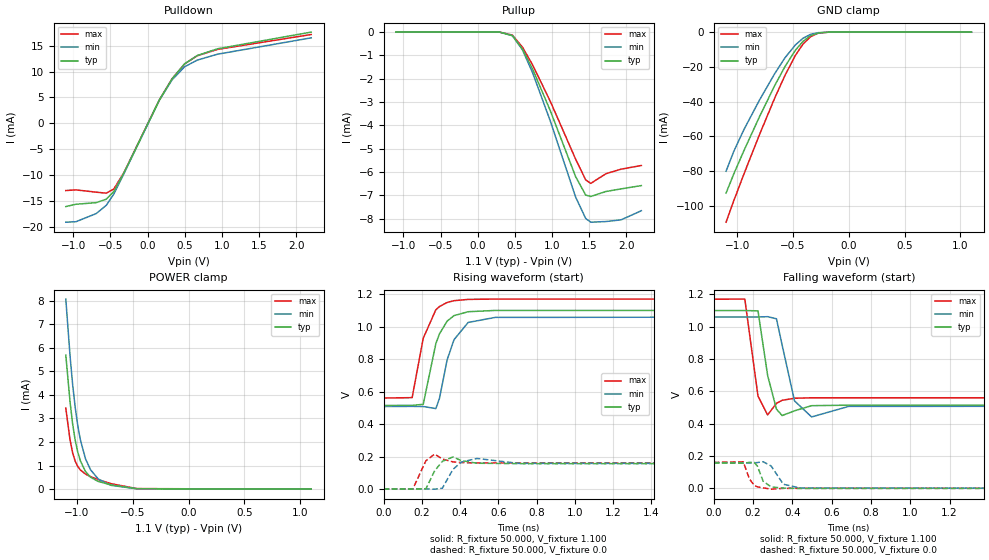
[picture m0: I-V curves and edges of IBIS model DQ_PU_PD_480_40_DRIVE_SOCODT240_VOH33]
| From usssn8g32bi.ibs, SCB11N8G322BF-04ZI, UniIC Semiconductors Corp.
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|   Model DQ_PU_PD_480_40_DRIVE_SOCODT240_VOH33
[Model] DQ_PU_PD_480_40_DRIVE_SOCODT240_VOH33
Model_type I/O
Polarity   Inverting
Vinl =  98.000mV
Vinh =  0.268V
Vmeas =  0.183V
Rref =  50.000
Vref =  0.183V
C_comp   1.020pF   1.010pF   1.030pF
[Model Spec]
Vinh   0.268V   0.262V   0.280V
Vinl   98.000mV   92.000mV   0.110V
Vmeas   0.183V   0.177V   0.195V
Vref   0.183V   0.177V   0.195V
Rref   50.000   NA   NA
[Temperature Range]   25.000   85.000   -40.000
[Voltage Range]   1.100V   1.060V   1.170V
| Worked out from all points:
|   slope of the pulldown table from 0 to 0.165 V, typ, clamps not added: 35.3 ohm
|   GND clamp passes 1 mA (typ) near -0.30 V on its own axis
|   POWER clamp passes 1 mA (typ) near -0.95 V on its own axis
|   rising waveform, R_fixture 50.000, V_fixture 1.100: 20-80 % time 76.4ps typ, 79.4ps min, 73.5ps max; typ from 0.514 V to 1.1 V
|   rising waveform, R_fixture 50.000, V_fixture 0.0: 20-80 % time 36.1ps typ, 44ps min, 29.7ps max; typ from 0 V to 0.156 V
|   falling waveform, R_fixture 50.000, V_fixture 1.100: 20-80 % time 40.5ps typ, 51.4ps min, 33.2ps max; typ from 1.1 V to 0.514 V
|   falling waveform, R_fixture 50.000, V_fixture 0.0: 20-80 % time 33.3ps typ, 48.4ps min, 30.2ps max; typ from 0.156 V to 0 V
[Pulldown]
|Voltage   I(typ)   I(min)   I(max)
-1.1V     -16.13mA   -19.15mA   -13.03mA
-964mV    -15.68mA   -19.06mA   -12.9mA
-692mV    -15.37mA   -17.49mA   -13.34mA
-556mV    -14.7mA    -15.89mA   -13.53mA
-454mV    -13.2mA    -13.69mA   -12.73mA
-318mV    -9.609mA   -9.745mA   -9.529mA
158mV     4.492mA    4.453mA    4.512mA
328mV     8.568mA    8.368mA    8.576mA
498mV     11.5mA     10.93mA    11.48mA
668mV     13.1mA     12.21mA    13.05mA
940mV     14.4mA     13.35mA    14.28mA
2.2V      17.63mA    16.52mA    17.16mA
[Pullup]
|Voltage   I(typ)   I(min)   I(max)
-1.1V     500pA      2.606nA    0A
296mV     -2.948uA   -3.529uA   -1.641uA
466mV     -154.8uA   -152.1uA   -129.1uA
602mV     -725.8uA   -765uA     -649.5uA
738mV     -1.585mA   -1.746mA   -1.41mA
976mV     -3.374mA   -3.816mA   -2.972mA
1.316V    -6.198mA   -7.072mA   -5.446mA
1.452V    -6.989mA   -7.995mA   -6.341mA
1.52V     -7.049mA   -8.152mA   -6.489mA
1.724V    -6.835mA   -8.124mA   -6.072mA
1.928V    -6.723mA   -8.051mA   -5.878mA
2.2V      -6.582mA   -7.66mA    -5.721mA
[GND_clamp]
|Voltage   I(typ)   I(min)   I(max)
-1.1V     -92.78mA   -80.14mA   -109.5mA
-1.031V   -81.73mA   -68.77mA   -97.17mA
-939mV    -68.18mA   -56.07mA   -81.64mA
-801mV    -48.85mA   -39.25mA   -59.15mA
-663mV    -30.71mA   -23.84mA   -37.89mA
-571mV    -19.76mA   -14.75mA   -24.85mA
-479mV    -10.5mA    -7.415mA   -13.5mA
-410mV    -5.313mA   -3.546mA   -6.916mA
-341mV    -2.007mA   -1.262mA   -2.59mA
-272mV    -506.9uA   -323.5uA   -609.8uA
-180mV    -45.65uA   -36.06uA   -43.55uA
1.1V      0A         0A         0A
[POWER_clamp]
|Voltage   I(typ)   I(min)   I(max)
-1.1V     5.691mA    8.066mA    3.44mA
-1.062V   3.709mA    5.665mA    2.092mA
-1.039V   2.781mA    4.457mA    1.546mA
-1.016V   2.086mA    3.48mA     1.193mA
-993mV    1.578mA    2.707mA    966.5uA
-970mV    1.21mA     2.107mA    818.5uA
-924mV    750.8uA    1.296mA    641.3uA
-878mV    507uA      821.4uA    530.2uA
-809mV    327.4uA    430uA      403.3uA
-694mV    178.4uA    161uA      233uA
-464mV    19.89uA    15.19uA    23.61uA
1.1V      0A         0A         0A
[Ramp]
| variable   typ   min   max
dV/dt_r   93.601m/36.231p   94.433m/44.047p   96.210m/29.958p
dV/dt_f   0.351/40.612p   0.331/51.354p   0.366/33.320p
R_load = 50.000
[Rising Waveform]
R_fixture= 50.000
V_fixture= 1.100
V_fixture_min= 1.060
V_fixture_max= 1.170
|time   V(typ)   V(min)   V(max)
0s        514.4mV    508.1mV    560.3mV
149ps     515.2mV    508.7mV    562.7mV
207ps     521.4mV    507.9mV    928.6mV
273ps     895.6mV    495.3mV    1.104V
292ps     956mV      558.4mV    1.124V
332ps     1.034V     795.8mV    1.149V
368ps     1.068V     919.6mV    1.16V
442ps     1.092V     1.026V     1.168V
584ps     1.1V       1.057V     1.17V
3ns       1.1V       1.06V      1.17V
[Rising Waveform]
R_fixture= 50.000
V_fixture= 0.0
V_fixture_min= 0.0
V_fixture_max= 0.0
|time   V(typ)   V(min)   V(max)
0s        2.608uV    4.994uV    616.3nV
153ps     334.6uV    6.715uV    864.6uV
221ps     1.036mV    601.6uV    174mV
267ps     112.8mV    -1.201mV   214.9mV
307ps     170.1mV    4.693mV    184.7mV
362ps     197.2mV    120mV      166.9mV
406ps     175.3mV    165.6mV    162.6mV
488ps     158.6mV    188mV      160.7mV
706ps     156mV      157.6mV    160.3mV
3ns       156mV      157.4mV    160.3mV
[Falling Waveform]
R_fixture= 50.000
V_fixture= 1.100
V_fixture_min= 1.060
V_fixture_max= 1.170
|time   V(typ)   V(min)   V(max)
0s        1.1V       1.06V      1.17V
158ps     1.1V       1.06V      1.171V
225ps     1.098V     1.06V      570.6mV
274ps     698.7mV    1.062V     454.3mV
319ps     490mV      1.049V     525.6mV
348ps     450.1mV    885.6mV    544.7mV
411ps     479.4mV    540.7mV    557.3mV
498ps     511.3mV    441.6mV    560mV
687ps     514.4mV    507mV      560.3mV
3ns       514.4mV    508.1mV    560.3mV
[Falling Waveform]
R_fixture= 50.000
V_fixture= 0.0
V_fixture_min= 0.0
V_fixture_max= 0.0
|time   V(typ)   V(min)   V(max)
0s        156mV      157.4mV    160.3mV
150ps     155.8mV    157.2mV    163.8mV
182ps     160.3mV    157mV      56.65mV
206ps     160.8mV    157.6mV    18.33mV
222ps     137.2mV    159.3mV    8.829mV
251ps     44.49mV    164.5mV    2.7mV
292ps     8.449mV    138.2mV    -5.342mV
354ps     1.084mV    25.17mV    -437.4uV
440ps     -1.073mV   1.675mV    -10.17uV
3ns       2.504uV    4.982uV    347.8nV
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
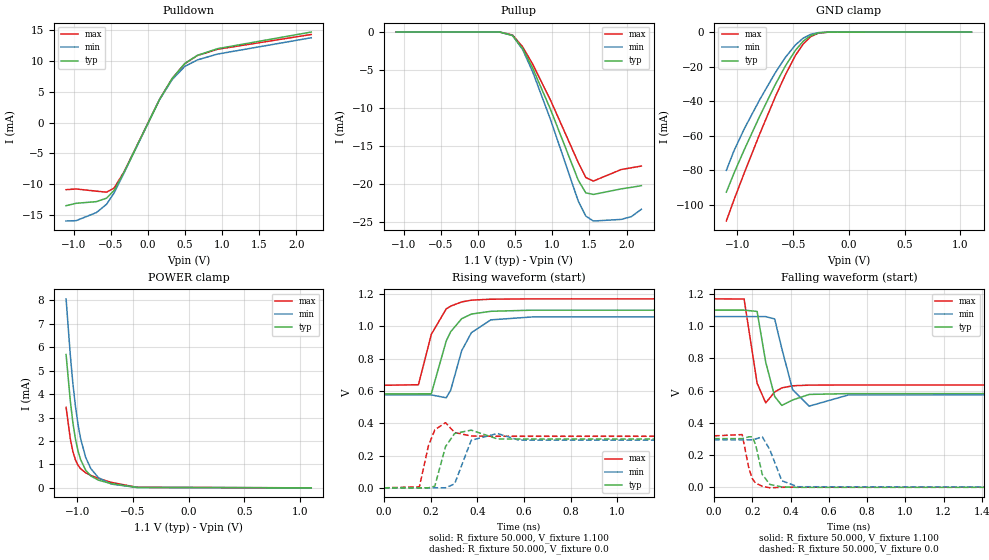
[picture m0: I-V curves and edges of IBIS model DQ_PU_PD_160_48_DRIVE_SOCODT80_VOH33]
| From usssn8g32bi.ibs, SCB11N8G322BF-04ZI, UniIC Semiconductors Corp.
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|   Model DQ_PU_PD_160_48_DRIVE_SOCODT80_VOH33
[Model] DQ_PU_PD_160_48_DRIVE_SOCODT80_VOH33
Model_type I/O
Polarity   Inverting
Vinl =  98.000mV
Vinh =  0.268V
Vmeas =  0.183V
Rref =  50.000
Vref =  0.183V
C_comp   1.020pF   1.010pF   1.030pF
[Model Spec]
Vinh   0.268V   0.262V   0.280V
Vinl   98.000mV   92.000mV   0.110V
Vmeas   0.183V   0.177V   0.195V
Vref   0.183V   0.177V   0.195V
Rref   50.000   NA   NA
[Temperature Range]   25.000   85.000   -40.000
[Voltage Range]   1.100V   1.060V   1.170V
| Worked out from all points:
|   slope of the pulldown table from 0 to 0.165 V, typ, clamps not added: 42.3 ohm
|   GND clamp passes 1 mA (typ) near -0.30 V on its own axis
|   POWER clamp passes 1 mA (typ) near -0.95 V on its own axis
|   rising waveform, R_fixture 50.000, V_fixture 1.100: 20-80 % time 74.8ps typ, 77.1ps min, 72.3ps max; typ from 0.582 V to 1.1 V
|   rising waveform, R_fixture 50.000, V_fixture 0.0: 20-80 % time 30.4ps typ, 37.1ps min, 24.9ps max; typ from 0 V to 0.302 V
|   falling waveform, R_fixture 50.000, V_fixture 1.100: 20-80 % time 42.6ps typ, 53.7ps min, 34.5ps max; typ from 1.1 V to 0.582 V
|   falling waveform, R_fixture 50.000, V_fixture 0.0: 20-80 % time 36.7ps typ, 52.9ps min, 32.5ps max; typ from 0.302 V to 0 V
[Pulldown]
|Voltage   I(typ)   I(min)   I(max)
-1.1V     -13.51mA   -16mA      -10.91mA
-964mV    -13.12mA   -15.94mA   -10.79mA
-692mV    -12.85mA   -14.63mA   -11.15mA
-556mV    -12.29mA   -13.29mA   -11.31mA
-454mV    -11.04mA   -11.45mA   -10.65mA
-318mV    -8.03mA    -8.142mA   -7.964mA
158mV     3.751mA    3.718mA    3.768mA
328mV     7.153mA    6.985mA    7.158mA
498mV     9.598mA    9.123mA    9.581mA
668mV     10.93mA    10.18mA    10.89mA
940mV     12.01mA    11.13mA    11.91mA
2.2V      14.71mA    13.78mA    14.31mA
[Pullup]
|Voltage   I(typ)   I(min)   I(max)
-1.1V     1.606nA    7.718nA    0A
296mV     -8.845uA   -10.59uA   -4.922uA
466mV     -464.7uA   -456.5uA   -387.5uA
602mV     -2.18mA    -2.299mA   -1.951mA
738mV     -4.764mA   -5.249mA   -4.236mA
976mV     -10.14mA   -11.47mA   -8.932mA
1.35V     -19.45mA   -22.19mA   -17.13mA
1.452V    -21.12mA   -24.17mA   -19.11mA
1.554V    -21.33mA   -24.82mA   -19.57mA
1.928V    -20.6mA    -24.61mA   -18.06mA
2.064V    -20.4mA    -24.25mA   -17.83mA
2.2V      -20.18mA   -23.28mA   -17.6mA
[GND_clamp]
|Voltage   I(typ)   I(min)   I(max)
-1.1V     -92.78mA   -80.14mA   -109.5mA
-1.031V   -81.73mA   -68.77mA   -97.17mA
-939mV    -68.18mA   -56.07mA   -81.64mA
-801mV    -48.85mA   -39.25mA   -59.15mA
-663mV    -30.71mA   -23.84mA   -37.89mA
-571mV    -19.76mA   -14.75mA   -24.85mA
-479mV    -10.5mA    -7.415mA   -13.5mA
-410mV    -5.313mA   -3.546mA   -6.916mA
-341mV    -2.007mA   -1.262mA   -2.59mA
-272mV    -506.9uA   -323.5uA   -609.8uA
-180mV    -45.65uA   -36.06uA   -43.55uA
1.1V      0A         0A         0A
[POWER_clamp]
|Voltage   I(typ)   I(min)   I(max)
-1.1V     5.691mA    8.066mA    3.44mA
-1.062V   3.709mA    5.665mA    2.092mA
-1.039V   2.781mA    4.457mA    1.546mA
-1.016V   2.086mA    3.48mA     1.193mA
-993mV    1.578mA    2.707mA    966.5uA
-970mV    1.21mA     2.107mA    818.5uA
-924mV    750.8uA    1.296mA    641.3uA
-878mV    507uA      821.4uA    530.2uA
-809mV    327.4uA    430uA      403.3uA
-694mV    178.4uA    161uA      233uA
-464mV    19.89uA    15.19uA    23.61uA
1.1V      0A         0A         0A
[Ramp]
| variable   typ   min   max
dV/dt_r   0.181/30.338p   0.177/37.221p   0.192/24.997p
dV/dt_f   0.311/42.683p   0.291/53.720p   0.321/34.473p
R_load = 50.000
[Rising Waveform]
R_fixture= 50.000
V_fixture= 1.100
V_fixture_min= 1.060
V_fixture_max= 1.170
|time   V(typ)   V(min)   V(max)
0s        581.6mV    575.3mV    635mV
148ps     582.3mV    575.9mV    638.4mV
203ps     582.5mV    575.5mV    950.6mV
267ps     909.6mV    557.5mV    1.108V
286ps     966.4mV    604.3mV    1.125V
333ps     1.047V     848.3mV    1.151V
375ps     1.076V     961mV      1.162V
458ps     1.093V     1.04V      1.168V
635ps     1.1V       1.058V     1.17V
3ns       1.1V       1.06V      1.17V
[Rising Waveform]
R_fixture= 50.000
V_fixture= 0.0
V_fixture_min= 0.0
V_fixture_max= 0.0
|time   V(typ)   V(min)   V(max)
0s        2.898uV    5.55uV     685nV
152ps     91.66uV    20.89uV    6.439mV
191ps     381.7uV    61.02uV    262.2mV
218ps     10.25mV    267.5uV    359mV
264ps     255.6mV    221.2uV    403.3mV
303ps     336.5mV    24.48mV    342.4mV
374ps     357.2mV    294.4mV    320.9mV
487ps     302.7mV    336.6mV    319.2mV
578ps     302.1mV    295.3mV    319.2mV
3ns       302.1mV    295.1mV    319.2mV
[Falling Waveform]
R_fixture= 50.000
V_fixture= 1.100
V_fixture_min= 1.060
V_fixture_max= 1.170
|time   V(typ)   V(min)   V(max)
0s        1.1V       1.06V      1.17V
157ps     1.1V       1.06V      1.169V
225ps     1.092V     1.06V      646.1mV
270ps     776.8mV    1.06V      524.1mV
317ps     563.5mV    1.045V     591.6mV
354ps     508.2mV    861.6mV    617mV
411ps     541.9mV    605.2mV    630.1mV
497ps     576.5mV    503.7mV    634.3mV
705ps     581.5mV    574mV      635mV
3ns       581.6mV    575.3mV    635mV
[Falling Waveform]
R_fixture= 50.000
V_fixture= 0.0
V_fixture_min= 0.0
V_fixture_max= 0.0
|time   V(typ)   V(min)   V(max)
0s        302.1mV    295.1mV    319.2mV
147ps     301.7mV    294.7mV    326.9mV
182ps     313.2mV    294.1mV    117.4mV
199ps     313.6mV    295.3mV    55.12mV
217ps     266mV      299.6mV    25.58mV
252ps     79.39mV    313.4mV    6.149mV
292ps     17.21mV    232.2mV    -3.831mV
354ps     2.133mV    40.59mV    -401.6uV
438ps     -1.021mV   3.098mV    -13.98uV
3ns       -956.6nV   5.401uV    179.7nV
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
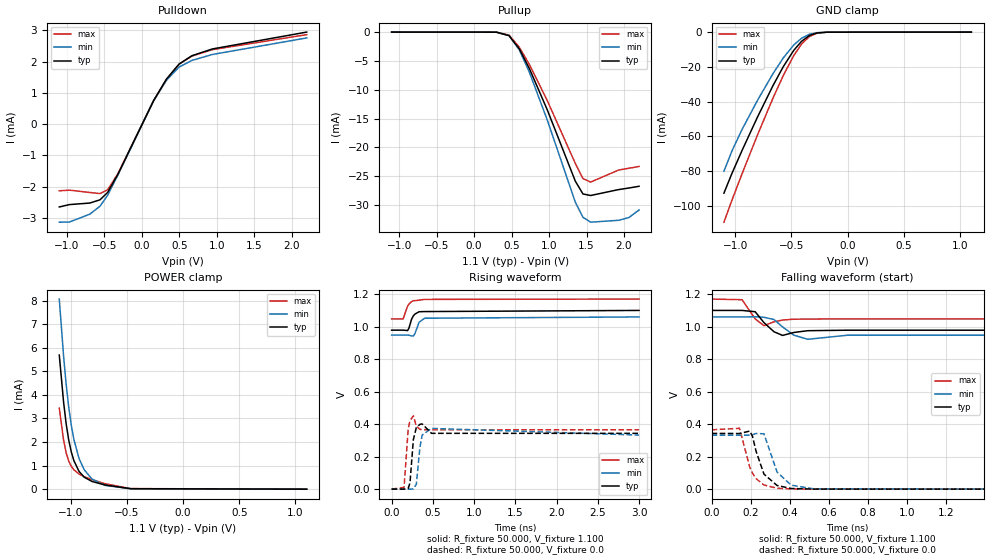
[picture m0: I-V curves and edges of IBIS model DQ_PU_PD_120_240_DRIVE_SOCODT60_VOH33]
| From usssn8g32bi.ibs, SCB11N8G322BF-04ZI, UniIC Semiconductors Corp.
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|   Model DQ_PU_PD_120_240_DRIVE_SOCODT60_VOH33
[Model] DQ_PU_PD_120_240_DRIVE_SOCODT60_VOH33
Model_type I/O
Polarity   Inverting
Vinl =  98.000mV
Vinh =  0.268V
Vmeas =  0.183V
Rref =  50.000
Vref =  0.183V
C_comp   1.020pF   1.010pF   1.030pF
[Model Spec]
Vinh   0.268V   0.262V   0.280V
Vinl   98.000mV   92.000mV   0.110V
Vmeas   0.183V   0.177V   0.195V
Vref   0.183V   0.177V   0.195V
Rref   50.000   NA   NA
[Temperature Range]   25.000   85.000   -40.000
[Voltage Range]   1.100V   1.060V   1.170V
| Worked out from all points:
|   slope of the pulldown table from 0 to 0.165 V, typ, clamps not added: 211 ohm
|   GND clamp passes 1 mA (typ) near -0.30 V on its own axis
|   POWER clamp passes 1 mA (typ) near -0.95 V on its own axis
|   rising waveform, R_fixture 50.000, V_fixture 1.100: 20-80 % time 62ps typ, 58.1ps min, 63.2ps max; typ from 0.978 V to 1.1 V
|   rising waveform, R_fixture 50.000, V_fixture 0.0: 20-80 % time 29.3ps typ, 36.2ps min, 23.8ps max; typ from 0 V to 0.343 V
|   falling waveform, R_fixture 50.000, V_fixture 1.100: 20-80 % time 47.3ps typ, 62.3ps min, 36.3ps max; typ from 1.1 V to 0.978 V
|   falling waveform, R_fixture 50.000, V_fixture 0.0: 20-80 % time 62.1ps typ, 67.8ps min, 59.5ps max; typ from 0.343 V to 0 V
[Pulldown]
|Voltage   I(typ)   I(min)   I(max)
-1.1V     -2.652mA   -3.14mA    -2.134mA
-964mV    -2.576mA   -3.135mA   -2.114mA
-692mV    -2.527mA   -2.882mA   -2.189mA
-556mV    -2.422mA   -2.626mA   -2.223mA
-454mV    -2.185mA   -2.274mA   -2.101mA
-318mV    -1.604mA   -1.629mA   -1.589mA
158mV     752.2uA    745.4uA    755.4uA
328mV     1.434mA    1.4mA      1.435mA
498mV     1.924mA    1.828mA    1.92mA
668mV     2.19mA     2.04mA     2.18mA
940mV     2.407mA    2.23mA     2.385mA
2.2V      2.948mA    2.761mA    2.866mA
[Pullup]
|Voltage   I(typ)   I(min)   I(max)
-1.1V     2.1nA      10.33nA    0A
296mV     -11.79uA   -14.12uA   -6.562uA
466mV     -619.2uA   -608.2uA   -516.4uA
602mV     -2.903mA   -3.06mA    -2.598mA
738mV     -6.341mA   -6.984mA   -5.639mA
976mV     -13.49mA   -15.26mA   -11.89mA
1.35V     -25.87mA   -29.51mA   -22.79mA
1.452V    -28.09mA   -32.14mA   -25.42mA
1.554V    -28.36mA   -32.99mA   -26.03mA
1.928V    -27.33mA   -32.66mA   -23.94mA
2.064V    -27.06mA   -32.19mA   -23.63mA
2.2V      -26.76mA   -30.87mA   -23.32mA
[GND_clamp]
|Voltage   I(typ)   I(min)   I(max)
-1.1V     -92.78mA   -80.14mA   -109.5mA
-1.031V   -81.73mA   -68.77mA   -97.17mA
-939mV    -68.18mA   -56.07mA   -81.64mA
-801mV    -48.85mA   -39.25mA   -59.15mA
-663mV    -30.71mA   -23.84mA   -37.89mA
-571mV    -19.76mA   -14.75mA   -24.85mA
-479mV    -10.5mA    -7.415mA   -13.5mA
-410mV    -5.313mA   -3.546mA   -6.916mA
-341mV    -2.007mA   -1.262mA   -2.59mA
-272mV    -506.9uA   -323.5uA   -609.8uA
-180mV    -45.65uA   -36.06uA   -43.55uA
1.1V      0A         0A         0A
[POWER_clamp]
|Voltage   I(typ)   I(min)   I(max)
-1.1V     5.691mA    8.066mA    3.44mA
-1.062V   3.709mA    5.665mA    2.092mA
-1.039V   2.781mA    4.457mA    1.546mA
-1.016V   2.086mA    3.48mA     1.193mA
-993mV    1.578mA    2.707mA    966.5uA
-970mV    1.21mA     2.107mA    818.5uA
-924mV    750.8uA    1.296mA    641.3uA
-878mV    507uA      821.4uA    530.2uA
-809mV    327.4uA    430uA      403.3uA
-694mV    178.4uA    161uA      233uA
-464mV    19.89uA    15.19uA    23.61uA
1.1V      0A         0A         0A
[Ramp]
| variable   typ   min   max
dV/dt_r   0.206/29.379p   0.200/36.204p   0.219/24.028p
dV/dt_f   72.904m/47.402p   67.052m/62.298p   73.268m/36.318p
R_load = 50.000
[Rising Waveform]
R_fixture= 50.000
V_fixture= 1.100
V_fixture_min= 1.060
V_fixture_max= 1.170
|time   V(typ)   V(min)   V(max)
0s        978.5mV    948.3mV    1.048V
140ps     978.8mV    948.4mV    1.048V
194ps     976mV      948.5mV    1.127V
210ps     990.9mV    947.5mV    1.139V
242ps     1.046V     943mV      1.154V
263ps     1.066V     942.5mV    1.16V
281ps     1.077V     955.1mV    1.16V
333ps     1.092V     1.027V     1.163V
401ps     1.093V     1.052V     1.168V
3ns       1.1V       1.06V      1.17V
[Rising Waveform]
R_fixture= 50.000
V_fixture= 0.0
V_fixture_min= 0.0
V_fixture_max= 0.0
|time   V(typ)   V(min)   V(max)
0s        5.235uV    10.02uV    1.24uV
151ps     -258.7uV   64.02uV    10.64mV
201ps     3.499mV    -217.6uV   369.5mV
223ps     39.28mV    -435.2uV   421.7mV
264ps     305.5mV    1.271mV    451.1mV
300ps     379.6mV    29.77mV    386.5mV
343ps     398.6mV    256.6mV    368.1mV
371ps     401.1mV    332.8mV    366.1mV
484ps     343.4mV    373.7mV    365.2mV
3ns       343.2mV    332.5mV    365.2mV
[Falling Waveform]
R_fixture= 50.000
V_fixture= 1.100
V_fixture_min= 1.060
V_fixture_max= 1.170
|time   V(typ)   V(min)   V(max)
0s        1.1V       1.06V      1.17V
156ps     1.1V       1.06V      1.166V
223ps     1.092V     1.061V     1.048V
268ps     1.025V     1.058V     1.006V
319ps     969mV      1.044V     1.03V
363ps     946.2mV    998.7mV    1.041V
421ps     964.5mV    947.6mV    1.046V
492ps     975.3mV    922.4mV    1.047V
696ps     978.4mV    947.6mV    1.048V
3ns       978.5mV    948.3mV    1.048V
[Falling Waveform]
R_fixture= 50.000
V_fixture= 0.0
V_fixture_min= 0.0
V_fixture_max= 0.0
|time   V(typ)   V(min)   V(max)
0s        343.2mV    332.5mV    365.2mV
143ps     342.5mV    332mV      374.6mV
195ps     357.6mV    332.2mV    136.1mV
209ps     326.1mV    335.3mV    99.03mV
228ps     231.6mV    342.8mV    64.35mV
268ps     92.49mV    340.6mV    25.71mV
335ps     22.55mV    105mV      5.646mV
407ps     4.206mV    24.7mV     1.203mV
523ps     417.4uV    2.049mV    99.42uV
3ns       5.223uV    10.02uV    1.279uV
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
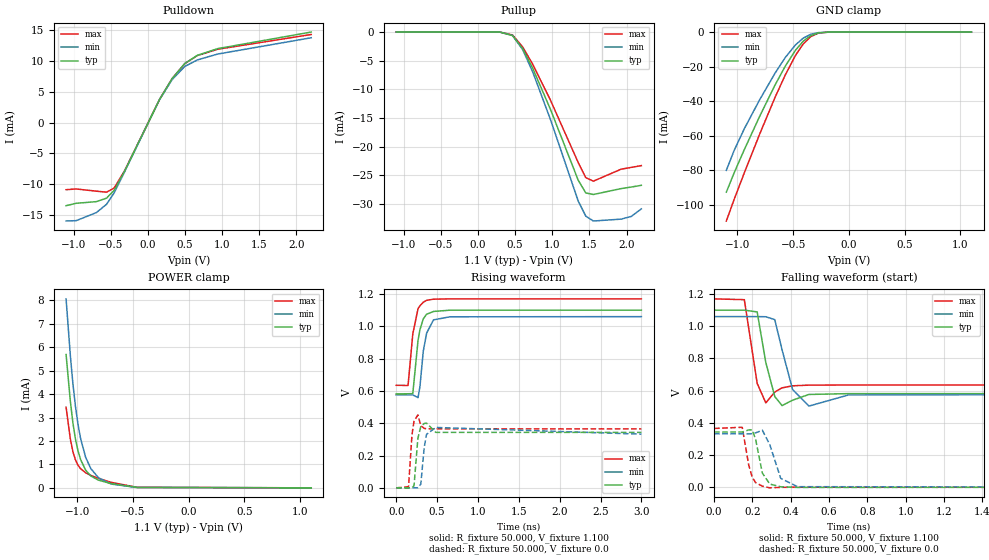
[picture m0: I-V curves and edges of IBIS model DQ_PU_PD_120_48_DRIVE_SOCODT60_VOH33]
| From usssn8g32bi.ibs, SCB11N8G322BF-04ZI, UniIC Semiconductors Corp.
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|   Model DQ_PU_PD_120_48_DRIVE_SOCODT60_VOH33
[Model] DQ_PU_PD_120_48_DRIVE_SOCODT60_VOH33
Model_type I/O
Polarity   Inverting
Vinl =  98.000mV
Vinh =  0.268V
Vmeas =  0.183V
Rref =  50.000
Vref =  0.183V
C_comp   1.020pF   1.010pF   1.030pF
[Model Spec]
Vinh   0.268V   0.262V   0.280V
Vinl   98.000mV   92.000mV   0.110V
Vmeas   0.183V   0.177V   0.195V
Vref   0.183V   0.177V   0.195V
Rref   50.000   NA   NA
[Temperature Range]   25.000   85.000   -40.000
[Voltage Range]   1.100V   1.060V   1.170V
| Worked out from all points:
|   slope of the pulldown table from 0 to 0.165 V, typ, clamps not added: 42.3 ohm
|   GND clamp passes 1 mA (typ) near -0.30 V on its own axis
|   POWER clamp passes 1 mA (typ) near -0.95 V on its own axis
|   rising waveform, R_fixture 50.000, V_fixture 1.100: 20-80 % time 74.6ps typ, 76.3ps min, 72.2ps max; typ from 0.582 V to 1.1 V
|   rising waveform, R_fixture 50.000, V_fixture 0.0: 20-80 % time 28.7ps typ, 35.2ps min, 23.5ps max; typ from 0 V to 0.343 V
|   falling waveform, R_fixture 50.000, V_fixture 1.100: 20-80 % time 42.8ps typ, 54ps min, 34.6ps max; typ from 1.1 V to 0.582 V
|   falling waveform, R_fixture 50.000, V_fixture 0.0: 20-80 % time 37ps typ, 52.6ps min, 32.8ps max; typ from 0.343 V to 0 V
[Pulldown]
|Voltage   I(typ)   I(min)   I(max)
-1.1V     -13.51mA   -16mA      -10.91mA
-964mV    -13.12mA   -15.94mA   -10.79mA
-692mV    -12.85mA   -14.63mA   -11.15mA
-556mV    -12.29mA   -13.29mA   -11.31mA
-454mV    -11.04mA   -11.45mA   -10.65mA
-318mV    -8.03mA    -8.142mA   -7.964mA
158mV     3.751mA    3.718mA    3.768mA
328mV     7.153mA    6.985mA    7.158mA
498mV     9.598mA    9.123mA    9.581mA
668mV     10.93mA    10.18mA    10.89mA
940mV     12.01mA    11.13mA    11.91mA
2.2V      14.71mA    13.78mA    14.31mA
[Pullup]
|Voltage   I(typ)   I(min)   I(max)
-1.1V     2.1nA      10.33nA    0A
296mV     -11.79uA   -14.12uA   -6.562uA
466mV     -619.2uA   -608.2uA   -516.4uA
602mV     -2.903mA   -3.06mA    -2.598mA
738mV     -6.341mA   -6.984mA   -5.639mA
976mV     -13.49mA   -15.26mA   -11.89mA
1.35V     -25.87mA   -29.51mA   -22.79mA
1.452V    -28.09mA   -32.14mA   -25.42mA
1.554V    -28.36mA   -32.99mA   -26.03mA
1.928V    -27.33mA   -32.66mA   -23.94mA
2.064V    -27.06mA   -32.19mA   -23.63mA
2.2V      -26.76mA   -30.87mA   -23.32mA
[GND_clamp]
|Voltage   I(typ)   I(min)   I(max)
-1.1V     -92.78mA   -80.14mA   -109.5mA
-1.031V   -81.73mA   -68.77mA   -97.17mA
-939mV    -68.18mA   -56.07mA   -81.64mA
-801mV    -48.85mA   -39.25mA   -59.15mA
-663mV    -30.71mA   -23.84mA   -37.89mA
-571mV    -19.76mA   -14.75mA   -24.85mA
-479mV    -10.5mA    -7.415mA   -13.5mA
-410mV    -5.313mA   -3.546mA   -6.916mA
-341mV    -2.007mA   -1.262mA   -2.59mA
-272mV    -506.9uA   -323.5uA   -609.8uA
-180mV    -45.65uA   -36.06uA   -43.55uA
1.1V      0A         0A         0A
[POWER_clamp]
|Voltage   I(typ)   I(min)   I(max)
-1.1V     5.691mA    8.066mA    3.44mA
-1.062V   3.709mA    5.665mA    2.092mA
-1.039V   2.781mA    4.457mA    1.546mA
-1.016V   2.086mA    3.48mA     1.193mA
-993mV    1.578mA    2.707mA    966.5uA
-970mV    1.21mA     2.107mA    818.5uA
-924mV    750.8uA    1.296mA    641.3uA
-878mV    507uA      821.4uA    530.2uA
-809mV    327.4uA    430uA      403.3uA
-694mV    178.4uA    161uA      233uA
-464mV    19.89uA    15.19uA    23.61uA
1.1V      0A         0A         0A
[Ramp]
| variable   typ   min   max
dV/dt_r   0.206/28.866p   0.200/35.270p   0.219/23.794p
dV/dt_f   0.311/42.802p   0.291/53.959p   0.321/34.634p
R_load = 50.000
[Rising Waveform]
R_fixture= 50.000
V_fixture= 1.100
V_fixture_min= 1.060
V_fixture_max= 1.170
|time   V(typ)   V(min)   V(max)
0s        581.6mV    575.3mV    635mV
145ps     582.5mV    575.8mV    633.8mV
203ps     583.2mV    575.5mV    953mV
267ps     912.5mV    558.4mV    1.109V
290ps     978.1mV    624.6mV    1.127V
331ps     1.046V     844.9mV    1.149V
372ps     1.075V     957.8mV    1.161V
456ps     1.092V     1.04V      1.168V
657ps     1.1V       1.059V     1.17V
3ns       1.1V       1.06V      1.17V
[Rising Waveform]
R_fixture= 50.000
V_fixture= 0.0
V_fixture_min= 0.0
V_fixture_max= 0.0
|time   V(typ)   V(min)   V(max)
0s        2.898uV    5.55uV     685nV
151ps     18.65uV    28.55uV    7.153mV
193ps     600.2uV    46.35uV    328.3mV
218ps     13.39mV    176.7uV    413.3mV
265ps     306.2mV    420.2uV    451.1mV
301ps     380mV      23.2mV     385.2mV
343ps     398.5mV    251.7mV    368.1mV
371ps     401mV      331.4mV    366.1mV
485ps     343.4mV    373.8mV    365.2mV
3ns       343.2mV    332.5mV    365.2mV
[Falling Waveform]
R_fixture= 50.000
V_fixture= 1.100
V_fixture_min= 1.060
V_fixture_max= 1.170
|time   V(typ)   V(min)   V(max)
0s        1.1V       1.06V      1.17V
158ps     1.1V       1.06V      1.165V
225ps     1.089V     1.06V      645.6mV
270ps     775.3mV    1.059V     524mV
317ps     563.1mV    1.041V     591.6mV
355ps     507.3mV    853.4mV    617.4mV
410ps     540.7mV    607.1mV    630mV
495ps     576.3mV    504mV      634.3mV
704ps     581.5mV    574mV      635mV
3ns       581.6mV    575.3mV    635mV
[Falling Waveform]
R_fixture= 50.000
V_fixture= 0.0
V_fixture_min= 0.0
V_fixture_max= 0.0
|time   V(typ)   V(min)   V(max)
0s        343.2mV    332.5mV    365.2mV
147ps     342.8mV    332mV      372.4mV
181ps     356.1mV    331.4mV    137.7mV
199ps     356.1mV    332.7mV    61.72mV
217ps     297.4mV    337.8mV    28.59mV
252ps     88.29mV    354.3mV    6.827mV
291ps     19.73mV    264.4mV    -3.688mV
348ps     2.922mV    55.22mV    -493.7uV
436ps     -1.09mV    3.576mV    -14.38uV
3ns       -732.6nV   5.513uV    284.7nV
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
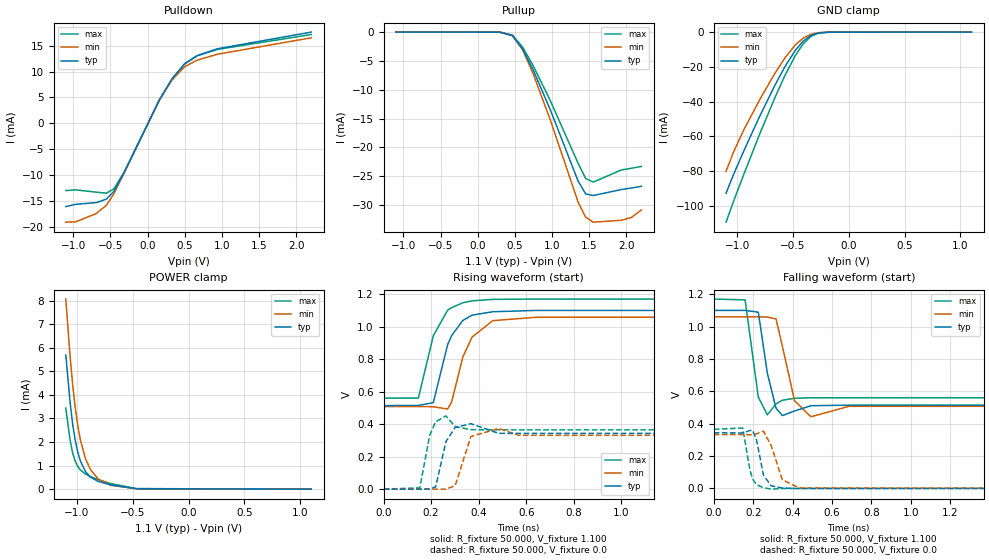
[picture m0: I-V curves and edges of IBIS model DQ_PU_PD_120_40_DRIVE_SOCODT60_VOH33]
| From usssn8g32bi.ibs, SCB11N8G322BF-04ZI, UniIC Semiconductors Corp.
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|   Model DQ_PU_PD_120_40_DRIVE_SOCODT60_VOH33
[Model] DQ_PU_PD_120_40_DRIVE_SOCODT60_VOH33
Model_type I/O
Polarity   Inverting
Vinl =  98.000mV
Vinh =  0.268V
Vmeas =  0.183V
Rref =  50.000
Vref =  0.183V
C_comp   1.020pF   1.010pF   1.030pF
[Model Spec]
Vinh   0.268V   0.262V   0.280V
Vinl   98.000mV   92.000mV   0.110V
Vmeas   0.183V   0.177V   0.195V
Vref   0.183V   0.177V   0.195V
Rref   50.000   NA   NA
[Temperature Range]   25.000   85.000   -40.000
[Voltage Range]   1.100V   1.060V   1.170V
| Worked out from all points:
|   slope of the pulldown table from 0 to 0.165 V, typ, clamps not added: 35.3 ohm
|   GND clamp passes 1 mA (typ) near -0.30 V on its own axis
|   POWER clamp passes 1 mA (typ) near -0.95 V on its own axis
|   rising waveform, R_fixture 50.000, V_fixture 1.100: 20-80 % time 75.7ps typ, 77.9ps min, 73.1ps max; typ from 0.514 V to 1.1 V
|   rising waveform, R_fixture 50.000, V_fixture 0.0: 20-80 % time 28.6ps typ, 35.1ps min, 23.5ps max; typ from 0 V to 0.343 V
|   falling waveform, R_fixture 50.000, V_fixture 1.100: 20-80 % time 40.9ps typ, 52.1ps min, 33.5ps max; typ from 1.1 V to 0.514 V
|   falling waveform, R_fixture 50.000, V_fixture 0.0: 20-80 % time 34.2ps typ, 51.6ps min, 29.8ps max; typ from 0.343 V to 0 V
[Pulldown]
|Voltage   I(typ)   I(min)   I(max)
-1.1V     -16.13mA   -19.15mA   -13.03mA
-964mV    -15.68mA   -19.06mA   -12.9mA
-692mV    -15.37mA   -17.49mA   -13.34mA
-556mV    -14.7mA    -15.89mA   -13.53mA
-454mV    -13.2mA    -13.69mA   -12.73mA
-318mV    -9.609mA   -9.745mA   -9.529mA
158mV     4.492mA    4.453mA    4.512mA
328mV     8.568mA    8.368mA    8.576mA
498mV     11.5mA     10.93mA    11.48mA
668mV     13.1mA     12.21mA    13.05mA
940mV     14.4mA     13.35mA    14.28mA
2.2V      17.63mA    16.52mA    17.16mA
[Pullup]
|Voltage   I(typ)   I(min)   I(max)
-1.1V     2.1nA      10.33nA    0A
296mV     -11.79uA   -14.12uA   -6.562uA
466mV     -619.2uA   -608.2uA   -516.4uA
602mV     -2.903mA   -3.06mA    -2.598mA
738mV     -6.341mA   -6.984mA   -5.639mA
976mV     -13.49mA   -15.26mA   -11.89mA
1.35V     -25.87mA   -29.51mA   -22.79mA
1.452V    -28.09mA   -32.14mA   -25.42mA
1.554V    -28.36mA   -32.99mA   -26.03mA
1.928V    -27.33mA   -32.66mA   -23.94mA
2.064V    -27.06mA   -32.19mA   -23.63mA
2.2V      -26.76mA   -30.87mA   -23.32mA
[GND_clamp]
|Voltage   I(typ)   I(min)   I(max)
-1.1V     -92.78mA   -80.14mA   -109.5mA
-1.031V   -81.73mA   -68.77mA   -97.17mA
-939mV    -68.18mA   -56.07mA   -81.64mA
-801mV    -48.85mA   -39.25mA   -59.15mA
-663mV    -30.71mA   -23.84mA   -37.89mA
-571mV    -19.76mA   -14.75mA   -24.85mA
-479mV    -10.5mA    -7.415mA   -13.5mA
-410mV    -5.313mA   -3.546mA   -6.916mA
-341mV    -2.007mA   -1.262mA   -2.59mA
-272mV    -506.9uA   -323.5uA   -609.8uA
-180mV    -45.65uA   -36.06uA   -43.55uA
1.1V      0A         0A         0A
[POWER_clamp]
|Voltage   I(typ)   I(min)   I(max)
-1.1V     5.691mA    8.066mA    3.44mA
-1.062V   3.709mA    5.665mA    2.092mA
-1.039V   2.781mA    4.457mA    1.546mA
-1.016V   2.086mA    3.48mA     1.193mA
-993mV    1.578mA    2.707mA    966.5uA
-970mV    1.21mA     2.107mA    818.5uA
-924mV    750.8uA    1.296mA    641.3uA
-878mV    507uA      821.4uA    530.2uA
-809mV    327.4uA    430uA      403.3uA
-694mV    178.4uA    161uA      233uA
-464mV    19.89uA    15.19uA    23.61uA
1.1V      0A         0A         0A
[Ramp]
| variable   typ   min   max
dV/dt_r   0.206/28.662p   0.200/35.176p   0.219/23.735p
dV/dt_f   0.351/40.993p   0.331/52.121p   0.366/33.500p
R_load = 50.000
[Rising Waveform]
R_fixture= 50.000
V_fixture= 1.100
V_fixture_min= 1.060
V_fixture_max= 1.170
|time   V(typ)   V(min)   V(max)
0s        514.4mV    508.1mV    560.3mV
146ps     515.3mV    508.7mV    560.5mV
209ps     532.7mV    507.2mV    944.3mV
269ps     888.3mV    493.3mV    1.101V
286ps     945.1mV    536.3mV    1.117V
333ps     1.038V     812.7mV    1.147V
372ps     1.071V     936.1mV    1.159V
459ps     1.092V     1.037V     1.168V
642ps     1.1V       1.058V     1.17V
3ns       1.1V       1.06V      1.17V
[Rising Waveform]
R_fixture= 50.000
V_fixture= 0.0
V_fixture_min= 0.0
V_fixture_max= 0.0
|time   V(typ)   V(min)   V(max)
0s        2.608uV    4.994uV    616.3nV
152ps     89.21uV    29.48uV    8.194mV
194ps     632.6uV    70.2uV     332.9mV
219ps     14.69mV    286.8uV    414.7mV
262ps     292.2mV    417.6uV    450.8mV
301ps     379.9mV    21.56mV    385.2mV
367ps     403mV      323.8mV    366.3mV
484ps     343.4mV    373.6mV    365.2mV
568ps     343.2mV    331.6mV    365.2mV
3ns       343.2mV    332.5mV    365.2mV
[Falling Waveform]
R_fixture= 50.000
V_fixture= 1.100
V_fixture_min= 1.060
V_fixture_max= 1.170
|time   V(typ)   V(min)   V(max)
0s        1.1V       1.06V      1.17V
159ps     1.1V       1.06V      1.165V
226ps     1.089V     1.06V      563.8mV
272ps     710.6mV    1.059V     454.5mV
316ps     495.5mV    1.047V     522.2mV
348ps     449.7mV    879mV      544.7mV
410ps     478.3mV    541.6mV    557.2mV
493ps     510.8mV    442.6mV    559.9mV
685ps     514.4mV    506.9mV    560.3mV
3ns       514.4mV    508.1mV    560.3mV
[Falling Waveform]
R_fixture= 50.000
V_fixture= 0.0
V_fixture_min= 0.0
V_fixture_max= 0.0
|time   V(typ)   V(min)   V(max)
0s        343.2mV    332.5mV    365.2mV
147ps     342.8mV    332mV      373mV
183ps     357.2mV    331.4mV    116.3mV
197ps     358.9mV    332.4mV    58.12mV
217ps     299.7mV    337.7mV    22.51mV
252ps     81.86mV    354mV      4.826mV
291ps     16.04mV    265.4mV    -4.834mV
348ps     2.197mV    52.63mV    -544.1uV
434ps     -1.375mV   3.052mV    -12.01uV
3ns       2.476uV    4.849uV    177.9nV
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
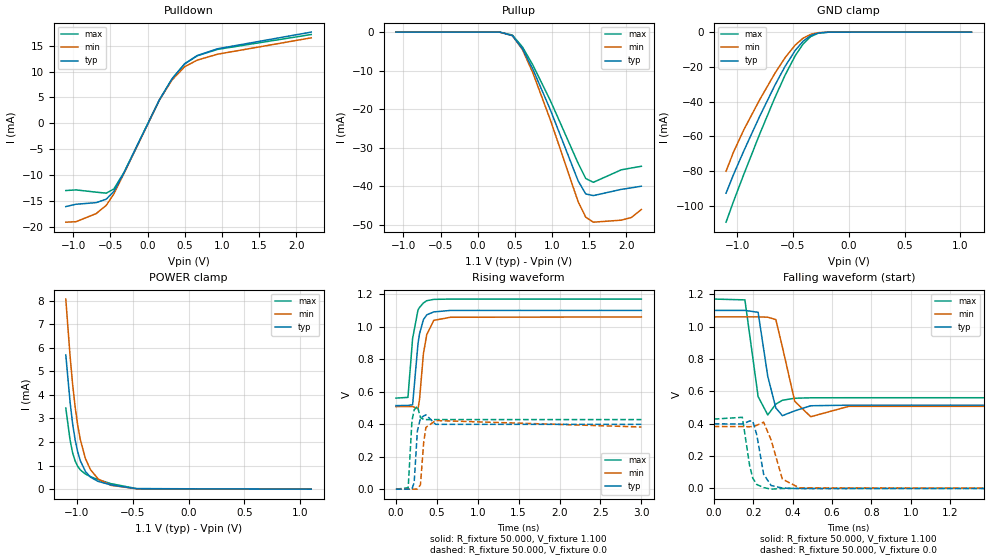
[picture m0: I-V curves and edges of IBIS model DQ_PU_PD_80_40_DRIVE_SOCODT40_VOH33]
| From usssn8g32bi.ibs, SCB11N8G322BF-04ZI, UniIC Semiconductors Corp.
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|   Model DQ_PU_PD_80_40_DRIVE_SOCODT40_VOH33
[Model] DQ_PU_PD_80_40_DRIVE_SOCODT40_VOH33
Model_type I/O
Polarity   Inverting
Vinl =  98.000mV
Vinh =  0.268V
Vmeas =  0.183V
Rref =  50.000
Vref =  0.183V
C_comp   1.020pF   1.010pF   1.030pF
[Model Spec]
Vinh   0.268V   0.262V   0.280V
Vinl   98.000mV   92.000mV   0.110V
Vmeas   0.183V   0.177V   0.195V
Vref   0.183V   0.177V   0.195V
Rref   50.000   NA   NA
[Temperature Range]   25.000   85.000   -40.000
[Voltage Range]   1.100V   1.060V   1.170V
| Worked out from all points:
|   slope of the pulldown table from 0 to 0.165 V, typ, clamps not added: 35.3 ohm
|   GND clamp passes 1 mA (typ) near -0.30 V on its own axis
|   POWER clamp passes 1 mA (typ) near -0.95 V on its own axis
|   rising waveform, R_fixture 50.000, V_fixture 1.100: 20-80 % time 75ps typ, 76.6ps min, 72.8ps max; typ from 0.514 V to 1.1 V
|   rising waveform, R_fixture 50.000, V_fixture 0.0: 20-80 % time 26.6ps typ, 33.2ps min, 21.7ps max; typ from 0 V to 0.399 V
|   falling waveform, R_fixture 50.000, V_fixture 1.100: 20-80 % time 41.2ps typ, 52.6ps min, 33.6ps max; typ from 1.1 V to 0.514 V
|   falling waveform, R_fixture 50.000, V_fixture 0.0: 20-80 % time 35ps typ, 51.6ps min, 30.1ps max; typ from 0.399 V to 0 V
[Pulldown]
|Voltage   I(typ)   I(min)   I(max)
-1.1V     -16.13mA   -19.15mA   -13.03mA
-964mV    -15.68mA   -19.06mA   -12.9mA
-692mV    -15.37mA   -17.49mA   -13.34mA
-556mV    -14.7mA    -15.89mA   -13.53mA
-454mV    -13.2mA    -13.69mA   -12.73mA
-318mV    -9.609mA   -9.745mA   -9.529mA
158mV     4.492mA    4.453mA    4.512mA
328mV     8.568mA    8.368mA    8.576mA
498mV     11.5mA     10.93mA    11.48mA
668mV     13.1mA     12.21mA    13.05mA
940mV     14.4mA     13.35mA    14.28mA
2.2V      17.63mA    16.52mA    17.16mA
[Pullup]
|Voltage   I(typ)   I(min)   I(max)
-1.1V     3.1nA      15.54nA    0A
296mV     -17.69uA   -21.17uA   -9.843uA
466mV     -927.4uA   -911uA     -773.6uA
602mV     -4.341mA   -4.574mA   -3.886mA
738mV     -9.474mA   -10.43mA   -8.429mA
976mV     -20.15mA   -22.77mA   -17.76mA
1.35V     -38.63mA   -44.04mA   -34.05mA
1.452V    -42.01mA   -48.04mA   -38mA
1.554V    -42.45mA   -49.35mA   -39mA
1.928V    -40.84mA   -48.83mA   -35.77mA
2.064V    -40.44mA   -48.15mA   -35.29mA
2.2V      -40mA      -46.05mA   -34.84mA
[GND_clamp]
|Voltage   I(typ)   I(min)   I(max)
-1.1V     -92.78mA   -80.14mA   -109.5mA
-1.031V   -81.73mA   -68.77mA   -97.17mA
-939mV    -68.18mA   -56.07mA   -81.64mA
-801mV    -48.85mA   -39.25mA   -59.15mA
-663mV    -30.71mA   -23.84mA   -37.89mA
-571mV    -19.76mA   -14.75mA   -24.85mA
-479mV    -10.5mA    -7.415mA   -13.5mA
-410mV    -5.313mA   -3.546mA   -6.916mA
-341mV    -2.007mA   -1.262mA   -2.59mA
-272mV    -506.9uA   -323.5uA   -609.8uA
-180mV    -45.65uA   -36.06uA   -43.55uA
1.1V      0A         0A         0A
[POWER_clamp]
|Voltage   I(typ)   I(min)   I(max)
-1.1V     5.691mA    8.066mA    3.44mA
-1.062V   3.709mA    5.665mA    2.092mA
-1.039V   2.781mA    4.457mA    1.546mA
-1.016V   2.086mA    3.48mA     1.193mA
-993mV    1.578mA    2.707mA    966.5uA
-970mV    1.21mA     2.107mA    818.5uA
-924mV    750.8uA    1.296mA    641.3uA
-878mV    507uA      821.4uA    530.2uA
-809mV    327.4uA    430uA      403.3uA
-694mV    178.4uA    161uA      233uA
-464mV    19.89uA    15.19uA    23.61uA
1.1V      0A         0A         0A
[Ramp]
| variable   typ   min   max
dV/dt_r   0.239/26.699p   0.230/33.175p   0.257/21.866p
dV/dt_f   0.351/41.147p   0.331/52.719p   0.366/33.664p
R_load = 50.000
[Rising Waveform]
R_fixture= 50.000
V_fixture= 1.100
V_fixture_min= 1.060
V_fixture_max= 1.170
|time   V(typ)   V(min)   V(max)
0s        514.4mV    508.1mV    560.3mV
147ps     515.1mV    508.7mV    564.9mV
204ps     519.5mV    508.1mV    927.4mV
270ps     897.5mV    494.9mV    1.103V
289ps     957.3mV    554.3mV    1.119V
336ps     1.043V     833.6mV    1.146V
377ps     1.073V     951.5mV    1.16V
463ps     1.091V     1.039V     1.168V
667ps     1.1V       1.058V     1.17V
3ns       1.1V       1.06V      1.17V
[Rising Waveform]
R_fixture= 50.000
V_fixture= 0.0
V_fixture_min= 0.0
V_fixture_max= 0.0
|time   V(typ)   V(min)   V(max)
0s        2.608uV    4.994uV    616.3nV
150ps     -51.96uV   44.06uV    8.502mV
196ps     1.456mV    10.68uV    421.1mV
223ps     39.9mV     116.3uV    488.2mV
262ps     358.1mV    713.6uV    511.2mV
300ps     437mV      27.6mV     440.6mV
340ps     450.7mV    290.7mV    428.7mV
367ps     456.8mV    380.3mV    428.3mV
486ps     398.9mV    422.4mV    428.3mV
3ns       398.9mV    382.6mV    428.3mV
[Falling Waveform]
R_fixture= 50.000
V_fixture= 1.100
V_fixture_min= 1.060
V_fixture_max= 1.170
|time   V(typ)   V(min)   V(max)
0s        1.1V       1.06V      1.17V
158ps     1.1V       1.06V      1.165V
225ps     1.088V     1.06V      567.4mV
274ps     692mV      1.058V     453.9mV
315ps     497mV      1.043V     521mV
348ps     449.5mV    874.6mV    544.6mV
411ps     479.3mV    538.1mV    557.2mV
492ps     510.7mV    442.9mV    559.9mV
685ps     514.4mV    506.9mV    560.3mV
3ns       514.4mV    508.1mV    560.3mV
[Falling Waveform]
R_fixture= 50.000
V_fixture= 0.0
V_fixture_min= 0.0
V_fixture_max= 0.0
|time   V(typ)   V(min)   V(max)
0s        398.9mV    382.6mV    428.3mV
145ps     398.2mV    381.9mV    439.3mV
182ps     416.4mV    381.2mV    140.4mV
198ps     415.3mV    382.7mV    62.99mV
218ps     332.3mV    389.8mV    24.32mV
253ps     87.41mV    409.3mV    5.19mV
291ps     17.84mV    298.7mV    -4.692mV
348ps     2.41mV     57.61mV    -526.7uV
434ps     -1.362mV   3.324mV    -12.04uV
3ns       2.472uV    4.845uV    446.3nV
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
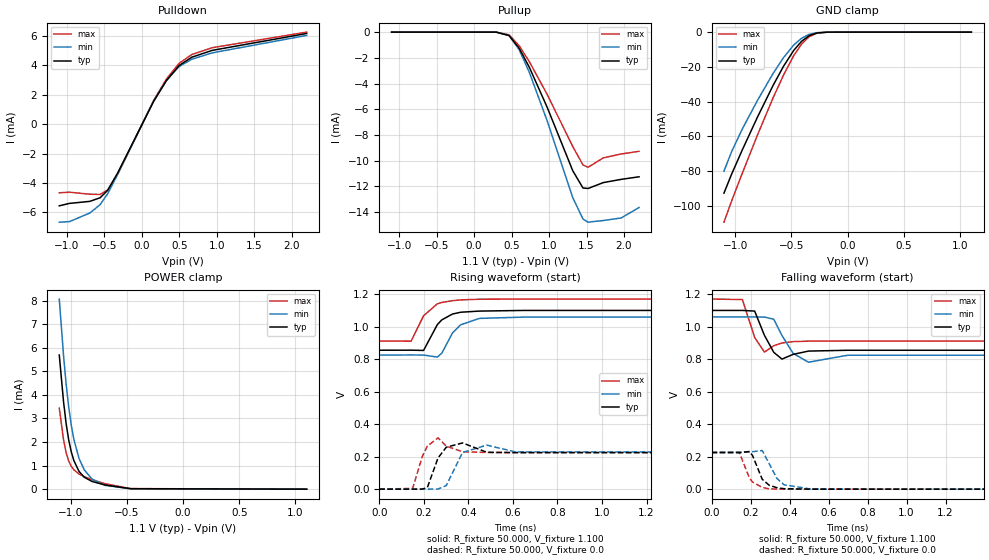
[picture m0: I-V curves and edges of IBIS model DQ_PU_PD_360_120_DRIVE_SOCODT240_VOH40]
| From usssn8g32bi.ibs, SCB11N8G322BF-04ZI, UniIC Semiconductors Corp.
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|   Model DQ_PU_PD_360_120_DRIVE_SOCODT240_VOH40
[Model] DQ_PU_PD_360_120_DRIVE_SOCODT240_VOH40
Model_type I/O
Polarity   Inverting
Vinl =  0.135V
Vinh =  0.305V
Vmeas =  0.220V
Rref =  50.000
Vref =  0.220V
C_comp   1.020pF   1.010pF   1.030pF
[Model Spec]
Vinh   0.305V   0.297V   0.319V
Vinl   0.135V   0.127V   0.149V
Vmeas   0.220V   0.212V   0.234V
Vref   0.220V   0.212V   0.234V
Rref   50.000   NA   NA
[Temperature Range]   25.000   85.000   -40.000
[Voltage Range]   1.100V   1.060V   1.170V
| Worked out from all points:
|   slope of the pulldown table from 0 to 0.165 V, typ, clamps not added: 102 ohm
|   GND clamp passes 1 mA (typ) near -0.30 V on its own axis
|   POWER clamp passes 1 mA (typ) near -0.95 V on its own axis
|   rising waveform, R_fixture 50.000, V_fixture 1.100: 20-80 % time 70.2ps typ, 72.8ps min, 69ps max; typ from 0.855 V to 1.1 V
|   rising waveform, R_fixture 50.000, V_fixture 0.0: 20-80 % time 32.1ps typ, 41ps min, 25.5ps max; typ from 0 V to 0.225 V
|   falling waveform, R_fixture 50.000, V_fixture 1.100: 20-80 % time 46.1ps typ, 58.5ps min, 37ps max; typ from 1.1 V to 0.855 V
|   falling waveform, R_fixture 50.000, V_fixture 0.0: 20-80 % time 52.5ps typ, 63.8ps min, 49.8ps max; typ from 0.225 V to 0 V
[Pulldown]
|Voltage   I(typ)   I(min)   I(max)
-1.1V     -5.559mA   -6.673mA   -4.673mA
-964mV    -5.394mA   -6.634mA   -4.631mA
-692mV    -5.255mA   -6.046mA   -4.769mA
-556mV    -5.011mA   -5.482mA   -4.784mA
-454mV    -4.503mA   -4.733mA   -4.479mA
-318mV    -3.293mA   -3.384mA   -3.363mA
158mV     1.547mA    1.562mA    1.602mA
328mV     2.959mA    2.962mA    3.064mA
498mV     3.986mA    3.92mA     4.137mA
668mV     4.555mA    4.415mA    4.737mA
940mV     5.019mA    4.85mA     5.2mA
2.2V      6.168mA    6.037mA    6.263mA
[Pullup]
|Voltage   I(typ)   I(min)   I(max)
-1.1V     900pA      4.512nA    0A
296mV     -5.16uA    -6.193uA   -2.645uA
466mV     -269.4uA   -269uA     -210.8uA
602mV     -1.26mA    -1.371mA   -1.066mA
738mV     -2.752mA   -3.15mA    -2.312mA
976mV     -5.863mA   -6.919mA   -4.864mA
1.316V    -10.78mA   -12.87mA   -8.894mA
1.452V    -12.12mA   -14.53mA   -10.33mA
1.52V     -12.16mA   -14.78mA   -10.51mA
1.724V    -11.7mA    -14.65mA   -9.778mA
1.962V    -11.45mA   -14.45mA   -9.476mA
2.2V      -11.25mA   -13.64mA   -9.27mA
[GND_clamp]
|Voltage   I(typ)   I(min)   I(max)
-1.1V     -92.78mA   -80.14mA   -109.5mA
-1.031V   -81.73mA   -68.77mA   -97.17mA
-939mV    -68.18mA   -56.07mA   -81.64mA
-801mV    -48.85mA   -39.25mA   -59.15mA
-663mV    -30.71mA   -23.84mA   -37.89mA
-571mV    -19.76mA   -14.75mA   -24.85mA
-479mV    -10.5mA    -7.415mA   -13.5mA
-410mV    -5.313mA   -3.546mA   -6.916mA
-341mV    -2.007mA   -1.262mA   -2.59mA
-272mV    -506.9uA   -323.5uA   -609.8uA
-180mV    -45.65uA   -36.06uA   -43.55uA
1.1V      0A         0A         0A
[POWER_clamp]
|Voltage   I(typ)   I(min)   I(max)
-1.1V     5.691mA    8.066mA    3.44mA
-1.062V   3.709mA    5.665mA    2.092mA
-1.039V   2.781mA    4.457mA    1.546mA
-1.016V   2.086mA    3.48mA     1.193mA
-993mV    1.578mA    2.707mA    966.5uA
-970mV    1.21mA     2.107mA    818.5uA
-924mV    750.8uA    1.296mA    641.3uA
-878mV    507uA      821.4uA    530.2uA
-809mV    327.4uA    430uA      403.3uA
-694mV    178.4uA    161uA      233uA
-464mV    19.89uA    15.19uA    23.61uA
1.1V      0A         0A         0A
[Ramp]
| variable   typ   min   max
dV/dt_r   0.135/32.169p   0.137/41.051p   0.135/25.664p
dV/dt_f   0.147/46.132p   0.141/58.502p   0.155/37.105p
R_load = 50.000
[Rising Waveform]
R_fixture= 50.000
V_fixture= 1.100
V_fixture_min= 1.060
V_fixture_max= 1.170
|time   V(typ)   V(min)   V(max)
0s        855mV      825.4mV    911.8mV
143ps     855.5mV    825.8mV    910.7mV
199ps     853.8mV    825.6mV    1.067V
261ps     1.013V     813mV      1.141V
281ps     1.042V     836.9mV    1.149V
329ps     1.078V     961.4mV    1.16V
366ps     1.089V     1.012V     1.165V
450ps     1.096V     1.051V     1.169V
650ps     1.1V       1.059V     1.17V
3ns       1.1V       1.06V      1.17V
[Rising Waveform]
R_fixture= 50.000
V_fixture= 0.0
V_fixture_min= 0.0
V_fixture_max= 0.0
|time   V(typ)   V(min)   V(max)
0s        4.316uV    8.22uV     1.011uV
150ps     -33.57uV   36.53uV    4.76mV
193ps     595.7uV    11.09uV    200mV
216ps     9.941mV    12.12uV    265.4mV
264ps     192.2mV    607.9uV    315.3mV
301ps     258mV      22.39mV    264.5mV
374ps     284.5mV    226mV      230.4mV
483ps     227mV      271mV      225.7mV
611ps     224.8mV    229.4mV    225.5mV
3ns       224.7mV    228.3mV    225.5mV
[Falling Waveform]
R_fixture= 50.000
V_fixture= 1.100
V_fixture_min= 1.060
V_fixture_max= 1.170
|time   V(typ)   V(min)   V(max)
0s        1.1V       1.06V      1.17V
158ps     1.1V       1.06V      1.167V
221ps     1.096V     1.06V      934.2mV
271ps     947.2mV    1.059V     843.7mV
319ps     842.2mV    1.046V     883.2mV
361ps     800.6mV    946.2mV    899.6mV
418ps     829.4mV    835.9mV    908mV
497ps     849.8mV    781.3mV    911mV
698ps     854.9mV    824.3mV    911.8mV
3ns       855mV      825.4mV    911.8mV
[Falling Waveform]
R_fixture= 50.000
V_fixture= 0.0
V_fixture_min= 0.0
V_fixture_max= 0.0
|time   V(typ)   V(min)   V(max)
0s        224.7mV    228.3mV    225.5mV
141ps     224.3mV    228.1mV    229.2mV
194ps     231.9mV    228.2mV    69.16mV
210ps     207.3mV    230.6mV    44.06mV
260ps     60.68mV    237.9mV    10.71mV
295ps     24.44mV    157.9mV    1.986mV
335ps     8.945mV    66.29mV    696.8uV
372ps     2.795mV    26.97mV    274.2uV
511ps     17.58uV    372.8uV    8.408uV
3ns       4.212uV    8.128uV    1.054uV
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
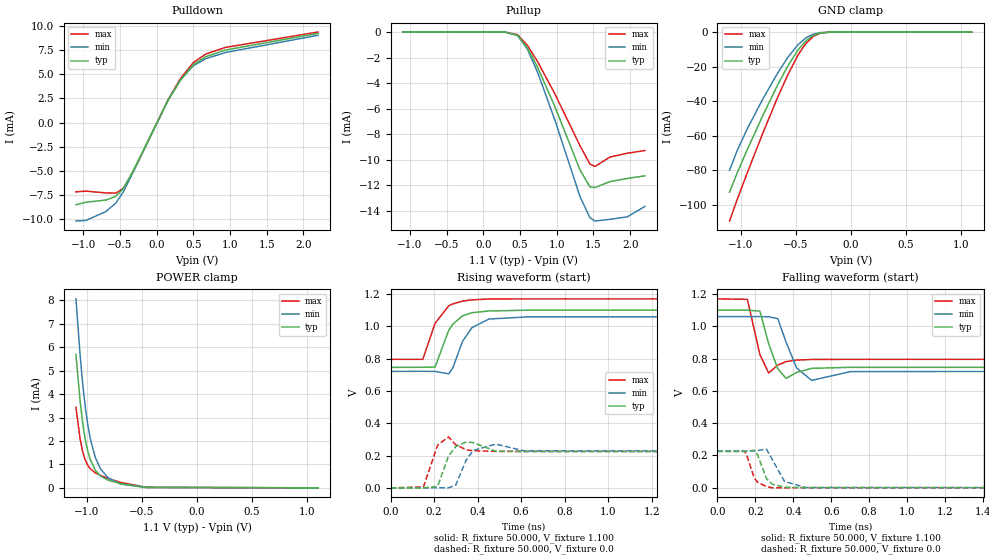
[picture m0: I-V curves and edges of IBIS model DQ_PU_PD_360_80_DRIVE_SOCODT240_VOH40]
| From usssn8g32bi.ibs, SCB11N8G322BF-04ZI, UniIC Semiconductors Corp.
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|   Model DQ_PU_PD_360_80_DRIVE_SOCODT240_VOH40
[Model] DQ_PU_PD_360_80_DRIVE_SOCODT240_VOH40
Model_type I/O
Polarity   Inverting
Vinl =  0.135V
Vinh =  0.305V
Vmeas =  0.220V
Rref =  50.000
Vref =  0.220V
C_comp   1.020pF   1.010pF   1.030pF
[Model Spec]
Vinh   0.305V   0.297V   0.319V
Vinl   0.135V   0.127V   0.149V
Vmeas   0.220V   0.212V   0.234V
Vref   0.220V   0.212V   0.234V
Rref   50.000   NA   NA
[Temperature Range]   25.000   85.000   -40.000
[Voltage Range]   1.100V   1.060V   1.170V
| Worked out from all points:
|   slope of the pulldown table from 0 to 0.165 V, typ, clamps not added: 68.2 ohm
|   GND clamp passes 1 mA (typ) near -0.30 V on its own axis
|   POWER clamp passes 1 mA (typ) near -0.95 V on its own axis
|   rising waveform, R_fixture 50.000, V_fixture 1.100: 20-80 % time 72.4ps typ, 75.4ps min, 70.6ps max; typ from 0.746 V to 1.1 V
|   rising waveform, R_fixture 50.000, V_fixture 0.0: 20-80 % time 32.1ps typ, 40.9ps min, 25.8ps max; typ from 0 V to 0.225 V
|   falling waveform, R_fixture 50.000, V_fixture 1.100: 20-80 % time 45.6ps typ, 58ps min, 37.1ps max; typ from 1.1 V to 0.746 V
|   falling waveform, R_fixture 50.000, V_fixture 0.0: 20-80 % time 46.5ps typ, 60.9ps min, 43.6ps max; typ from 0.225 V to 0 V
[Pulldown]
|Voltage   I(typ)   I(min)   I(max)
-1.1V     -8.531mA   -10.21mA   -7.187mA
-964mV    -8.264mA   -10.15mA   -7.109mA
-692mV    -8.033mA   -9.227mA   -7.298mA
-556mV    -7.649mA   -8.349mA   -7.316mA
-454mV    -6.852mA   -7.181mA   -6.833mA
-318mV    -4.969mA   -5.097mA   -5.081mA
158mV     2.325mA    2.347mA    2.407mA
328mV     4.444mA    4.448mA    4.602mA
498mV     5.984mA    5.884mA    6.211mA
668mV     6.835mA    6.624mA    7.108mA
940mV     7.53mA     7.275mA    7.801mA
2.2V      9.253mA    9.055mA    9.394mA
[Pullup]
|Voltage   I(typ)   I(min)   I(max)
-1.1V     900pA      4.512nA    0A
296mV     -5.16uA    -6.193uA   -2.645uA
466mV     -269.4uA   -269uA     -210.8uA
602mV     -1.26mA    -1.371mA   -1.066mA
738mV     -2.752mA   -3.15mA    -2.312mA
976mV     -5.863mA   -6.919mA   -4.864mA
1.316V    -10.78mA   -12.87mA   -8.894mA
1.452V    -12.12mA   -14.53mA   -10.33mA
1.52V     -12.16mA   -14.78mA   -10.51mA
1.724V    -11.7mA    -14.65mA   -9.778mA
1.962V    -11.45mA   -14.45mA   -9.476mA
2.2V      -11.25mA   -13.64mA   -9.27mA
[GND_clamp]
|Voltage   I(typ)   I(min)   I(max)
-1.1V     -92.78mA   -80.14mA   -109.5mA
-1.031V   -81.73mA   -68.77mA   -97.17mA
-939mV    -68.18mA   -56.07mA   -81.64mA
-801mV    -48.85mA   -39.25mA   -59.15mA
-663mV    -30.71mA   -23.84mA   -37.89mA
-571mV    -19.76mA   -14.75mA   -24.85mA
-479mV    -10.5mA    -7.415mA   -13.5mA
-410mV    -5.313mA   -3.546mA   -6.916mA
-341mV    -2.007mA   -1.262mA   -2.59mA
-272mV    -506.9uA   -323.5uA   -609.8uA
-180mV    -45.65uA   -36.06uA   -43.55uA
1.1V      0A         0A         0A
[POWER_clamp]
|Voltage   I(typ)   I(min)   I(max)
-1.1V     5.691mA    8.066mA    3.44mA
-1.062V   3.709mA    5.665mA    2.092mA
-1.039V   2.781mA    4.457mA    1.546mA
-1.016V   2.086mA    3.48mA     1.193mA
-993mV    1.578mA    2.707mA    966.5uA
-970mV    1.21mA     2.107mA    818.5uA
-924mV    750.8uA    1.296mA    641.3uA
-878mV    507uA      821.4uA    530.2uA
-809mV    327.4uA    430uA      403.3uA
-694mV    178.4uA    161uA      233uA
-464mV    19.89uA    15.19uA    23.61uA
1.1V      0A         0A         0A
[Ramp]
| variable   typ   min   max
dV/dt_r   0.135/32.213p   0.137/41.014p   0.135/25.881p
dV/dt_f   0.212/45.696p   0.203/58.022p   0.225/37.254p
R_load = 50.000
[Rising Waveform]
R_fixture= 50.000
V_fixture= 1.100
V_fixture_min= 1.060
V_fixture_max= 1.170
|time   V(typ)   V(min)   V(max)
0s        746mV      721mV      795.6mV
148ps     746.6mV    721.5mV    795.8mV
204ps     747.4mV    720.9mV    1.018V
267ps     974.6mV    706.2mV    1.127V
286ps     1.014V     742.2mV    1.139V
330ps     1.064V     905.7mV    1.156V
373ps     1.084V     991mV      1.164V
452ps     1.095V     1.045V     1.169V
636ps     1.1V       1.059V     1.17V
3ns       1.1V       1.06V      1.17V
[Rising Waveform]
R_fixture= 50.000
V_fixture= 0.0
V_fixture_min= 0.0
V_fixture_max= 0.0
|time   V(typ)   V(min)   V(max)
0s        3.688uV    7.016uV    861.5nV
151ps     -5.239uV   22.91uV    5.857mV
216ps     8.79mV     117.5uV    264.2mV
266ps     196.7mV    620.6uV    315.4mV
299ps     255.6mV    16.1mV     267.1mV
347ps     283.5mV    171.7mV    235.8mV
379ps     280.2mV    231.3mV    229.7mV
483ps     227mV      271mV      225.7mV
612ps     224.8mV    229.4mV    225.5mV
3ns       224.7mV    228.3mV    225.5mV
[Falling Waveform]
R_fixture= 50.000
V_fixture= 1.100
V_fixture_min= 1.060
V_fixture_max= 1.170
|time   V(typ)   V(min)   V(max)
0s        1.1V       1.06V      1.17V
158ps     1.1V       1.06V      1.167V
224ps     1.094V     1.06V      825mV
270ps     892.7mV    1.059V     710.9mV
318ps     736.8mV    1.048V     760mV
362ps     677.5mV    901.6mV    781.2mV
418ps     714.5mV    741.6mV    790.9mV
497ps     739.7mV    665mV      794.6mV
702ps     745.9mV    719.6mV    795.5mV
3ns       746mV      721mV      795.6mV
[Falling Waveform]
R_fixture= 50.000
V_fixture= 0.0
V_fixture_min= 0.0
V_fixture_max= 0.0
|time   V(typ)   V(min)   V(max)
0s        224.7mV    228.3mV    225.5mV
141ps     224.3mV    228.1mV    229.5mV
154ps     225.5mV    227.9mV    203.2mV
194ps     232.1mV    228.2mV    61.19mV
211ps     206mV      230.7mV    34.77mV
259ps     55.72mV    238.5mV    7.009mV
291ps     21.19mV    170.9mV    -693.3uV
354ps     3.425mV    38.35mV    -129.1uV
464ps     -225uV     2.327mV    -2.933uV
3ns       914nV      6.813uV    536.4nV
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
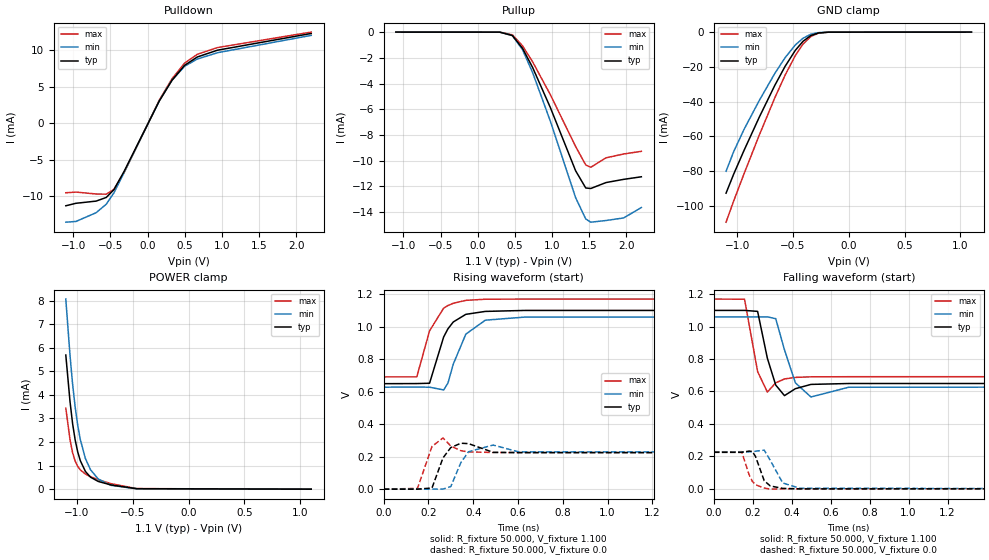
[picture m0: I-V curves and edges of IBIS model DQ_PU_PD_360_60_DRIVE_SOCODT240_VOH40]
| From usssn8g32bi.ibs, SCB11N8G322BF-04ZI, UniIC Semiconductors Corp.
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|   Model DQ_PU_PD_360_60_DRIVE_SOCODT240_VOH40
[Model] DQ_PU_PD_360_60_DRIVE_SOCODT240_VOH40
Model_type I/O
Polarity   Inverting
Vinl =  0.135V
Vinh =  0.305V
Vmeas =  0.220V
Rref =  50.000
Vref =  0.220V
C_comp   1.020pF   1.010pF   1.030pF
[Model Spec]
Vinh   0.305V   0.297V   0.319V
Vinl   0.135V   0.127V   0.149V
Vmeas   0.220V   0.212V   0.234V
Vref   0.220V   0.212V   0.234V
Rref   50.000   NA   NA
[Temperature Range]   25.000   85.000   -40.000
[Voltage Range]   1.100V   1.060V   1.170V
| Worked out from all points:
|   slope of the pulldown table from 0 to 0.165 V, typ, clamps not added: 51.2 ohm
|   GND clamp passes 1 mA (typ) near -0.30 V on its own axis
|   POWER clamp passes 1 mA (typ) near -0.95 V on its own axis
|   rising waveform, R_fixture 50.000, V_fixture 1.100: 20-80 % time 74.1ps typ, 77.4ps min, 72.1ps max; typ from 0.649 V to 1.1 V
|   rising waveform, R_fixture 50.000, V_fixture 0.0: 20-80 % time 32ps typ, 40.7ps min, 25.8ps max; typ from 0 V to 0.225 V
|   falling waveform, R_fixture 50.000, V_fixture 1.100: 20-80 % time 44.5ps typ, 56.8ps min, 36.5ps max; typ from 1.1 V to 0.649 V
|   falling waveform, R_fixture 50.000, V_fixture 0.0: 20-80 % time 41.6ps typ, 58.8ps min, 38.4ps max; typ from 0.225 V to 0 V
[Pulldown]
|Voltage   I(typ)   I(min)   I(max)
-1.1V     -11.28mA   -13.53mA   -9.498mA
-964mV    -10.94mA   -13.43mA   -9.404mA
-692mV    -10.64mA   -12.23mA   -9.666mA
-556mV    -10.14mA   -11.07mA   -9.692mA
-454mV    -9.086mA   -9.529mA   -9.054mA
-318mV    -6.606mA   -6.779mA   -6.751mA
158mV     3.095mA    3.124mA    3.205mA
328mV     5.919mA    5.923mA    6.128mA
498mV     7.971mA    7.839mA    8.274mA
668mV     9.107mA    8.827mA    9.472mA
940mV     10.04mA    9.694mA    10.4mA
2.2V      12.33mA    12.07mA    12.52mA
[Pullup]
|Voltage   I(typ)   I(min)   I(max)
-1.1V     900pA      4.512nA    0A
296mV     -5.16uA    -6.193uA   -2.645uA
466mV     -269.4uA   -269uA     -210.8uA
602mV     -1.26mA    -1.371mA   -1.066mA
738mV     -2.752mA   -3.15mA    -2.312mA
976mV     -5.863mA   -6.919mA   -4.864mA
1.316V    -10.78mA   -12.87mA   -8.894mA
1.452V    -12.12mA   -14.53mA   -10.33mA
1.52V     -12.16mA   -14.78mA   -10.51mA
1.724V    -11.7mA    -14.65mA   -9.778mA
1.962V    -11.45mA   -14.45mA   -9.476mA
2.2V      -11.25mA   -13.64mA   -9.27mA
[GND_clamp]
|Voltage   I(typ)   I(min)   I(max)
-1.1V     -92.78mA   -80.14mA   -109.5mA
-1.031V   -81.73mA   -68.77mA   -97.17mA
-939mV    -68.18mA   -56.07mA   -81.64mA
-801mV    -48.85mA   -39.25mA   -59.15mA
-663mV    -30.71mA   -23.84mA   -37.89mA
-571mV    -19.76mA   -14.75mA   -24.85mA
-479mV    -10.5mA    -7.415mA   -13.5mA
-410mV    -5.313mA   -3.546mA   -6.916mA
-341mV    -2.007mA   -1.262mA   -2.59mA
-272mV    -506.9uA   -323.5uA   -609.8uA
-180mV    -45.65uA   -36.06uA   -43.55uA
1.1V      0A         0A         0A
[POWER_clamp]
|Voltage   I(typ)   I(min)   I(max)
-1.1V     5.691mA    8.066mA    3.44mA
-1.062V   3.709mA    5.665mA    2.092mA
-1.039V   2.781mA    4.457mA    1.546mA
-1.016V   2.086mA    3.48mA     1.193mA
-993mV    1.578mA    2.707mA    966.5uA
-970mV    1.21mA     2.107mA    818.5uA
-924mV    750.8uA    1.296mA    641.3uA
-878mV    507uA      821.4uA    530.2uA
-809mV    327.4uA    430uA      403.3uA
-694mV    178.4uA    161uA      233uA
-464mV    19.89uA    15.19uA    23.61uA
1.1V      0A         0A         0A
[Ramp]
| variable   typ   min   max
dV/dt_r   0.135/32.127p   0.137/40.893p   0.135/25.864p
dV/dt_f   0.270/44.667p   0.259/56.840p   0.287/36.585p
R_load = 50.000
[Rising Waveform]
R_fixture= 50.000
V_fixture= 1.100
V_fixture_min= 1.060
V_fixture_max= 1.170
|time   V(typ)   V(min)   V(max)
0s        649.2mV    627.7mV    691mV
148ps     649.9mV    628.2mV    691.2mV
205ps     651.9mV    627.6mV    974.2mV
268ps     936.5mV    610.5mV    1.114V
287ps     986.4mV    652.1mV    1.13V
311ps     1.029V     769.8mV    1.144V
367ps     1.076V     953.9mV    1.162V
454ps     1.094V     1.04V      1.169V
630ps     1.1V       1.059V     1.17V
3ns       1.1V       1.06V      1.17V
[Rising Waveform]
R_fixture= 50.000
V_fixture= 0.0
V_fixture_min= 0.0
V_fixture_max= 0.0
|time   V(typ)   V(min)   V(max)
0s        3.217uV    6.114uV    749.7nV
151ps     58.15uV    21.74uV    4.849mV
216ps     7.45mV     221.7uV    263.2mV
265ps     192.3mV    493.4uV    314.9mV
300ps     256.2mV    16.09mV    265.6mV
345ps     282.7mV    163.8mV    236.4mV
379ps     280.3mV    230.3mV    229.7mV
489ps     226.7mV    271.6mV    225.7mV
603ps     224.8mV    229.7mV    225.5mV
3ns       224.7mV    228.3mV    225.5mV
[Falling Waveform]
R_fixture= 50.000
V_fixture= 1.100
V_fixture_min= 1.060
V_fixture_max= 1.170
|time   V(typ)   V(min)   V(max)
0s        1.1V       1.06V      1.17V
158ps     1.1V       1.06V      1.169V
225ps     1.094V     1.06V      723mV
275ps     805.5mV    1.06V      596.5mV
318ps     639.5mV    1.049V     653.3mV
363ps     574.3mV    856.5mV    677.2mV
419ps     617.2mV    653mV      686.9mV
499ps     643.6mV    566mV      690.3mV
693ps     649.1mV    626.1mV    691mV
3ns       649.2mV    627.7mV    691.1mV
[Falling Waveform]
R_fixture= 50.000
V_fixture= 0.0
V_fixture_min= 0.0
V_fixture_max= 0.0
|time   V(typ)   V(min)   V(max)
0s        224.7mV    228.3mV    225.5mV
143ps     224.4mV    228mV      228.5mV
182ps     232.3mV    227.6mV    84.29mV
198ps     229.8mV    228.6mV    45.78mV
214ps     199.6mV    231.3mV    24.72mV
259ps     49.41mV    238.4mV    4.49mV
290ps     17.11mV    175.1mV    -2.622mV
354ps     2.245mV    35.49mV    -338.1uV
442ps     -730.8uV   2.897mV    -14.11uV
3ns       -1.388uV   2.84uV     597.8nV
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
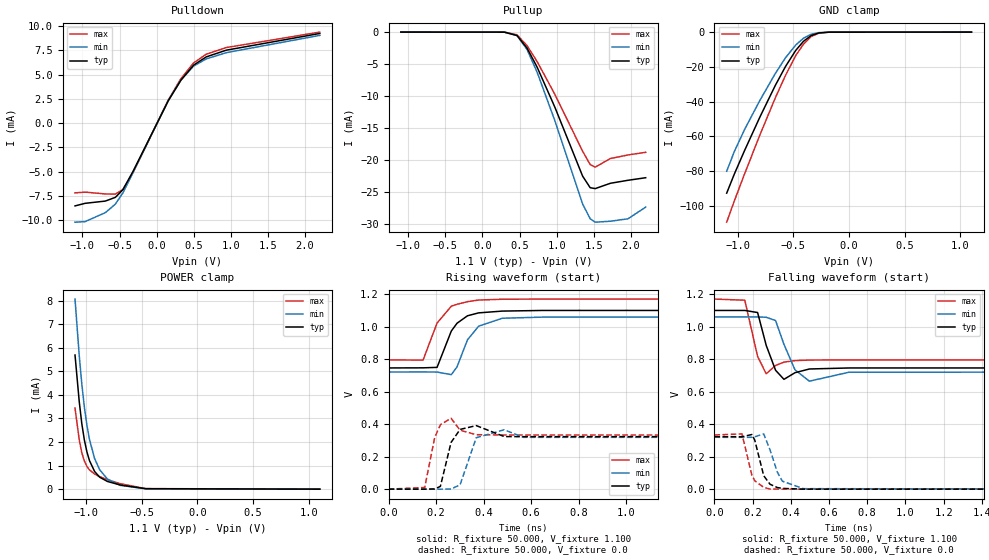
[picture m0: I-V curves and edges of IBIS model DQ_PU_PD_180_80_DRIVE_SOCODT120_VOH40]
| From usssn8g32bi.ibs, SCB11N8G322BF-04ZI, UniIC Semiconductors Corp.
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|   Model DQ_PU_PD_180_80_DRIVE_SOCODT120_VOH40
[Model] DQ_PU_PD_180_80_DRIVE_SOCODT120_VOH40
Model_type I/O
Polarity   Inverting
Vinl =  0.135V
Vinh =  0.305V
Vmeas =  0.220V
Rref =  50.000
Vref =  0.220V
C_comp   1.020pF   1.010pF   1.030pF
[Model Spec]
Vinh   0.305V   0.297V   0.319V
Vinl   0.135V   0.127V   0.149V
Vmeas   0.220V   0.212V   0.234V
Vref   0.220V   0.212V   0.234V
Rref   50.000   NA   NA
[Temperature Range]   25.000   85.000   -40.000
[Voltage Range]   1.100V   1.060V   1.170V
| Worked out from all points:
|   slope of the pulldown table from 0 to 0.165 V, typ, clamps not added: 68.2 ohm
|   GND clamp passes 1 mA (typ) near -0.30 V on its own axis
|   POWER clamp passes 1 mA (typ) near -0.95 V on its own axis
|   rising waveform, R_fixture 50.000, V_fixture 1.100: 20-80 % time 71.1ps typ, 73.2ps min, 70.4ps max; typ from 0.746 V to 1.1 V
|   rising waveform, R_fixture 50.000, V_fixture 0.0: 20-80 % time 28.5ps typ, 36.2ps min, 22.8ps max; typ from 0 V to 0.323 V
|   falling waveform, R_fixture 50.000, V_fixture 1.100: 20-80 % time 46ps typ, 58.8ps min, 37.4ps max; typ from 1.1 V to 0.746 V
|   falling waveform, R_fixture 50.000, V_fixture 0.0: 20-80 % time 45.4ps typ, 58.8ps min, 42.9ps max; typ from 0.323 V to 0 V
[Pulldown]
|Voltage   I(typ)   I(min)   I(max)
-1.1V     -8.531mA   -10.21mA   -7.187mA
-964mV    -8.264mA   -10.15mA   -7.109mA
-692mV    -8.033mA   -9.227mA   -7.298mA
-556mV    -7.649mA   -8.349mA   -7.316mA
-454mV    -6.852mA   -7.181mA   -6.833mA
-318mV    -4.969mA   -5.097mA   -5.081mA
158mV     2.325mA    2.347mA    2.407mA
328mV     4.444mA    4.448mA    4.602mA
498mV     5.984mA    5.884mA    6.211mA
668mV     6.835mA    6.624mA    7.108mA
940mV     7.53mA     7.275mA    7.801mA
2.2V      9.253mA    9.055mA    9.394mA
[Pullup]
|Voltage   I(typ)   I(min)   I(max)
-1.1V     1.8nA      9.024nA    0A
296mV     -10.32uA   -12.39uA   -5.289uA
466mV     -538.9uA   -538.1uA   -421.8uA
602mV     -2.521mA   -2.744mA   -2.134mA
738mV     -5.508mA   -6.307mA   -4.628mA
976mV     -11.74mA   -13.85mA   -9.734mA
1.35V     -22.51mA   -26.87mA   -18.62mA
1.452V    -24.32mA   -29.17mA   -20.7mA
1.52V     -24.46mA   -29.71mA   -21.11mA
1.724V    -23.63mA   -29.56mA   -19.76mA
1.962V    -23.16mA   -29.18mA   -19.2mA
2.2V      -22.76mA   -27.35mA   -18.79mA
[GND_clamp]
|Voltage   I(typ)   I(min)   I(max)
-1.1V     -92.78mA   -80.14mA   -109.5mA
-1.031V   -81.73mA   -68.77mA   -97.17mA
-939mV    -68.18mA   -56.07mA   -81.64mA
-801mV    -48.85mA   -39.25mA   -59.15mA
-663mV    -30.71mA   -23.84mA   -37.89mA
-571mV    -19.76mA   -14.75mA   -24.85mA
-479mV    -10.5mA    -7.415mA   -13.5mA
-410mV    -5.313mA   -3.546mA   -6.916mA
-341mV    -2.007mA   -1.262mA   -2.59mA
-272mV    -506.9uA   -323.5uA   -609.8uA
-180mV    -45.65uA   -36.06uA   -43.55uA
1.1V      0A         0A         0A
[POWER_clamp]
|Voltage   I(typ)   I(min)   I(max)
-1.1V     5.691mA    8.066mA    3.44mA
-1.062V   3.709mA    5.665mA    2.092mA
-1.039V   2.781mA    4.457mA    1.546mA
-1.016V   2.086mA    3.48mA     1.193mA
-993mV    1.578mA    2.707mA    966.5uA
-970mV    1.21mA     2.107mA    818.5uA
-924mV    750.8uA    1.296mA    641.3uA
-878mV    507uA      821.4uA    530.2uA
-809mV    327.4uA    430uA      403.3uA
-694mV    178.4uA    161uA      233uA
-464mV    19.89uA    15.19uA    23.61uA
1.1V      0A         0A         0A
[Ramp]
| variable   typ   min   max
dV/dt_r   0.194/28.665p   0.192/36.231p   0.200/22.975p
dV/dt_f   0.212/46.084p   0.203/58.831p   0.225/37.475p
R_load = 50.000
[Rising Waveform]
R_fixture= 50.000
V_fixture= 1.100
V_fixture_min= 1.060
V_fixture_max= 1.170
|time   V(typ)   V(min)   V(max)
0s        746mV      721mV      795.6mV
145ps     746.7mV    721.4mV    794.2mV
204ps     749.5mV    720.8mV    1.022V
264ps     973.1mV    704.7mV    1.126V
288ps     1.021V     752.2mV    1.138V
332ps     1.067V     918.9mV    1.154V
379ps     1.085V     1.003V     1.164V
479ps     1.096V     1.052V     1.169V
653ps     1.1V       1.059V     1.17V
3ns       1.1V       1.06V      1.17V
[Rising Waveform]
R_fixture= 50.000
V_fixture= 0.0
V_fixture_min= 0.0
V_fixture_max= 0.0
|time   V(typ)   V(min)   V(max)
0s        3.688uV    7.016uV    861.5nV
152ps     -135.1uV   39.51uV    10.12mV
194ps     1.157mV    -24.75uV   318mV
218ps     16.95mV    -69.99uV   396.4mV
263ps     287.6mV    739.4uV    436.4mV
301ps     367.6mV    27.05mV    362.6mV
369ps     391.1mV    316.5mV    335.2mV
487ps     323.5mV    365.5mV    333.3mV
567ps     323.1mV    319mV      333.3mV
3ns       323.1mV    319.3mV    333.3mV
[Falling Waveform]
R_fixture= 50.000
V_fixture= 1.100
V_fixture_min= 1.060
V_fixture_max= 1.170
|time   V(typ)   V(min)   V(max)
0s        1.1V       1.06V      1.17V
159ps     1.1V       1.06V      1.163V
226ps     1.087V     1.06V      816.1mV
271ps     884.9mV    1.058V     710.2mV
320ps     731.8mV    1.038V     761.2mV
364ps     675.9mV    890.9mV    781.7mV
422ps     716.8mV    733.8mV    791.2mV
497ps     739.6mV    664.7mV    794.6mV
705ps     745.9mV    719.7mV    795.5mV
3ns       746mV      721mV      795.6mV
[Falling Waveform]
R_fixture= 50.000
V_fixture= 0.0
V_fixture_min= 0.0
V_fixture_max= 0.0
|time   V(typ)   V(min)   V(max)
0s        323.1mV    319.3mV    333.3mV
144ps     322.4mV    318.8mV    340.1mV
196ps     336.1mV    319mV      85.51mV
211ps     302mV      322.4mV    51.78mV
258ps     82.7mV     339.6mV    10.8mV
291ps     30.08mV    242.2mV    528uV
329ps     10mV       105.4mV    64.13uV
356ps     4.52mV     48.79mV    48.89uV
466ps     -145.3uV   2.91mV     3.303uV
3ns       3.255uV    6.963uV    681nV
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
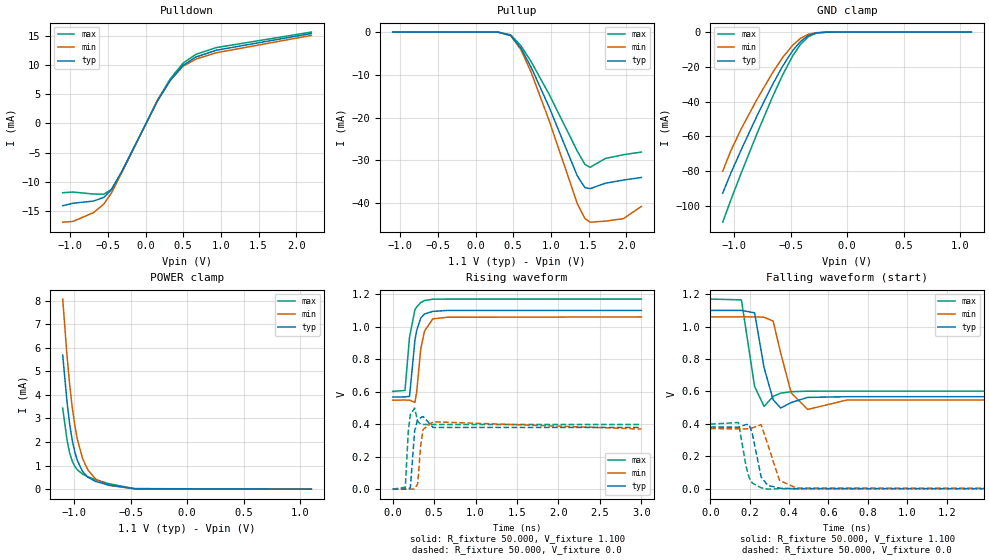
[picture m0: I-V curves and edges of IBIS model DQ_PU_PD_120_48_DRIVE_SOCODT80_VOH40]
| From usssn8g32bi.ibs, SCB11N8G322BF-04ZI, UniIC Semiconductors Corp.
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|   Model DQ_PU_PD_120_48_DRIVE_SOCODT80_VOH40
[Model] DQ_PU_PD_120_48_DRIVE_SOCODT80_VOH40
Model_type I/O
Polarity   Inverting
Vinl =  0.135V
Vinh =  0.305V
Vmeas =  0.220V
Rref =  50.000
Vref =  0.220V
C_comp   1.020pF   1.010pF   1.030pF
[Model Spec]
Vinh   0.305V   0.297V   0.319V
Vinl   0.135V   0.127V   0.149V
Vmeas   0.220V   0.212V   0.234V
Vref   0.220V   0.212V   0.234V
Rref   50.000   NA   NA
[Temperature Range]   25.000   85.000   -40.000
[Voltage Range]   1.100V   1.060V   1.170V
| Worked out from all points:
|   slope of the pulldown table from 0 to 0.165 V, typ, clamps not added: 41 ohm
|   GND clamp passes 1 mA (typ) near -0.30 V on its own axis
|   POWER clamp passes 1 mA (typ) near -0.95 V on its own axis
|   rising waveform, R_fixture 50.000, V_fixture 1.100: 20-80 % time 73.8ps typ, 76.2ps min, 72.8ps max; typ from 0.567 V to 1.1 V
|   rising waveform, R_fixture 50.000, V_fixture 0.0: 20-80 % time 26.3ps typ, 34ps min, 21.1ps max; typ from 0 V to 0.38 V
|   falling waveform, R_fixture 50.000, V_fixture 1.100: 20-80 % time 43.6ps typ, 56ps min, 35.8ps max; typ from 1.1 V to 0.567 V
|   falling waveform, R_fixture 50.000, V_fixture 0.0: 20-80 % time 37.2ps typ, 54.1ps min, 34.1ps max; typ from 0.38 V to 0 V
[Pulldown]
|Voltage   I(typ)   I(min)   I(max)
-1.1V     -14.07mA   -16.89mA   -11.85mA
-964mV    -13.65mA   -16.76mA   -11.73mA
-692mV    -13.28mA   -15.26mA   -12.07mA
-556mV    -12.65mA   -13.81mA   -12.1mA
-454mV    -11.34mA   -11.89mA   -11.29mA
-318mV    -8.242mA   -8.458mA   -8.422mA
158mV     3.863mA    3.899mA    4mA
328mV     7.389mA    7.394mA    7.65mA
498mV     9.955mA    9.787mA    10.33mA
668mV     11.38mA    11.02mA    11.83mA
940mV     12.54mA    12.11mA    12.99mA
2.2V      15.4mA     15.07mA    15.64mA
[Pullup]
|Voltage   I(typ)   I(min)   I(max)
-1.1V     2.7nA      13.54nA    0A
296mV     -15.48uA   -18.58uA   -7.934uA
466mV     -807.4uA   -806.2uA   -632uA
602mV     -3.772mA   -4.103mA   -3.194mA
738mV     -8.234mA   -9.422mA   -6.922mA
976mV     -17.54mA   -20.68mA   -14.55mA
1.35V     -33.63mA   -40.11mA   -27.84mA
1.452V    -36.39mA   -43.62mA   -30.97mA
1.52V     -36.62mA   -44.46mA   -31.62mA
1.724V    -35.34mA   -44.21mA   -29.55mA
1.962V    -34.61mA   -43.64mA   -28.68mA
2.2V      -34.01mA   -40.78mA   -28.06mA
[GND_clamp]
|Voltage   I(typ)   I(min)   I(max)
-1.1V     -92.78mA   -80.14mA   -109.5mA
-1.031V   -81.73mA   -68.77mA   -97.17mA
-939mV    -68.18mA   -56.07mA   -81.64mA
-801mV    -48.85mA   -39.25mA   -59.15mA
-663mV    -30.71mA   -23.84mA   -37.89mA
-571mV    -19.76mA   -14.75mA   -24.85mA
-479mV    -10.5mA    -7.415mA   -13.5mA
-410mV    -5.313mA   -3.546mA   -6.916mA
-341mV    -2.007mA   -1.262mA   -2.59mA
-272mV    -506.9uA   -323.5uA   -609.8uA
-180mV    -45.65uA   -36.06uA   -43.55uA
1.1V      0A         0A         0A
[POWER_clamp]
|Voltage   I(typ)   I(min)   I(max)
-1.1V     5.691mA    8.066mA    3.44mA
-1.062V   3.709mA    5.665mA    2.092mA
-1.039V   2.781mA    4.457mA    1.546mA
-1.016V   2.086mA    3.48mA     1.193mA
-993mV    1.578mA    2.707mA    966.5uA
-970mV    1.21mA     2.107mA    818.5uA
-924mV    750.8uA    1.296mA    641.3uA
-878mV    507uA      821.4uA    530.2uA
-809mV    327.4uA    430uA      403.3uA
-694mV    178.4uA    161uA      233uA
-464mV    19.89uA    15.19uA    23.61uA
1.1V      0A         0A         0A
[Ramp]
| variable   typ   min   max
dV/dt_r   0.228/26.451p   0.222/34.103p   0.239/21.350p
dV/dt_f   0.320/43.568p   0.307/56.072p   0.341/35.868p
R_load = 50.000
[Rising Waveform]
R_fixture= 50.000
V_fixture= 1.100
V_fixture_min= 1.060
V_fixture_max= 1.170
|time   V(typ)   V(min)   V(max)
0s        567.3mV    547.9mV    601.6mV
148ps     567.8mV    548.5mV    607.5mV
203ps     571.1mV    547.9mV    935.8mV
268ps     916.3mV    533.9mV    1.105V
290ps     978.4mV    601.6mV    1.122V
338ps     1.053V     861.3mV    1.148V
383ps     1.078V     972.6mV    1.161V
483ps     1.094V     1.048V     1.169V
660ps     1.1V       1.058V     1.17V
3ns       1.1V       1.06V      1.17V
[Rising Waveform]
R_fixture= 50.000
V_fixture= 0.0
V_fixture_min= 0.0
V_fixture_max= 0.0
|time   V(typ)   V(min)   V(max)
0s        2.854uV    5.421uV    664.1nV
152ps     -117.5uV   49.1uV     11.68mV
188ps     391.7uV    37.93uV    354.2mV
213ps     9.261mV    -16.2uV    459.2mV
265ps     360mV      1.05mV     499mV
301ps     426.5mV    32.48mV    417.1mV
338ps     439.8mV    269.1mV    399.8mV
366ps     447.5mV    366.5mV    398.3mV
486ps     379.9mV    414.6mV    397.7mV
3ns       379.9mV    370mV      397.7mV
[Falling Waveform]
R_fixture= 50.000
V_fixture= 1.100
V_fixture_min= 1.060
V_fixture_max= 1.170
|time   V(typ)   V(min)   V(max)
0s        1.1V       1.06V      1.17V
158ps     1.1V       1.06V      1.165V
225ps     1.085V     1.06V      630.4mV
273ps     746.4mV    1.058V     507.4mV
319ps     549mV      1.034V     569mV
357ps     497.3mV    838.8mV    589.3mV
411ps     531.4mV    589.7mV    598.3mV
494ps     562.9mV    488.4mV    601.2mV
694ps     567.3mV    546.9mV    601.6mV
3ns       567.3mV    547.9mV    601.6mV
[Falling Waveform]
R_fixture= 50.000
V_fixture= 0.0
V_fixture_min= 0.0
V_fixture_max= 0.0
|time   V(typ)   V(min)   V(max)
0s        379.9mV    370mV      397.7mV
143ps     379mV      369.4mV    408mV
182ps     395.7mV    368.6mV    134.6mV
197ps     395.1mV    369.9mV    69.2mV
213ps     341.7mV    374.9mV    34.49mV
258ps     71.95mV    395mV      5.158mV
292ps     19.54mV    271.8mV    -3.544mV
351ps     2.663mV    51.32mV    -388.1uV
436ps     -1.037mV   3.631mV    -11.94uV
3ns       1.356uV    4.979uV    363.5nV
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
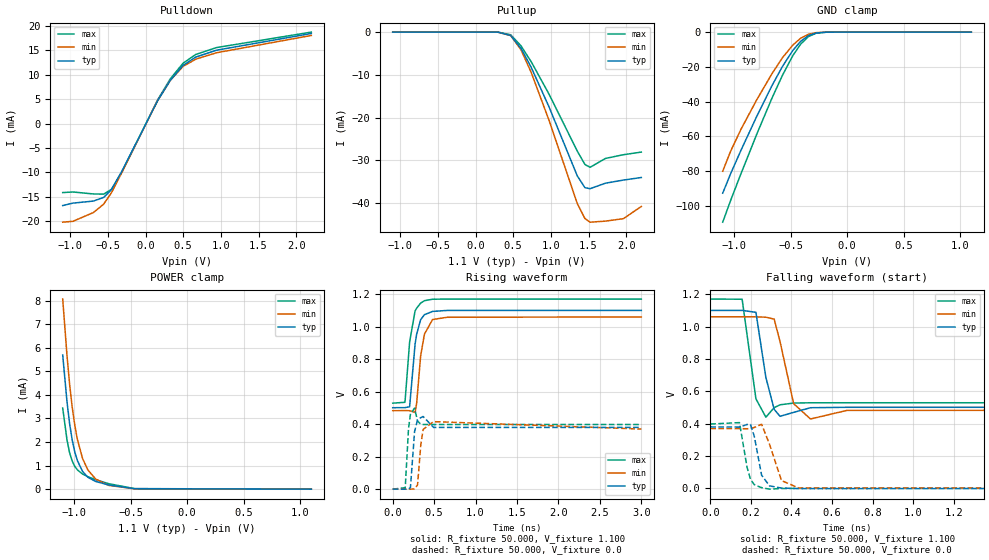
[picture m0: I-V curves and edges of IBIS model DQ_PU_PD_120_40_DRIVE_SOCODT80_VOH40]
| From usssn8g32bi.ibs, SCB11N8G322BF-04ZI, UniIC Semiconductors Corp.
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|   Model DQ_PU_PD_120_40_DRIVE_SOCODT80_VOH40
[Model] DQ_PU_PD_120_40_DRIVE_SOCODT80_VOH40
Model_type I/O
Polarity   Inverting
Vinl =  0.135V
Vinh =  0.305V
Vmeas =  0.220V
Rref =  50.000
Vref =  0.220V
C_comp   1.020pF   1.010pF   1.030pF
[Model Spec]
Vinh   0.305V   0.297V   0.319V
Vinl   0.135V   0.127V   0.149V
Vmeas   0.220V   0.212V   0.234V
Vref   0.220V   0.212V   0.234V
Rref   50.000   NA   NA
[Temperature Range]   25.000   85.000   -40.000
[Voltage Range]   1.100V   1.060V   1.170V
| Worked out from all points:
|   slope of the pulldown table from 0 to 0.165 V, typ, clamps not added: 34.3 ohm
|   GND clamp passes 1 mA (typ) near -0.30 V on its own axis
|   POWER clamp passes 1 mA (typ) near -0.95 V on its own axis
|   rising waveform, R_fixture 50.000, V_fixture 1.100: 20-80 % time 75ps typ, 77.9ps min, 73.6ps max; typ from 0.501 V to 1.1 V
|   rising waveform, R_fixture 50.000, V_fixture 0.0: 20-80 % time 26.2ps typ, 33.8ps min, 21.1ps max; typ from 0 V to 0.38 V
|   falling waveform, R_fixture 50.000, V_fixture 1.100: 20-80 % time 41.4ps typ, 53.3ps min, 34.3ps max; typ from 1.1 V to 0.501 V
|   falling waveform, R_fixture 50.000, V_fixture 0.0: 20-80 % time 34.7ps typ, 53.5ps min, 31.3ps max; typ from 0.38 V to 0 V
[Pulldown]
|Voltage   I(typ)   I(min)   I(max)
-1.1V     -16.81mA   -20.22mA   -14.15mA
-964mV    -16.31mA   -20.04mA   -14.03mA
-692mV    -15.89mA   -18.24mA   -14.43mA
-556mV    -15.13mA   -16.51mA   -14.47mA
-454mV    -13.55mA   -14.21mA   -13.5mA
-318mV    -9.863mA   -10.12mA   -10.07mA
158mV     4.627mA    4.669mA    4.79mA
328mV     8.852mA    8.857mA    9.163mA
498mV     11.93mA    11.73mA    12.38mA
668mV     13.64mA    13.21mA    14.18mA
940mV     15.03mA    14.51mA    15.57mA
2.2V      18.47mA    18.06mA    18.75mA
[Pullup]
|Voltage   I(typ)   I(min)   I(max)
-1.1V     2.7nA      13.54nA    0A
296mV     -15.48uA   -18.58uA   -7.934uA
466mV     -807.4uA   -806.2uA   -632uA
602mV     -3.772mA   -4.103mA   -3.194mA
738mV     -8.234mA   -9.422mA   -6.922mA
976mV     -17.54mA   -20.68mA   -14.55mA
1.35V     -33.63mA   -40.11mA   -27.84mA
1.452V    -36.39mA   -43.62mA   -30.97mA
1.52V     -36.62mA   -44.46mA   -31.62mA
1.724V    -35.34mA   -44.21mA   -29.55mA
1.962V    -34.61mA   -43.64mA   -28.68mA
2.2V      -34.01mA   -40.78mA   -28.06mA
[GND_clamp]
|Voltage   I(typ)   I(min)   I(max)
-1.1V     -92.78mA   -80.14mA   -109.5mA
-1.031V   -81.73mA   -68.77mA   -97.17mA
-939mV    -68.18mA   -56.07mA   -81.64mA
-801mV    -48.85mA   -39.25mA   -59.15mA
-663mV    -30.71mA   -23.84mA   -37.89mA
-571mV    -19.76mA   -14.75mA   -24.85mA
-479mV    -10.5mA    -7.415mA   -13.5mA
-410mV    -5.313mA   -3.546mA   -6.916mA
-341mV    -2.007mA   -1.262mA   -2.59mA
-272mV    -506.9uA   -323.5uA   -609.8uA
-180mV    -45.65uA   -36.06uA   -43.55uA
1.1V      0A         0A         0A
[POWER_clamp]
|Voltage   I(typ)   I(min)   I(max)
-1.1V     5.691mA    8.066mA    3.44mA
-1.062V   3.709mA    5.665mA    2.092mA
-1.039V   2.781mA    4.457mA    1.546mA
-1.016V   2.086mA    3.48mA     1.193mA
-993mV    1.578mA    2.707mA    966.5uA
-970mV    1.21mA     2.107mA    818.5uA
-924mV    750.8uA    1.296mA    641.3uA
-878mV    507uA      821.4uA    530.2uA
-809mV    327.4uA    430uA      403.3uA
-694mV    178.4uA    161uA      233uA
-464mV    19.89uA    15.19uA    23.61uA
1.1V      0A         0A         0A
[Ramp]
| variable   typ   min   max
dV/dt_r   0.228/26.399p   0.222/33.828p   0.239/21.311p
dV/dt_f   0.359/41.391p   0.346/53.458p   0.384/34.203p
R_load = 50.000
[Rising Waveform]
R_fixture= 50.000
V_fixture= 1.100
V_fixture_min= 1.060
V_fixture_max= 1.170
|time   V(typ)   V(min)   V(max)
0s        501.3mV    483mV      529.3mV
148ps     501.8mV    483.6mV    534.7mV
204ps     507.1mV    483mV      905.2mV
270ps     892.9mV    471.7mV    1.097V
289ps     953.9mV    528.4mV    1.114V
337ps     1.043V     819.9mV    1.145V
383ps     1.074V     954.1mV    1.16V
481ps     1.094V     1.044V     1.169V
657ps     1.1V       1.058V     1.17V
3ns       1.1V       1.06V      1.17V
[Rising Waveform]
R_fixture= 50.000
V_fixture= 0.0
V_fixture_min= 0.0
V_fixture_max= 0.0
|time   V(typ)   V(min)   V(max)
0s        2.565uV    4.869uV    596nV
151ps     -51.36uV   49.91uV    9.121mV
191ps     852.2uV    37.32uV    374.4mV
214ps     9.4mV      85.09uV    460.9mV
264ps     355.3mV    981.6uV    499mV
300ps     426mV      26.99mV    418.6mV
339ps     440.1mV    273.1mV    399.7mV
367ps     447.3mV    367.7mV    398.2mV
493ps     379.9mV    415.6mV    397.7mV
3ns       379.9mV    370mV      397.7mV
[Falling Waveform]
R_fixture= 50.000
V_fixture= 1.100
V_fixture_min= 1.060
V_fixture_max= 1.170
|time   V(typ)   V(min)   V(max)
0s        1.1V       1.06V      1.17V
157ps     1.1V       1.06V      1.169V
225ps     1.088V     1.06V      553.4mV
274ps     686.1mV    1.058V     440.3mV
315ps     488.3mV    1.046V     498.9mV
344ps     445.5mV    906.5mV    516.7mV
411ps     469.9mV    523.6mV    527.4mV
494ps     498.6mV    428.9mV    529.1mV
674ps     501.2mV    482.1mV    529.3mV
3ns       501.3mV    483mV      529.3mV
[Falling Waveform]
R_fixture= 50.000
V_fixture= 0.0
V_fixture_min= 0.0
V_fixture_max= 0.0
|time   V(typ)   V(min)   V(max)
0s        379.9mV    370mV      397.7mV
144ps     379mV      369.4mV    406.6mV
181ps     394.9mV    368.6mV    132.1mV
198ps     394.3mV    370.1mV    56.77mV
217ps     321.5mV    376.7mV    22.84mV
253ps     81.83mV    396.5mV    4.625mV
292ps     15.71mV    273mV      -4.717mV
351ps     1.991mV    48.47mV    -414.1uV
435ps     -1.238mV   3.047mV    -10.61uV
3ns       2.36uV     4.739uV    365.5nV
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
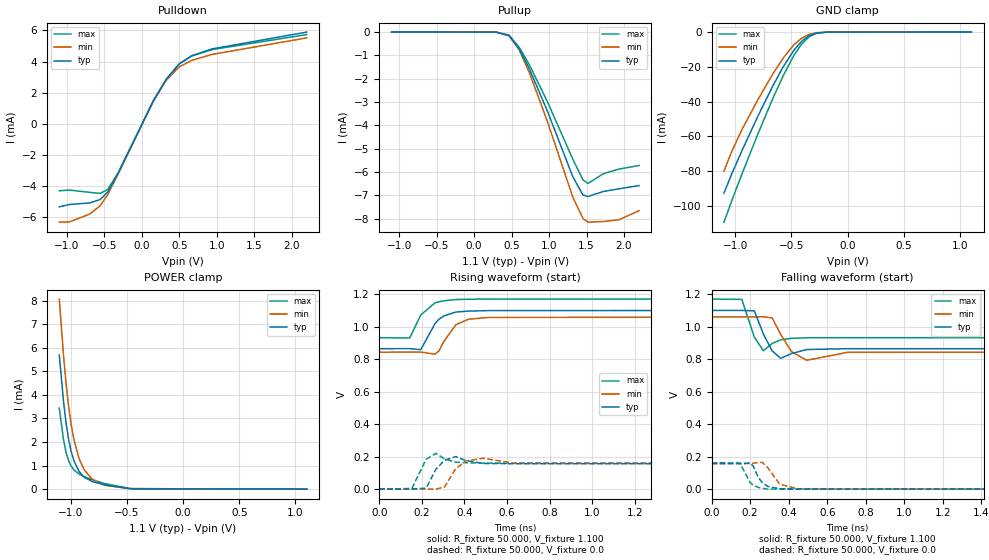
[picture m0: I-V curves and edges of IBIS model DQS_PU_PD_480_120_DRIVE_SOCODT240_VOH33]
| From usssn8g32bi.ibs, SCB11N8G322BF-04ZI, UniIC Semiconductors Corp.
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|   Model DQS_PU_PD_480_120_DRIVE_SOCODT240_VOH33
[Model] DQS_PU_PD_480_120_DRIVE_SOCODT240_VOH33
Model_type I/O
Polarity   Inverting
Vinl =  98.000mV
Vinh =  0.268V
Vmeas =  0.183V
Rref =  50.000
Vref =  0.183V
C_comp   1.020pF   1.010pF   1.030pF
[Model Spec]
Vinh   0.268V   0.262V   0.280V
Vinl   98.000mV   92.000mV   0.110V
Vmeas   0.183V   0.177V   0.195V
Vref   0.183V   0.177V   0.195V
Rref   50.000   NA   NA
[Temperature Range]   25.000   85.000   -40.000
[Voltage Range]   1.100V   1.060V   1.170V
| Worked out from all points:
|   slope of the pulldown table from 0 to 0.165 V, typ, clamps not added: 105 ohm
|   GND clamp passes 1 mA (typ) near -0.30 V on its own axis
|   POWER clamp passes 1 mA (typ) near -0.95 V on its own axis
|   rising waveform, R_fixture 50.000, V_fixture 1.100: 20-80 % time 67.3ps typ, 69.5ps min, 65.4ps max; typ from 0.864 V to 1.1 V
|   rising waveform, R_fixture 50.000, V_fixture 0.0: 20-80 % time 34.7ps typ, 42.8ps min, 28.1ps max; typ from 0 V to 0.156 V
|   falling waveform, R_fixture 50.000, V_fixture 1.100: 20-80 % time 43.5ps typ, 54ps min, 34.2ps max; typ from 1.1 V to 0.864 V
|   falling waveform, R_fixture 50.000, V_fixture 0.0: 20-80 % time 47.3ps typ, 57ps min, 44.1ps max; typ from 0.156 V to 0 V
[Pulldown]
|Voltage   I(typ)   I(min)   I(max)
-1.1V     -5.34mA    -6.324mA   -4.302mA
-964mV    -5.187mA   -6.308mA   -4.26mA
-692mV    -5.084mA   -5.795mA   -4.408mA
-556mV    -4.87mA    -5.274mA   -4.475mA
-454mV    -4.386mA   -4.558mA   -4.222mA
-318mV    -3.209mA   -3.256mA   -3.18mA
158mV     1.503mA    1.489mA    1.509mA
328mV     2.865mA    2.797mA    2.867mA
498mV     3.844mA    3.653mA    3.837mA
668mV     4.377mA    4.078mA    4.359mA
940mV     4.811mA    4.458mA    4.768mA
2.2V      5.891mA    5.519mA    5.73mA
[Pullup]
|Voltage   I(typ)   I(min)   I(max)
-1.1V     500pA      2.606nA    0A
296mV     -2.948uA   -3.529uA   -1.641uA
466mV     -154.8uA   -152.1uA   -129.1uA
602mV     -725.8uA   -765uA     -649.5uA
738mV     -1.585mA   -1.746mA   -1.41mA
976mV     -3.374mA   -3.816mA   -2.972mA
1.316V    -6.198mA   -7.072mA   -5.446mA
1.452V    -6.989mA   -7.995mA   -6.341mA
1.52V     -7.049mA   -8.152mA   -6.489mA
1.724V    -6.835mA   -8.124mA   -6.072mA
1.928V    -6.723mA   -8.051mA   -5.878mA
2.2V      -6.582mA   -7.66mA    -5.721mA
[GND_clamp]
|Voltage   I(typ)   I(min)   I(max)
-1.1V     -92.78mA   -80.14mA   -109.5mA
-1.031V   -81.73mA   -68.77mA   -97.17mA
-939mV    -68.18mA   -56.07mA   -81.64mA
-801mV    -48.85mA   -39.25mA   -59.15mA
-663mV    -30.71mA   -23.84mA   -37.89mA
-571mV    -19.76mA   -14.75mA   -24.85mA
-479mV    -10.5mA    -7.415mA   -13.5mA
-410mV    -5.313mA   -3.546mA   -6.916mA
-341mV    -2.007mA   -1.262mA   -2.59mA
-272mV    -506.9uA   -323.5uA   -609.8uA
-180mV    -45.65uA   -36.06uA   -43.55uA
1.1V      0A         0A         0A
[POWER_clamp]
|Voltage   I(typ)   I(min)   I(max)
-1.1V     5.691mA    8.066mA    3.44mA
-1.062V   3.709mA    5.665mA    2.092mA
-1.039V   2.781mA    4.457mA    1.546mA
-1.016V   2.086mA    3.48mA     1.193mA
-993mV    1.578mA    2.707mA    966.5uA
-970mV    1.21mA     2.107mA    818.5uA
-924mV    750.8uA    1.296mA    641.3uA
-878mV    507uA      821.4uA    530.2uA
-809mV    327.4uA    430uA      403.3uA
-694mV    178.4uA    161uA      233uA
-464mV    19.89uA    15.19uA    23.61uA
1.1V      0A         0A         0A
[Ramp]
| variable   typ   min   max
dV/dt_r   93.600m/34.847p   94.431m/42.832p   96.210m/28.119p
dV/dt_f   0.141/43.472p   0.130/54.008p   0.143/34.237p
R_load = 50.000
[Rising Waveform]
R_fixture= 50.000
V_fixture= 1.100
V_fixture_min= 1.060
V_fixture_max= 1.170
|time   V(typ)   V(min)   V(max)
0s        864.4mV    842.9mV    932.1mV
143ps     864.9mV    843.2mV    930.3mV
195ps     858.5mV    843.5mV    1.072V
262ps     1.019V     830.6mV    1.147V
280ps     1.045V     849.6mV    1.153V
303ps     1.066V     908.7mV    1.159V
360ps     1.09V      1.012V     1.167V
419ps     1.096V     1.046V     1.169V
515ps     1.099V     1.057V     1.17V
3ns       1.1V       1.06V      1.17V
[Rising Waveform]
R_fixture= 50.000
V_fixture= 0.0
V_fixture_min= 0.0
V_fixture_max= 0.0
|time   V(typ)   V(min)   V(max)
0s        4.355uV    8.339uV    1.03uV
153ps     74.34uV    24.45uV    3.815mV
220ps     6.161mV    160.3uV    183.2mV
266ps     122mV      -355.4uV   220.4mV
307ps     178.3mV    13.72mV    185.6mV
359ps     200.5mV    125.5mV    166.2mV
407ps     175.6mV    172.7mV    161.9mV
489ps     157.8mV    190.1mV    160.5mV
639ps     156mV      157.9mV    160.3mV
3ns       156mV      157.4mV    160.3mV
[Falling Waveform]
R_fixture= 50.000
V_fixture= 1.100
V_fixture_min= 1.060
V_fixture_max= 1.170
|time   V(typ)   V(min)   V(max)
0s        1.1V       1.06V      1.17V
157ps     1.1V       1.06V      1.168V
222ps     1.097V     1.06V      934.8mV
269ps     954.3mV    1.061V     852.1mV
314ps     851.5mV    1.054V     896.3mV
359ps     804.9mV    951.9mV    919.1mV
415ps     835mV      845.6mV    928.3mV
494ps     859.3mV    793.1mV    931.4mV
706ps     864.3mV    842.2mV    932.1mV
3ns       864.4mV    842.9mV    932.1mV
[Falling Waveform]
R_fixture= 50.000
V_fixture= 0.0
V_fixture_min= 0.0
V_fixture_max= 0.0
|time   V(typ)   V(min)   V(max)
0s        156mV      157.4mV    160.3mV
146ps     155.8mV    157.2mV    162.8mV
200ps     160.7mV    157.4mV    40.46mV
216ps     141.6mV    158.9mV    23.92mV
242ps     73.57mV    163.5mV    10.3mV
263ps     38.92mV    164.7mV    4.775mV
292ps     15.89mV    131.8mV    -493.3uV
353ps     2.432mV    30.62mV    -170.9uV
445ps     -495.8uV   2.189mV    -7.949uV
3ns       4.229uV    8.19uV     788.9nV
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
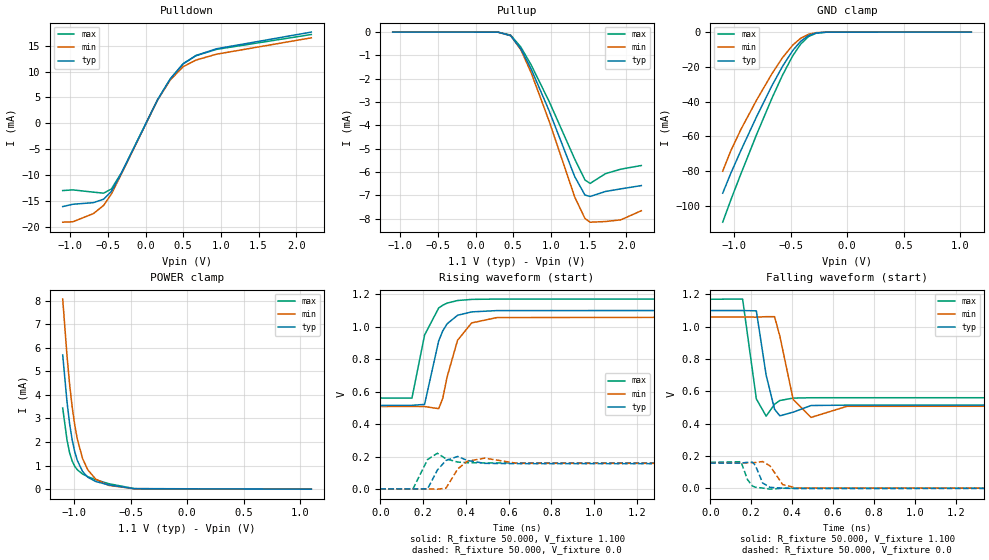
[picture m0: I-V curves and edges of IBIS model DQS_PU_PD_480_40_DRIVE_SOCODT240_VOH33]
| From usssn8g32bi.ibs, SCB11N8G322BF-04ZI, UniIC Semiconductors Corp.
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|   Model DQS_PU_PD_480_40_DRIVE_SOCODT240_VOH33
[Model] DQS_PU_PD_480_40_DRIVE_SOCODT240_VOH33
Model_type I/O
Polarity   Inverting
Vinl =  98.000mV
Vinh =  0.268V
Vmeas =  0.183V
Rref =  50.000
Vref =  0.183V
C_comp   1.020pF   1.010pF   1.030pF
[Model Spec]
Vinh   0.268V   0.262V   0.280V
Vinl   98.000mV   92.000mV   0.110V
Vmeas   0.183V   0.177V   0.195V
Vref   0.183V   0.177V   0.195V
Rref   50.000   NA   NA
[Temperature Range]   25.000   85.000   -40.000
[Voltage Range]   1.100V   1.060V   1.170V
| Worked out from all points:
|   slope of the pulldown table from 0 to 0.165 V, typ, clamps not added: 35.3 ohm
|   GND clamp passes 1 mA (typ) near -0.30 V on its own axis
|   POWER clamp passes 1 mA (typ) near -0.95 V on its own axis
|   rising waveform, R_fixture 50.000, V_fixture 1.100: 20-80 % time 69.5ps typ, 72.6ps min, 66.9ps max; typ from 0.514 V to 1.1 V
|   rising waveform, R_fixture 50.000, V_fixture 0.0: 20-80 % time 34.2ps typ, 41.9ps min, 28ps max; typ from 0 V to 0.156 V
|   falling waveform, R_fixture 50.000, V_fixture 1.100: 20-80 % time 39.1ps typ, 49.9ps min, 32ps max; typ from 1.1 V to 0.514 V
|   falling waveform, R_fixture 50.000, V_fixture 0.0: 20-80 % time 30.8ps typ, 46.2ps min, 27.5ps max; typ from 0.156 V to 0 V
[Pulldown]
|Voltage   I(typ)   I(min)   I(max)
-1.1V     -16.13mA   -19.15mA   -13.03mA
-964mV    -15.68mA   -19.06mA   -12.9mA
-692mV    -15.37mA   -17.49mA   -13.34mA
-556mV    -14.7mA    -15.89mA   -13.53mA
-454mV    -13.2mA    -13.69mA   -12.73mA
-318mV    -9.609mA   -9.745mA   -9.529mA
158mV     4.492mA    4.453mA    4.512mA
328mV     8.568mA    8.368mA    8.576mA
498mV     11.5mA     10.93mA    11.48mA
668mV     13.1mA     12.21mA    13.05mA
940mV     14.4mA     13.35mA    14.28mA
2.2V      17.63mA    16.52mA    17.16mA
[Pullup]
|Voltage   I(typ)   I(min)   I(max)
-1.1V     500pA      2.606nA    0A
296mV     -2.948uA   -3.529uA   -1.641uA
466mV     -154.8uA   -152.1uA   -129.1uA
602mV     -725.8uA   -765uA     -649.5uA
738mV     -1.585mA   -1.746mA   -1.41mA
976mV     -3.374mA   -3.816mA   -2.972mA
1.316V    -6.198mA   -7.072mA   -5.446mA
1.452V    -6.989mA   -7.995mA   -6.341mA
1.52V     -7.049mA   -8.152mA   -6.489mA
1.724V    -6.835mA   -8.124mA   -6.072mA
1.928V    -6.723mA   -8.051mA   -5.878mA
2.2V      -6.582mA   -7.66mA    -5.721mA
[GND_clamp]
|Voltage   I(typ)   I(min)   I(max)
-1.1V     -92.78mA   -80.14mA   -109.5mA
-1.031V   -81.73mA   -68.77mA   -97.17mA
-939mV    -68.18mA   -56.07mA   -81.64mA
-801mV    -48.85mA   -39.25mA   -59.15mA
-663mV    -30.71mA   -23.84mA   -37.89mA
-571mV    -19.76mA   -14.75mA   -24.85mA
-479mV    -10.5mA    -7.415mA   -13.5mA
-410mV    -5.313mA   -3.546mA   -6.916mA
-341mV    -2.007mA   -1.262mA   -2.59mA
-272mV    -506.9uA   -323.5uA   -609.8uA
-180mV    -45.65uA   -36.06uA   -43.55uA
1.1V      0A         0A         0A
[POWER_clamp]
|Voltage   I(typ)   I(min)   I(max)
-1.1V     5.691mA    8.066mA    3.44mA
-1.062V   3.709mA    5.665mA    2.092mA
-1.039V   2.781mA    4.457mA    1.546mA
-1.016V   2.086mA    3.48mA     1.193mA
-993mV    1.578mA    2.707mA    966.5uA
-970mV    1.21mA     2.107mA    818.5uA
-924mV    750.8uA    1.296mA    641.3uA
-878mV    507uA      821.4uA    530.2uA
-809mV    327.4uA    430uA      403.3uA
-694mV    178.4uA    161uA      233uA
-464mV    19.89uA    15.19uA    23.61uA
1.1V      0A         0A         0A
[Ramp]
| variable   typ   min   max
dV/dt_r   93.601m/34.283p   94.433m/41.957p   96.210m/28.176p
dV/dt_f   0.351/39.219p   0.331/49.966p   0.366/32.033p
R_load = 50.000
[Rising Waveform]
R_fixture= 50.000
V_fixture= 1.100
V_fixture_min= 1.060
V_fixture_max= 1.170
|time   V(typ)   V(min)   V(max)
0s        514.4mV    508.1mV    560.3mV
148ps     515.3mV    508.7mV    560.1mV
207ps     521.1mV    507.9mV    948.2mV
273ps     912.5mV    494.6mV    1.115V
292ps     973.8mV    558.5mV    1.132V
312ps     1.017V     688.9mV    1.145V
361ps     1.07V      915.7mV    1.161V
427ps     1.091V     1.023V     1.168V
545ps     1.099V     1.056V     1.17V
3ns       1.1V       1.06V      1.17V
[Rising Waveform]
R_fixture= 50.000
V_fixture= 0.0
V_fixture_min= 0.0
V_fixture_max= 0.0
|time   V(typ)   V(min)   V(max)
0s        2.608uV    4.994uV    615.8nV
153ps     338.9uV    5.864uV    848.7uV
221ps     926.7uV    612.9uV    181.4mV
267ps     116.6mV    -1.202mV   220mV
307ps     175.9mV    4.586mV    185.5mV
362ps     200.5mV    123.4mV    165.7mV
406ps     176.1mV    170.4mV    161.9mV
488ps     157.8mV    190mV      160.5mV
639ps     156mV      157.9mV    160.3mV
3ns       156mV      157.4mV    160.3mV
[Falling Waveform]
R_fixture= 50.000
V_fixture= 1.100
V_fixture_min= 1.060
V_fixture_max= 1.170
|time   V(typ)   V(min)   V(max)
0s        1.1V       1.06V      1.17V
158ps     1.1V       1.06V      1.171V
225ps     1.098V     1.059V     553.2mV
273ps     699.3mV    1.062V     445.9mV
314ps     488.7mV    1.062V     520mV
340ps     448.3mV    940.7mV    543.1mV
405ps     470.7mV    549.6mV    558mV
492ps     512mV      438.3mV    560.1mV
668ps     514.4mV    507.1mV    560.3mV
3ns       514.4mV    508.1mV    560.3mV
[Falling Waveform]
R_fixture= 50.000
V_fixture= 0.0
V_fixture_min= 0.0
V_fixture_max= 0.0
|time   V(typ)   V(min)   V(max)
0s        156mV      157.4mV    160.3mV
150ps     155.8mV    157.2mV    164.1mV
182ps     160.4mV    157mV      52.86mV
206ps     161.1mV    157.6mV    13.75mV
220ps     142.3mV    159.1mV    6.183mV
256ps     32.17mV    165.1mV    1.048mV
292ps     5.298mV    138.1mV    -5.847mV
354ps     479uV      21.99mV    -339.8uV
424ps     -2.4mV     1.174mV    -4.641uV
3ns       2.399uV    4.891uV    131.8nV
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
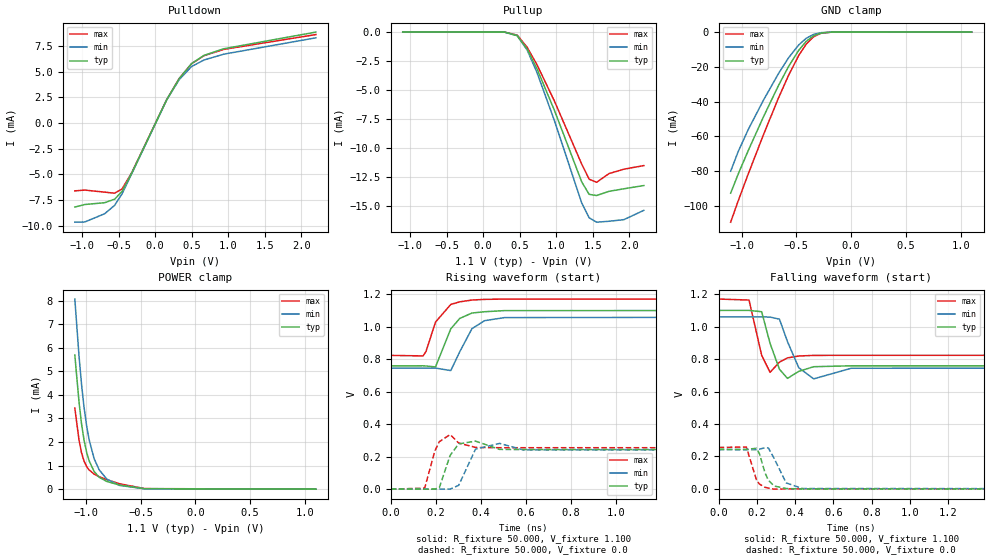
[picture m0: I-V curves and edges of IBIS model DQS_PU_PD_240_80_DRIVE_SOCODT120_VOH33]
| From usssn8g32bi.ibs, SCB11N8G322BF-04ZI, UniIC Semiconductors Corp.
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|   Model DQS_PU_PD_240_80_DRIVE_SOCODT120_VOH33
[Model] DQS_PU_PD_240_80_DRIVE_SOCODT120_VOH33
Model_type I/O
Polarity   Inverting
Vinl =  98.000mV
Vinh =  0.268V
Vmeas =  0.183V
Rref =  50.000
Vref =  0.183V
C_comp   1.020pF   1.010pF   1.030pF
[Model Spec]
Vinh   0.268V   0.262V   0.280V
Vinl   98.000mV   92.000mV   0.110V
Vmeas   0.183V   0.177V   0.195V
Vref   0.183V   0.177V   0.195V
Rref   50.000   NA   NA
[Temperature Range]   25.000   85.000   -40.000
[Voltage Range]   1.100V   1.060V   1.170V
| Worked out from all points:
|   slope of the pulldown table from 0 to 0.165 V, typ, clamps not added: 70.2 ohm
|   GND clamp passes 1 mA (typ) near -0.30 V on its own axis
|   POWER clamp passes 1 mA (typ) near -0.95 V on its own axis
|   rising waveform, R_fixture 50.000, V_fixture 1.100: 20-80 % time 67.8ps typ, 69.9ps min, 65.7ps max; typ from 0.759 V to 1.1 V
|   rising waveform, R_fixture 50.000, V_fixture 0.0: 20-80 % time 31.5ps typ, 38.9ps min, 25.7ps max; typ from 0 V to 0.244 V
|   falling waveform, R_fixture 50.000, V_fixture 1.100: 20-80 % time 43.3ps typ, 54.1ps min, 34.4ps max; typ from 1.1 V to 0.759 V
|   falling waveform, R_fixture 50.000, V_fixture 0.0: 20-80 % time 42.7ps typ, 56ps min, 38.4ps max; typ from 0.244 V to 0 V
[Pulldown]
|Voltage   I(typ)   I(min)   I(max)
-1.1V     -8.193mA   -9.666mA   -6.618mA
-964mV    -7.945mA   -9.646mA   -6.54mA
-692mV    -7.769mA   -8.844mA   -6.742mA
-556mV    -7.432mA   -8.032mA   -6.841mA
-454mV    -6.673mA   -6.916mA   -6.44mA
-318mV    -4.841mA   -4.906mA   -4.804mA
158mV     2.257mA    2.237mA    2.267mA
328mV     4.302mA    4.2mA      4.305mA
498mV     5.77mA     5.483mA    5.759mA
668mV     6.567mA    6.118mA    6.54mA
940mV     7.217mA    6.688mA    7.152mA
2.2V      8.836mA    8.278mA    8.595mA
[Pullup]
|Voltage   I(typ)   I(min)   I(max)
-1.1V     1nA        5.218nA    0A
296mV     -5.896uA   -7.058uA   -3.281uA
466mV     -309.5uA   -304uA     -258.1uA
602mV     -1.45mA    -1.529mA   -1.298mA
738mV     -3.167mA   -3.489mA   -2.817mA
976mV     -6.74mA    -7.622mA   -5.938mA
1.35V     -12.91mA   -14.73mA   -11.38mA
1.452V    -13.99mA   -16.01mA   -12.68mA
1.554V    -14.09mA   -16.39mA   -12.95mA
1.724V    -13.73mA   -16.31mA   -12.2mA
1.928V    -13.51mA   -16.17mA   -11.82mA
2.2V      -13.23mA   -15.37mA   -11.51mA
[GND_clamp]
|Voltage   I(typ)   I(min)   I(max)
-1.1V     -92.78mA   -80.14mA   -109.5mA
-1.031V   -81.73mA   -68.77mA   -97.17mA
-939mV    -68.18mA   -56.07mA   -81.64mA
-801mV    -48.85mA   -39.25mA   -59.15mA
-663mV    -30.71mA   -23.84mA   -37.89mA
-571mV    -19.76mA   -14.75mA   -24.85mA
-479mV    -10.5mA    -7.415mA   -13.5mA
-410mV    -5.313mA   -3.546mA   -6.916mA
-341mV    -2.007mA   -1.262mA   -2.59mA
-272mV    -506.9uA   -323.5uA   -609.8uA
-180mV    -45.65uA   -36.06uA   -43.55uA
1.1V      0A         0A         0A
[POWER_clamp]
|Voltage   I(typ)   I(min)   I(max)
-1.1V     5.691mA    8.066mA    3.44mA
-1.062V   3.709mA    5.665mA    2.092mA
-1.039V   2.781mA    4.457mA    1.546mA
-1.016V   2.086mA    3.48mA     1.193mA
-993mV    1.578mA    2.707mA    966.5uA
-970mV    1.21mA     2.107mA    818.5uA
-924mV    750.8uA    1.296mA    641.3uA
-878mV    507uA      821.4uA    530.2uA
-809mV    327.4uA    430uA      403.3uA
-694mV    178.4uA    161uA      233uA
-464mV    19.89uA    15.19uA    23.61uA
1.1V      0A         0A         0A
[Ramp]
| variable   typ   min   max
dV/dt_r   0.146/31.561p   0.145/38.947p   0.153/25.792p
dV/dt_f   0.205/43.467p   0.189/54.165p   0.208/34.505p
R_load = 50.000
[Rising Waveform]
R_fixture= 50.000
V_fixture= 1.100
V_fixture_min= 1.060
V_fixture_max= 1.170
|time   V(typ)   V(min)   V(max)
0s        758.6mV    744.6mV    823.3mV
144ps     759.4mV    744.9mV    820.1mV
157ps     758mV      745.3mV    847.8mV
199ps     752.4mV    745.2mV    1.028V
267ps     986.6mV    730mV      1.137V
307ps     1.051V     846.1mV    1.153V
361ps     1.084V     987.7mV    1.164V
417ps     1.092V     1.037V     1.168V
506ps     1.099V     1.056V     1.17V
3ns       1.1V       1.06V      1.17V
[Rising Waveform]
R_fixture= 50.000
V_fixture= 0.0
V_fixture_min= 0.0
V_fixture_max= 0.0
|time   V(typ)   V(min)   V(max)
0s        3.731uV    7.145uV    881.9nV
151ps     -3.997uV   20.52uV    6.343mV
196ps     833uV      22.98uV    234.7mV
216ps     8.706mV    115.6uV    292.1mV
264ps     207.7mV    595.6uV    336.3mV
302ps     278.7mV    23.35mV    283.9mV
377ps     295.6mV    246.7mV    256.8mV
484ps     244.6mV    281.6mV    255.1mV
589ps     243.9mV    241.7mV    255mV
3ns       243.9mV    241.2mV    255mV
[Falling Waveform]
R_fixture= 50.000
V_fixture= 1.100
V_fixture_min= 1.060
V_fixture_max= 1.170
|time   V(typ)   V(min)   V(max)
0s        1.1V       1.06V      1.17V
159ps     1.1V       1.06V      1.164V
225ps     1.092V     1.06V      823.5mV
269ps     896.6mV    1.059V     718.2mV
318ps     737.2mV    1.046V     781.2mV
360ps     681mV      907.6mV    807.3mV
419ps     724.3mV    746.7mV    819.1mV
497ps     752.9mV    678mV      822.6mV
693ps     758.5mV    743.3mV    823.3mV
3ns       758.6mV    744.6mV    823.3mV
[Falling Waveform]
R_fixture= 50.000
V_fixture= 0.0
V_fixture_min= 0.0
V_fixture_max= 0.0
|time   V(typ)   V(min)   V(max)
0s        243.9mV    241.2mV    255mV
145ps     243.7mV    240.8mV    257.9mV
198ps     249.8mV    241.5mV    54.02mV
214ps     214.8mV    244.4mV    28.79mV
242ps     100.3mV    253.5mV    9.618mV
260ps     52.88mV    252.3mV    4.471mV
291ps     17.08mV    185.9mV    -2.141mV
353ps     1.797mV    36.55mV    -355.3uV
438ps     -886uV     2.145mV    -13.64uV
3ns       -1.257uV   7.091uV    556.3nV
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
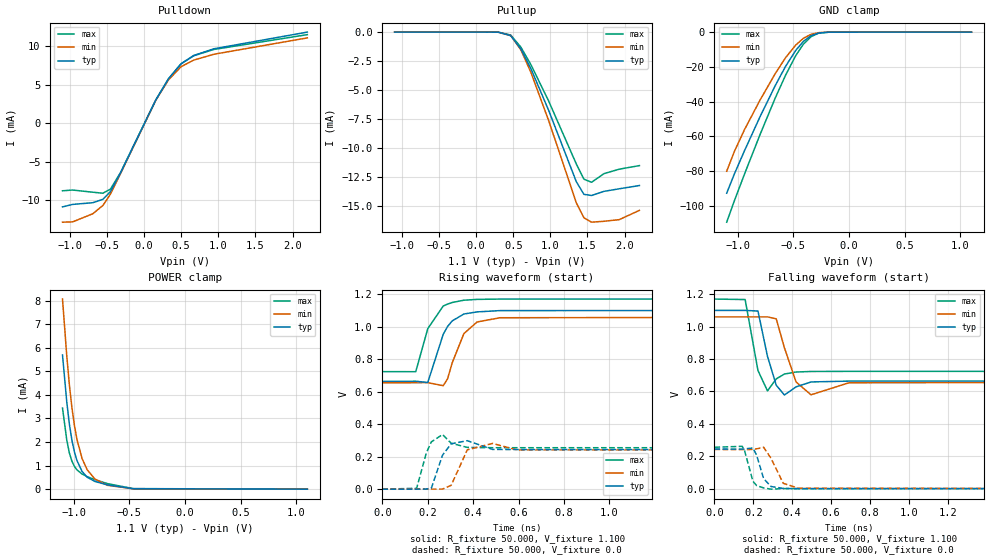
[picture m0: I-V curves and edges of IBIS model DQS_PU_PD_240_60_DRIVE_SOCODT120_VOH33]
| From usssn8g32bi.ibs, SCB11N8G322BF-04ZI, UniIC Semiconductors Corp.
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|   Model DQS_PU_PD_240_60_DRIVE_SOCODT120_VOH33
[Model] DQS_PU_PD_240_60_DRIVE_SOCODT120_VOH33
Model_type I/O
Polarity   Inverting
Vinl =  98.000mV
Vinh =  0.268V
Vmeas =  0.183V
Rref =  50.000
Vref =  0.183V
C_comp   1.020pF   1.010pF   1.030pF
[Model Spec]
Vinh   0.268V   0.262V   0.280V
Vinl   98.000mV   92.000mV   0.110V
Vmeas   0.183V   0.177V   0.195V
Vref   0.183V   0.177V   0.195V
Rref   50.000   NA   NA
[Temperature Range]   25.000   85.000   -40.000
[Voltage Range]   1.100V   1.060V   1.170V
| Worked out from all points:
|   slope of the pulldown table from 0 to 0.165 V, typ, clamps not added: 52.7 ohm
|   GND clamp passes 1 mA (typ) near -0.30 V on its own axis
|   POWER clamp passes 1 mA (typ) near -0.95 V on its own axis
|   rising waveform, R_fixture 50.000, V_fixture 1.100: 20-80 % time 68.5ps typ, 71ps min, 66.2ps max; typ from 0.663 V to 1.1 V
|   rising waveform, R_fixture 50.000, V_fixture 0.0: 20-80 % time 31.5ps typ, 38.7ps min, 25.6ps max; typ from 0 V to 0.244 V
|   falling waveform, R_fixture 50.000, V_fixture 1.100: 20-80 % time 42.5ps typ, 53.2ps min, 33.9ps max; typ from 1.1 V to 0.663 V
|   falling waveform, R_fixture 50.000, V_fixture 0.0: 20-80 % time 38.6ps typ, 54.3ps min, 33.8ps max; typ from 0.244 V to 0 V
[Pulldown]
|Voltage   I(typ)   I(min)   I(max)
-1.1V     -10.83mA   -12.81mA   -8.746mA
-964mV    -10.51mA   -12.77mA   -8.65mA
-692mV    -10.29mA   -11.72mA   -8.932mA
-556mV    -9.849mA   -10.65mA   -9.063mA
-454mV    -8.849mA   -9.178mA   -8.534mA
-318mV    -6.436mA   -6.525mA   -6.383mA
158mV     3.005mA    2.979mA    3.019mA
328mV     5.729mA    5.594mA    5.734mA
498mV     7.686mA    7.305mA    7.672mA
668mV     8.751mA    8.153mA    8.715mA
940mV     9.618mA    8.913mA    9.532mA
2.2V      11.78mA    11.03mA    11.45mA
[Pullup]
|Voltage   I(typ)   I(min)   I(max)
-1.1V     1nA        5.218nA    0A
296mV     -5.896uA   -7.058uA   -3.281uA
466mV     -309.5uA   -304uA     -258.1uA
602mV     -1.45mA    -1.529mA   -1.298mA
738mV     -3.167mA   -3.489mA   -2.817mA
976mV     -6.74mA    -7.622mA   -5.938mA
1.35V     -12.91mA   -14.73mA   -11.38mA
1.452V    -13.99mA   -16.01mA   -12.68mA
1.554V    -14.09mA   -16.39mA   -12.95mA
1.724V    -13.73mA   -16.31mA   -12.2mA
1.928V    -13.51mA   -16.17mA   -11.82mA
2.2V      -13.23mA   -15.37mA   -11.51mA
[GND_clamp]
|Voltage   I(typ)   I(min)   I(max)
-1.1V     -92.78mA   -80.14mA   -109.5mA
-1.031V   -81.73mA   -68.77mA   -97.17mA
-939mV    -68.18mA   -56.07mA   -81.64mA
-801mV    -48.85mA   -39.25mA   -59.15mA
-663mV    -30.71mA   -23.84mA   -37.89mA
-571mV    -19.76mA   -14.75mA   -24.85mA
-479mV    -10.5mA    -7.415mA   -13.5mA
-410mV    -5.313mA   -3.546mA   -6.916mA
-341mV    -2.007mA   -1.262mA   -2.59mA
-272mV    -506.9uA   -323.5uA   -609.8uA
-180mV    -45.65uA   -36.06uA   -43.55uA
1.1V      0A         0A         0A
[POWER_clamp]
|Voltage   I(typ)   I(min)   I(max)
-1.1V     5.691mA    8.066mA    3.44mA
-1.062V   3.709mA    5.665mA    2.092mA
-1.039V   2.781mA    4.457mA    1.546mA
-1.016V   2.086mA    3.48mA     1.193mA
-993mV    1.578mA    2.707mA    966.5uA
-970mV    1.21mA     2.107mA    818.5uA
-924mV    750.8uA    1.296mA    641.3uA
-878mV    507uA      821.4uA    530.2uA
-809mV    327.4uA    430uA      403.3uA
-694mV    178.4uA    161uA      233uA
-464mV    19.89uA    15.19uA    23.61uA
1.1V      0A         0A         0A
[Ramp]
| variable   typ   min   max
dV/dt_r   0.146/31.577p   0.145/38.730p   0.153/25.711p
dV/dt_f   0.262/42.505p   0.243/53.299p   0.268/33.904p
R_load = 50.000
[Rising Waveform]
R_fixture= 50.000
V_fixture= 1.100
V_fixture_min= 1.060
V_fixture_max= 1.170
|time   V(typ)   V(min)   V(max)
0s        663.5mV    654.8mV    723.5mV
147ps     664.3mV    655.3mV    722.9mV
200ps     656.6mV    655.5mV    987.9mV
268ps     952.9mV    637mV      1.127V
287ps     1.001V     678.6mV    1.139V
308ps     1.036V     779.2mV    1.149V
359ps     1.078V     957.3mV    1.163V
417ps     1.091V     1.029V     1.168V
518ps     1.099V     1.055V     1.17V
3ns       1.1V       1.06V      1.17V
[Rising Waveform]
R_fixture= 50.000
V_fixture= 0.0
V_fixture_min= 0.0
V_fixture_max= 0.0
|time   V(typ)   V(min)   V(max)
0s        3.261uV    6.245uV    770.5nV
151ps     62.75uV    18.11uV    5.487mV
194ps     633uV      47.74uV    224.9mV
216ps     7.25mV     224.7uV    291.5mV
265ps     209.6mV    511.9uV    336.2mV
303ps     279.3mV    23.56mV    282.7mV
374ps     298.4mV    242mV      257mV
485ps     244.6mV    281.6mV    255.1mV
593ps     243.9mV    241.6mV    255mV
3ns       243.9mV    241.2mV    255mV
[Falling Waveform]
R_fixture= 50.000
V_fixture= 1.100
V_fixture_min= 1.060
V_fixture_max= 1.170
|time   V(typ)   V(min)   V(max)
0s        1.1V       1.06V      1.17V
158ps     1.1V       1.06V      1.167V
224ps     1.096V     1.06V      728.9mV
273ps     816.2mV    1.06V      602.8mV
318ps     638.4mV    1.048V     677.1mV
360ps     577.5mV    869.6mV    707mV
420ps     627.8mV    658.1mV    719.6mV
497ps     658.2mV    578.8mV    722.9mV
693ps     663.4mV    653.5mV    723.5mV
3ns       663.5mV    654.8mV    723.5mV
[Falling Waveform]
R_fixture= 50.000
V_fixture= 0.0
V_fixture_min= 0.0
V_fixture_max= 0.0
|time   V(typ)   V(min)   V(max)
0s        243.9mV    241.2mV    255mV
143ps     243.5mV    240.9mV    260.7mV
155ps     245mV      240.7mV    234.5mV
198ps     250.4mV    241.4mV    44.73mV
217ps     206.7mV    245.1mV    18.65mV
253ps     61.64mV    255mV      3.714mV
291ps     12.68mV    187.3mV    -3.823mV
354ps     989uV      32.54mV    -422.2uV
433ps     -1.306mV   1.715mV    -12.07uV
3ns       2.917uV    1.908uV    497.8nV
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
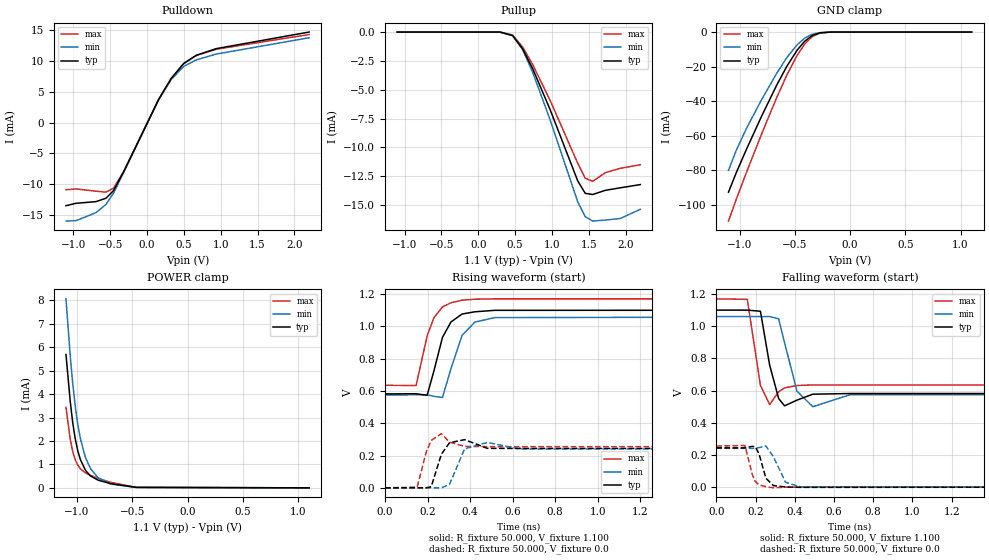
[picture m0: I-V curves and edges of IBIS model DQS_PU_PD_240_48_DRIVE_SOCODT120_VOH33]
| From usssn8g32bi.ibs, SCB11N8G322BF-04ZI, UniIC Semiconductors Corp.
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|   Model DQS_PU_PD_240_48_DRIVE_SOCODT120_VOH33
[Model] DQS_PU_PD_240_48_DRIVE_SOCODT120_VOH33
Model_type I/O
Polarity   Inverting
Vinl =  98.000mV
Vinh =  0.268V
Vmeas =  0.183V
Rref =  50.000
Vref =  0.183V
C_comp   1.020pF   1.010pF   1.030pF
[Model Spec]
Vinh   0.268V   0.262V   0.280V
Vinl   98.000mV   92.000mV   0.110V
Vmeas   0.183V   0.177V   0.195V
Vref   0.183V   0.177V   0.195V
Rref   50.000   NA   NA
[Temperature Range]   25.000   85.000   -40.000
[Voltage Range]   1.100V   1.060V   1.170V
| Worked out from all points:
|   slope of the pulldown table from 0 to 0.165 V, typ, clamps not added: 42.3 ohm
|   GND clamp passes 1 mA (typ) near -0.30 V on its own axis
|   POWER clamp passes 1 mA (typ) near -0.95 V on its own axis
|   rising waveform, R_fixture 50.000, V_fixture 1.100: 20-80 % time 68.9ps typ, 71.6ps min, 66.6ps max; typ from 0.582 V to 1.1 V
|   rising waveform, R_fixture 50.000, V_fixture 0.0: 20-80 % time 31.3ps typ, 38.5ps min, 25.6ps max; typ from 0 V to 0.244 V
|   falling waveform, R_fixture 50.000, V_fixture 1.100: 20-80 % time 41ps typ, 51.9ps min, 33.1ps max; typ from 1.1 V to 0.582 V
|   falling waveform, R_fixture 50.000, V_fixture 0.0: 20-80 % time 35ps typ, 51.8ps min, 30.3ps max; typ from 0.244 V to 0 V
[Pulldown]
|Voltage   I(typ)   I(min)   I(max)
-1.1V     -13.51mA   -16mA      -10.91mA
-964mV    -13.12mA   -15.94mA   -10.79mA
-692mV    -12.85mA   -14.63mA   -11.15mA
-556mV    -12.29mA   -13.29mA   -11.31mA
-454mV    -11.04mA   -11.45mA   -10.65mA
-318mV    -8.03mA    -8.142mA   -7.964mA
158mV     3.751mA    3.718mA    3.768mA
328mV     7.153mA    6.985mA    7.158mA
498mV     9.598mA    9.123mA    9.581mA
668mV     10.93mA    10.18mA    10.89mA
940mV     12.01mA    11.13mA    11.91mA
2.2V      14.71mA    13.78mA    14.31mA
[Pullup]
|Voltage   I(typ)   I(min)   I(max)
-1.1V     1nA        5.218nA    0A
296mV     -5.896uA   -7.058uA   -3.281uA
466mV     -309.5uA   -304uA     -258.1uA
602mV     -1.45mA    -1.529mA   -1.298mA
738mV     -3.167mA   -3.489mA   -2.817mA
976mV     -6.74mA    -7.622mA   -5.938mA
1.35V     -12.91mA   -14.73mA   -11.38mA
1.452V    -13.99mA   -16.01mA   -12.68mA
1.554V    -14.09mA   -16.39mA   -12.95mA
1.724V    -13.73mA   -16.31mA   -12.2mA
1.928V    -13.51mA   -16.17mA   -11.82mA
2.2V      -13.23mA   -15.37mA   -11.51mA
[GND_clamp]
|Voltage   I(typ)   I(min)   I(max)
-1.1V     -92.78mA   -80.14mA   -109.5mA
-1.031V   -81.73mA   -68.77mA   -97.17mA
-939mV    -68.18mA   -56.07mA   -81.64mA
-801mV    -48.85mA   -39.25mA   -59.15mA
-663mV    -30.71mA   -23.84mA   -37.89mA
-571mV    -19.76mA   -14.75mA   -24.85mA
-479mV    -10.5mA    -7.415mA   -13.5mA
-410mV    -5.313mA   -3.546mA   -6.916mA
-341mV    -2.007mA   -1.262mA   -2.59mA
-272mV    -506.9uA   -323.5uA   -609.8uA
-180mV    -45.65uA   -36.06uA   -43.55uA
1.1V      0A         0A         0A
[POWER_clamp]
|Voltage   I(typ)   I(min)   I(max)
-1.1V     5.691mA    8.066mA    3.44mA
-1.062V   3.709mA    5.665mA    2.092mA
-1.039V   2.781mA    4.457mA    1.546mA
-1.016V   2.086mA    3.48mA     1.193mA
-993mV    1.578mA    2.707mA    966.5uA
-970mV    1.21mA     2.107mA    818.5uA
-924mV    750.8uA    1.296mA    641.3uA
-878mV    507uA      821.4uA    530.2uA
-809mV    327.4uA    430uA      403.3uA
-694mV    178.4uA    161uA      233uA
-464mV    19.89uA    15.19uA    23.61uA
1.1V      0A         0A         0A
[Ramp]
| variable   typ   min   max
dV/dt_r   0.146/31.315p   0.145/38.511p   0.153/25.661p
dV/dt_f   0.311/41.212p   0.291/51.945p   0.321/33.181p
R_load = 50.000
[Rising Waveform]
R_fixture= 50.000
V_fixture= 1.100
V_fixture_min= 1.060
V_fixture_max= 1.170
|time   V(typ)   V(min)   V(max)
0s        581.6mV    575.3mV    635mV
146ps     582.5mV    575.8mV    633.3mV
198ps     573.1mV    576.3mV    941.5mV
230ps     725.2mV    566.4mV    1.054V
270ps     931.5mV    559.5mV    1.12V
310ps     1.027V     737.7mV    1.146V
362ps     1.076V     943.7mV    1.162V
422ps     1.09V      1.026V     1.168V
516ps     1.099V     1.054V     1.17V
3ns       1.1V       1.06V      1.17V
[Rising Waveform]
R_fixture= 50.000
V_fixture= 0.0
V_fixture_min= 0.0
V_fixture_max= 0.0
|time   V(typ)   V(min)   V(max)
0s        2.898uV    5.55uV     684.5nV
151ps     145.1uV    12.92uV    4.696mV
194ps     294.7uV    101.1uV    223.6mV
217ps     7.239mV    360.6uV    293.1mV
265ps     208.4mV    65.83uV    336.1mV
303ps     278.9mV    21.01mV    282.8mV
374ps     298.4mV    241.5mV    257mV
481ps     244.7mV    281.3mV    255.1mV
629ps     243.9mV    241.2mV    255mV
3ns       243.9mV    241.2mV    255mV
[Falling Waveform]
R_fixture= 50.000
V_fixture= 1.100
V_fixture_min= 1.060
V_fixture_max= 1.170
|time   V(typ)   V(min)   V(max)
0s        1.1V       1.06V      1.17V
158ps     1.1V       1.06V      1.167V
225ps     1.093V     1.06V      631.9mV
272ps     758.1mV    1.06V      513.2mV
318ps     550mV      1.046V     592.4mV
348ps     505.1mV    898.5mV    616.5mV
411ps     540.2mV    597.1mV    631.5mV
492ps     577.3mV    499.6mV    634.6mV
682ps     581.5mV    574.1mV    635mV
3ns       581.6mV    575.3mV    635mV
[Falling Waveform]
R_fixture= 50.000
V_fixture= 0.0
V_fixture_min= 0.0
V_fixture_max= 0.0
|time   V(typ)   V(min)   V(max)
0s        243.9mV    241.2mV    255mV
146ps     243.7mV    240.8mV    258.4mV
182ps     253mV      240.5mV    83.12mV
198ps     251.2mV    241.4mV    36.59mV
217ps     208.9mV    245mV      13.49mV
253ps     54.78mV    255mV      2.284mV
291ps     9.259mV    189.2mV    -4.849mV
353ps     681.6uV    29.95mV    -413uV
428ps     -1.804mV   1.418mV    -8.182uV
3ns       2.805uV    5.456uV    349.9nV
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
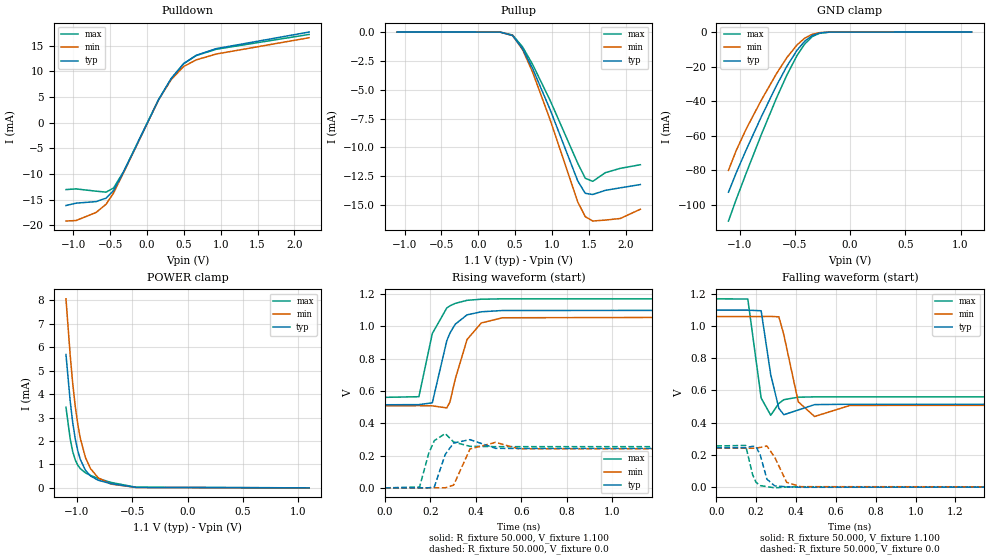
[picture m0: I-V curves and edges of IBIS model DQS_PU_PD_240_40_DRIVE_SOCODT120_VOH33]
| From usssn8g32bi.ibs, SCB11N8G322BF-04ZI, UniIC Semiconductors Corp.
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|   Model DQS_PU_PD_240_40_DRIVE_SOCODT120_VOH33
[Model] DQS_PU_PD_240_40_DRIVE_SOCODT120_VOH33
Model_type I/O
Polarity   Inverting
Vinl =  98.000mV
Vinh =  0.268V
Vmeas =  0.183V
Rref =  50.000
Vref =  0.183V
C_comp   1.020pF   1.010pF   1.030pF
[Model Spec]
Vinh   0.268V   0.262V   0.280V
Vinl   98.000mV   92.000mV   0.110V
Vmeas   0.183V   0.177V   0.195V
Vref   0.183V   0.177V   0.195V
Rref   50.000   NA   NA
[Temperature Range]   25.000   85.000   -40.000
[Voltage Range]   1.100V   1.060V   1.170V
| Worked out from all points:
|   slope of the pulldown table from 0 to 0.165 V, typ, clamps not added: 35.3 ohm
|   GND clamp passes 1 mA (typ) near -0.30 V on its own axis
|   POWER clamp passes 1 mA (typ) near -0.95 V on its own axis
|   rising waveform, R_fixture 50.000, V_fixture 1.100: 20-80 % time 69.3ps typ, 72.4ps min, 66.8ps max; typ from 0.514 V to 1.1 V
|   rising waveform, R_fixture 50.000, V_fixture 0.0: 20-80 % time 31.3ps typ, 38.4ps min, 25.6ps max; typ from 0 V to 0.244 V
|   falling waveform, R_fixture 50.000, V_fixture 1.100: 20-80 % time 39.2ps typ, 50.1ps min, 32ps max; typ from 1.1 V to 0.514 V
|   falling waveform, R_fixture 50.000, V_fixture 0.0: 20-80 % time 32.5ps typ, 51ps min, 27.7ps max; typ from 0.244 V to 0 V
[Pulldown]
|Voltage   I(typ)   I(min)   I(max)
-1.1V     -16.13mA   -19.15mA   -13.03mA
-964mV    -15.68mA   -19.06mA   -12.9mA
-692mV    -15.37mA   -17.49mA   -13.34mA
-556mV    -14.7mA    -15.89mA   -13.53mA
-454mV    -13.2mA    -13.69mA   -12.73mA
-318mV    -9.609mA   -9.745mA   -9.529mA
158mV     4.492mA    4.453mA    4.512mA
328mV     8.568mA    8.368mA    8.576mA
498mV     11.5mA     10.93mA    11.48mA
668mV     13.1mA     12.21mA    13.05mA
940mV     14.4mA     13.35mA    14.28mA
2.2V      17.63mA    16.52mA    17.16mA
[Pullup]
|Voltage   I(typ)   I(min)   I(max)
-1.1V     1nA        5.218nA    0A
296mV     -5.896uA   -7.058uA   -3.281uA
466mV     -309.5uA   -304uA     -258.1uA
602mV     -1.45mA    -1.529mA   -1.298mA
738mV     -3.167mA   -3.489mA   -2.817mA
976mV     -6.74mA    -7.622mA   -5.938mA
1.35V     -12.91mA   -14.73mA   -11.38mA
1.452V    -13.99mA   -16.01mA   -12.68mA
1.554V    -14.09mA   -16.39mA   -12.95mA
1.724V    -13.73mA   -16.31mA   -12.2mA
1.928V    -13.51mA   -16.17mA   -11.82mA
2.2V      -13.23mA   -15.37mA   -11.51mA
[GND_clamp]
|Voltage   I(typ)   I(min)   I(max)
-1.1V     -92.78mA   -80.14mA   -109.5mA
-1.031V   -81.73mA   -68.77mA   -97.17mA
-939mV    -68.18mA   -56.07mA   -81.64mA
-801mV    -48.85mA   -39.25mA   -59.15mA
-663mV    -30.71mA   -23.84mA   -37.89mA
-571mV    -19.76mA   -14.75mA   -24.85mA
-479mV    -10.5mA    -7.415mA   -13.5mA
-410mV    -5.313mA   -3.546mA   -6.916mA
-341mV    -2.007mA   -1.262mA   -2.59mA
-272mV    -506.9uA   -323.5uA   -609.8uA
-180mV    -45.65uA   -36.06uA   -43.55uA
1.1V      0A         0A         0A
[POWER_clamp]
|Voltage   I(typ)   I(min)   I(max)
-1.1V     5.691mA    8.066mA    3.44mA
-1.062V   3.709mA    5.665mA    2.092mA
-1.039V   2.781mA    4.457mA    1.546mA
-1.016V   2.086mA    3.48mA     1.193mA
-993mV    1.578mA    2.707mA    966.5uA
-970mV    1.21mA     2.107mA    818.5uA
-924mV    750.8uA    1.296mA    641.3uA
-878mV    507uA      821.4uA    530.2uA
-809mV    327.4uA    430uA      403.3uA
-694mV    178.4uA    161uA      233uA
-464mV    19.89uA    15.19uA    23.61uA
1.1V      0A         0A         0A
[Ramp]
| variable   typ   min   max
dV/dt_r   0.146/31.350p   0.145/38.536p   0.153/25.549p
dV/dt_f   0.351/39.417p   0.331/50.191p   0.366/32.077p
R_load = 50.000
[Rising Waveform]
R_fixture= 50.000
V_fixture= 1.100
V_fixture_min= 1.060
V_fixture_max= 1.170
|time   V(typ)   V(min)   V(max)
0s        514.4mV    508.1mV    560.3mV
149ps     515.2mV    508.8mV    564.3mV
208ps     526.4mV    507.6mV    955.2mV
272ps     911.3mV    494.9mV    1.114V
286ps     958.7mV    532.5mV    1.127V
309ps     1.013V     673mV      1.142V
361ps     1.071V     918.1mV    1.161V
424ps     1.09V      1.021V     1.168V
517ps     1.098V     1.053V     1.17V
3ns       1.1V       1.06V      1.17V
[Rising Waveform]
R_fixture= 50.000
V_fixture= 0.0
V_fixture_min= 0.0
V_fixture_max= 0.0
|time   V(typ)   V(min)   V(max)
0s        2.608uV    4.994uV    615.8nV
152ps     222.7uV    14.08uV    5.22mV
192ps     393.8uV    104.2uV    212.9mV
217ps     5.99mV     452.1uV    292.4mV
265ps     206.6mV    70.53uV    336.1mV
302ps     277.7mV    16.92mV    283.7mV
374ps     298.5mV    240.6mV    257mV
487ps     244.5mV    281.8mV    255.1mV
589ps     243.9mV    241.7mV    255mV
3ns       243.9mV    241.2mV    255mV
[Falling Waveform]
R_fixture= 50.000
V_fixture= 1.100
V_fixture_min= 1.060
V_fixture_max= 1.170
|time   V(typ)   V(min)   V(max)
0s        1.1V       1.06V      1.17V
158ps     1.1V       1.06V      1.169V
225ps     1.096V     1.06V      552.8mV
273ps     698.3mV    1.061V     445.9mV
314ps     488.1mV    1.058V     520mV
339ps     449.1mV    945.4mV    542.6mV
411ps     478.5mV    529.8mV    558.4mV
493ps     512mV      438.1mV    560.1mV
671ps     514.4mV    507.2mV    560.3mV
3ns       514.4mV    508.1mV    560.3mV
[Falling Waveform]
R_fixture= 50.000
V_fixture= 0.0
V_fixture_min= 0.0
V_fixture_max= 0.0
|time   V(typ)   V(min)   V(max)
0s        243.9mV    241.2mV    255mV
147ps     243.8mV    240.8mV    257.9mV
182ps     252.8mV    240.5mV    76.83mV
199ps     250.8mV    241.5mV    28.78mV
220ps     200.2mV    245.7mV    8.42mV
254ps     47.92mV    254.5mV    1.467mV
293ps     6.459mV    184.7mV    -5.851mV
353ps     537.7uV    28.29mV    -372.5uV
423ps     -2.494mV   1.369mV    -5.173uV
3ns       517.9nV    3.558uV    160.3nV
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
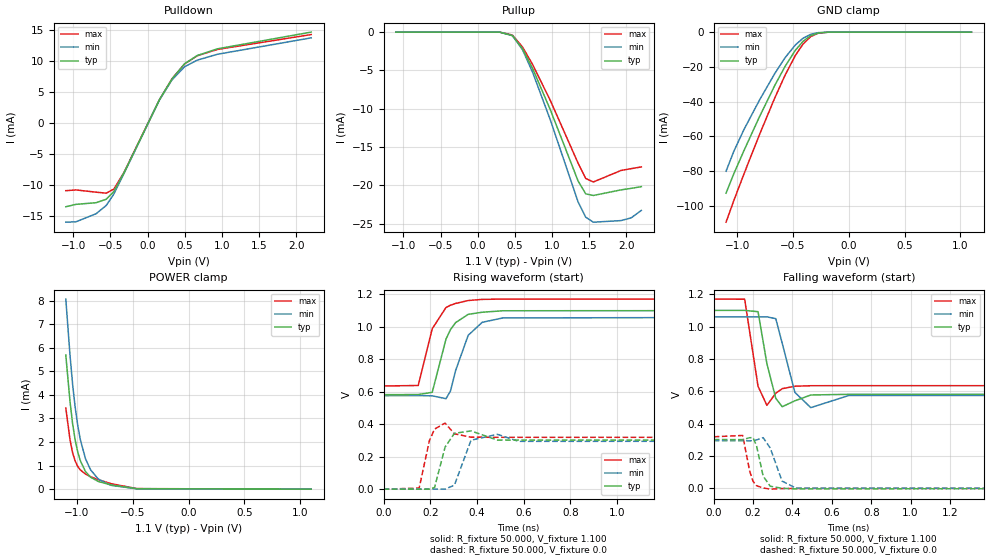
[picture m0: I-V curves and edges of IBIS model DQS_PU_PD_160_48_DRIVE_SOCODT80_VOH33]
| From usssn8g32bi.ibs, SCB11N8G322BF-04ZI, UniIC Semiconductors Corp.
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|   Model DQS_PU_PD_160_48_DRIVE_SOCODT80_VOH33
[Model] DQS_PU_PD_160_48_DRIVE_SOCODT80_VOH33
Model_type I/O
Polarity   Inverting
Vinl =  98.000mV
Vinh =  0.268V
Vmeas =  0.183V
Rref =  50.000
Vref =  0.183V
C_comp   1.020pF   1.010pF   1.030pF
[Model Spec]
Vinh   0.268V   0.262V   0.280V
Vinl   98.000mV   92.000mV   0.110V
Vmeas   0.183V   0.177V   0.195V
Vref   0.183V   0.177V   0.195V
Rref   50.000   NA   NA
[Temperature Range]   25.000   85.000   -40.000
[Voltage Range]   1.100V   1.060V   1.170V
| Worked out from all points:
|   slope of the pulldown table from 0 to 0.165 V, typ, clamps not added: 42.3 ohm
|   GND clamp passes 1 mA (typ) near -0.30 V on its own axis
|   POWER clamp passes 1 mA (typ) near -0.95 V on its own axis
|   rising waveform, R_fixture 50.000, V_fixture 1.100: 20-80 % time 68.5ps typ, 70.8ps min, 66.3ps max; typ from 0.582 V to 1.1 V
|   rising waveform, R_fixture 50.000, V_fixture 0.0: 20-80 % time 29.1ps typ, 35.8ps min, 23.7ps max; typ from 0 V to 0.302 V
|   falling waveform, R_fixture 50.000, V_fixture 1.100: 20-80 % time 41.1ps typ, 52.1ps min, 33.2ps max; typ from 1.1 V to 0.582 V
|   falling waveform, R_fixture 50.000, V_fixture 0.0: 20-80 % time 33.9ps typ, 50.1ps min, 29.5ps max; typ from 0.302 V to 0 V
[Pulldown]
|Voltage   I(typ)   I(min)   I(max)
-1.1V     -13.51mA   -16mA      -10.91mA
-964mV    -13.12mA   -15.94mA   -10.79mA
-692mV    -12.85mA   -14.63mA   -11.15mA
-556mV    -12.29mA   -13.29mA   -11.31mA
-454mV    -11.04mA   -11.45mA   -10.65mA
-318mV    -8.03mA    -8.142mA   -7.964mA
158mV     3.751mA    3.718mA    3.768mA
328mV     7.153mA    6.985mA    7.158mA
498mV     9.598mA    9.123mA    9.581mA
668mV     10.93mA    10.18mA    10.89mA
940mV     12.01mA    11.13mA    11.91mA
2.2V      14.71mA    13.78mA    14.31mA
[Pullup]
|Voltage   I(typ)   I(min)   I(max)
-1.1V     1.606nA    7.718nA    0A
296mV     -8.845uA   -10.59uA   -4.922uA
466mV     -464.7uA   -456.5uA   -387.5uA
602mV     -2.18mA    -2.299mA   -1.951mA
738mV     -4.764mA   -5.249mA   -4.236mA
976mV     -10.14mA   -11.47mA   -8.932mA
1.35V     -19.45mA   -22.19mA   -17.13mA
1.452V    -21.12mA   -24.17mA   -19.11mA
1.554V    -21.33mA   -24.82mA   -19.57mA
1.928V    -20.6mA    -24.61mA   -18.06mA
2.064V    -20.4mA    -24.25mA   -17.83mA
2.2V      -20.18mA   -23.28mA   -17.6mA
[GND_clamp]
|Voltage   I(typ)   I(min)   I(max)
-1.1V     -92.78mA   -80.14mA   -109.5mA
-1.031V   -81.73mA   -68.77mA   -97.17mA
-939mV    -68.18mA   -56.07mA   -81.64mA
-801mV    -48.85mA   -39.25mA   -59.15mA
-663mV    -30.71mA   -23.84mA   -37.89mA
-571mV    -19.76mA   -14.75mA   -24.85mA
-479mV    -10.5mA    -7.415mA   -13.5mA
-410mV    -5.313mA   -3.546mA   -6.916mA
-341mV    -2.007mA   -1.262mA   -2.59mA
-272mV    -506.9uA   -323.5uA   -609.8uA
-180mV    -45.65uA   -36.06uA   -43.55uA
1.1V      0A         0A         0A
[POWER_clamp]
|Voltage   I(typ)   I(min)   I(max)
-1.1V     5.691mA    8.066mA    3.44mA
-1.062V   3.709mA    5.665mA    2.092mA
-1.039V   2.781mA    4.457mA    1.546mA
-1.016V   2.086mA    3.48mA     1.193mA
-993mV    1.578mA    2.707mA    966.5uA
-970mV    1.21mA     2.107mA    818.5uA
-924mV    750.8uA    1.296mA    641.3uA
-878mV    507uA      821.4uA    530.2uA
-809mV    327.4uA    430uA      403.3uA
-694mV    178.4uA    161uA      233uA
-464mV    19.89uA    15.19uA    23.61uA
1.1V      0A         0A         0A
[Ramp]
| variable   typ   min   max
dV/dt_r   0.181/29.058p   0.177/35.944p   0.192/23.828p
dV/dt_f   0.311/41.295p   0.291/52.270p   0.321/33.258p
R_load = 50.000
[Rising Waveform]
R_fixture= 50.000
V_fixture= 1.100
V_fixture_min= 1.060
V_fixture_max= 1.170
|time   V(typ)   V(min)   V(max)
0s        581.6mV    575.3mV    635mV
148ps     582.3mV    575.9mV    638.1mV
208ps     596.2mV    574.5mV    987.6mV
267ps     923.9mV    556.8mV    1.118V
286ps     981.5mV    604mV      1.132V
308ps     1.025V     729.6mV    1.143V
362ps     1.076V     946.9mV    1.161V
422ps     1.089V     1.027V     1.168V
511ps     1.098V     1.054V     1.17V
3ns       1.1V       1.06V      1.17V
[Rising Waveform]
R_fixture= 50.000
V_fixture= 0.0
V_fixture_min= 0.0
V_fixture_max= 0.0
|time   V(typ)   V(min)   V(max)
0s        2.898uV    5.55uV     684.5nV
152ps     91.82uV    20.55uV    6.559mV
196ps     379.1uV    84.81uV    299.2mV
218ps     10.32mV    271.4uV    369.7mV
263ps     258.7mV    237.8uV    406.7mV
303ps     343.8mV    24.64mV    340.7mV
374ps     358.5mV    301.1mV    319.9mV
487ps     302.1mV    337.5mV    319.2mV
578ps     302.1mV    294.3mV    319.2mV
3ns       302.1mV    295.1mV    319.2mV
[Falling Waveform]
R_fixture= 50.000
V_fixture= 1.100
V_fixture_min= 1.060
V_fixture_max= 1.170
|time   V(typ)   V(min)   V(max)
0s        1.1V       1.06V      1.17V
157ps     1.1V       1.06V      1.169V
225ps     1.092V     1.06V      630.9mV
270ps     770.6mV    1.06V      513.5mV
315ps     556.8mV    1.049V     588.5mV
348ps     504.9mV    896mV      616.4mV
412ps     541.4mV    593.9mV    631.6mV
493ps     577.4mV    499.3mV    634.6mV
686ps     581.5mV    574.2mV    635mV
3ns       581.6mV    575.3mV    635mV
[Falling Waveform]
R_fixture= 50.000
V_fixture= 0.0
V_fixture_min= 0.0
V_fixture_max= 0.0
|time   V(typ)   V(min)   V(max)
0s        302.1mV    295.1mV    319.2mV
147ps     301.6mV    294.7mV    327.4mV
182ps     313.4mV    294.1mV    109.6mV
199ps     314.2mV    295.2mV    44.9mV
217ps     265.7mV    299.6mV    17.3mV
251ps     75.96mV    313.7mV    3.109mV
287ps     13.72mV    249.6mV    -4.393mV
347ps     1.013mV    45.53mV    -561.1uV
417ps     -2.718mV   2.451mV    -15.01uV
3ns       -1.2uV     5.398uV    87.87nV
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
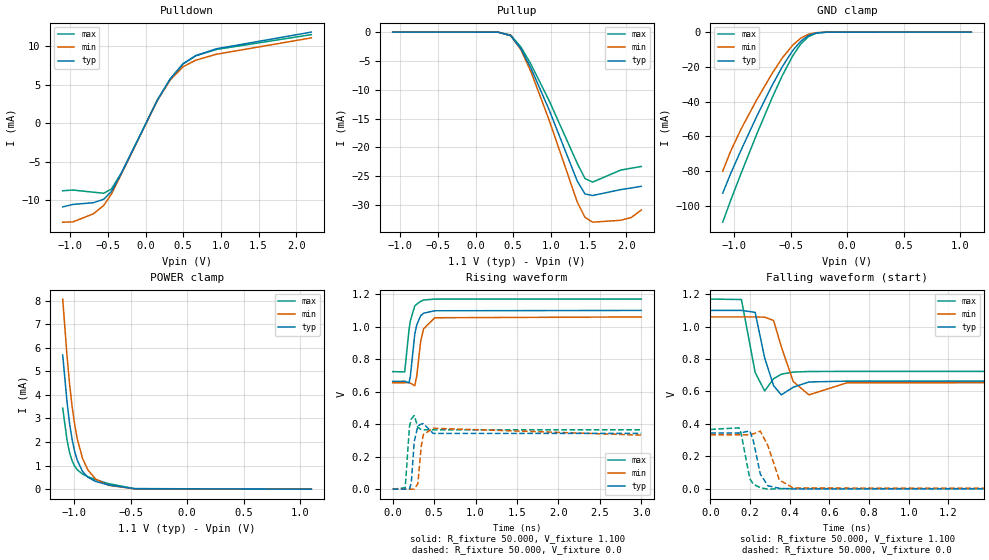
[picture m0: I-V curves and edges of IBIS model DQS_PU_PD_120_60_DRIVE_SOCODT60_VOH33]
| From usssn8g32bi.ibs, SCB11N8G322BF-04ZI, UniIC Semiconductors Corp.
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|   Model DQS_PU_PD_120_60_DRIVE_SOCODT60_VOH33
[Model] DQS_PU_PD_120_60_DRIVE_SOCODT60_VOH33
Model_type I/O
Polarity   Inverting
Vinl =  98.000mV
Vinh =  0.268V
Vmeas =  0.183V
Rref =  50.000
Vref =  0.183V
C_comp   1.020pF   1.010pF   1.030pF
[Model Spec]
Vinh   0.268V   0.262V   0.280V
Vinl   98.000mV   92.000mV   0.110V
Vmeas   0.183V   0.177V   0.195V
Vref   0.183V   0.177V   0.195V
Rref   50.000   NA   NA
[Temperature Range]   25.000   85.000   -40.000
[Voltage Range]   1.100V   1.060V   1.170V
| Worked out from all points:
|   slope of the pulldown table from 0 to 0.165 V, typ, clamps not added: 52.7 ohm
|   GND clamp passes 1 mA (typ) near -0.30 V on its own axis
|   POWER clamp passes 1 mA (typ) near -0.95 V on its own axis
|   rising waveform, R_fixture 50.000, V_fixture 1.100: 20-80 % time 67.4ps typ, 69ps min, 65.7ps max; typ from 0.663 V to 1.1 V
|   rising waveform, R_fixture 50.000, V_fixture 0.0: 20-80 % time 27.7ps typ, 34.3ps min, 22.6ps max; typ from 0 V to 0.343 V
|   falling waveform, R_fixture 50.000, V_fixture 1.100: 20-80 % time 42.8ps typ, 54.1ps min, 34.1ps max; typ from 1.1 V to 0.663 V
|   falling waveform, R_fixture 50.000, V_fixture 0.0: 20-80 % time 37.8ps typ, 52.1ps min, 33.2ps max; typ from 0.343 V to 0 V
[Pulldown]
|Voltage   I(typ)   I(min)   I(max)
-1.1V     -10.83mA   -12.81mA   -8.746mA
-964mV    -10.51mA   -12.77mA   -8.65mA
-692mV    -10.29mA   -11.72mA   -8.932mA
-556mV    -9.849mA   -10.65mA   -9.063mA
-454mV    -8.849mA   -9.178mA   -8.534mA
-318mV    -6.436mA   -6.525mA   -6.383mA
158mV     3.005mA    2.979mA    3.019mA
328mV     5.729mA    5.594mA    5.734mA
498mV     7.686mA    7.305mA    7.672mA
668mV     8.751mA    8.153mA    8.715mA
940mV     9.618mA    8.913mA    9.532mA
2.2V      11.78mA    11.03mA    11.45mA
[Pullup]
|Voltage   I(typ)   I(min)   I(max)
-1.1V     2.106nA    10.33nA    0A
296mV     -11.79uA   -14.12uA   -6.562uA
466mV     -619.2uA   -608.2uA   -516.4uA
602mV     -2.903mA   -3.06mA    -2.598mA
738mV     -6.341mA   -6.984mA   -5.639mA
976mV     -13.49mA   -15.26mA   -11.89mA
1.35V     -25.87mA   -29.51mA   -22.79mA
1.452V    -28.09mA   -32.14mA   -25.42mA
1.554V    -28.36mA   -32.99mA   -26.03mA
1.928V    -27.33mA   -32.66mA   -23.94mA
2.064V    -27.06mA   -32.19mA   -23.63mA
2.2V      -26.76mA   -30.87mA   -23.32mA
[GND_clamp]
|Voltage   I(typ)   I(min)   I(max)
-1.1V     -92.78mA   -80.14mA   -109.5mA
-1.031V   -81.73mA   -68.77mA   -97.17mA
-939mV    -68.18mA   -56.07mA   -81.64mA
-801mV    -48.85mA   -39.25mA   -59.15mA
-663mV    -30.71mA   -23.84mA   -37.89mA
-571mV    -19.76mA   -14.75mA   -24.85mA
-479mV    -10.5mA    -7.415mA   -13.5mA
-410mV    -5.313mA   -3.546mA   -6.916mA
-341mV    -2.007mA   -1.262mA   -2.59mA
-272mV    -506.9uA   -323.5uA   -609.8uA
-180mV    -45.65uA   -36.06uA   -43.55uA
1.1V      0A         0A         0A
[POWER_clamp]
|Voltage   I(typ)   I(min)   I(max)
-1.1V     5.691mA    8.066mA    3.44mA
-1.062V   3.709mA    5.665mA    2.092mA
-1.039V   2.781mA    4.457mA    1.546mA
-1.016V   2.086mA    3.48mA     1.193mA
-993mV    1.578mA    2.707mA    966.5uA
-970mV    1.21mA     2.107mA    818.5uA
-924mV    750.8uA    1.296mA    641.3uA
-878mV    507uA      821.4uA    530.2uA
-809mV    327.4uA    430uA      403.3uA
-694mV    178.4uA    161uA      233uA
-464mV    19.89uA    15.19uA    23.61uA
1.1V      0A         0A         0A
[Ramp]
| variable   typ   min   max
dV/dt_r   0.206/27.799p   0.200/34.338p   0.219/22.685p
dV/dt_f   0.262/42.819p   0.243/54.044p   0.268/34.109p
R_load = 50.000
[Rising Waveform]
R_fixture= 50.000
V_fixture= 1.100
V_fixture_min= 1.060
V_fixture_max= 1.170
|time   V(typ)   V(min)   V(max)
0s        663.5mV    654.8mV    723.5mV
145ps     664.4mV    655.2mV    721.8mV
197ps     654.4mV    655.8mV    982.1mV
213ps     694.8mV    652.8mV    1.036V
266ps     952.8mV    636.5mV    1.127V
290ps     1.011V     694.7mV    1.139V
337ps     1.067V     908.7mV    1.156V
372ps     1.083V     986.2mV    1.164V
507ps     1.098V     1.055V     1.17V
3ns       1.1V       1.06V      1.17V
[Rising Waveform]
R_fixture= 50.000
V_fixture= 0.0
V_fixture_min= 0.0
V_fixture_max= 0.0
|time   V(typ)   V(min)   V(max)
0s        3.261uV    6.245uV    770.5nV
151ps     -66.82uV   34.5uV     8.489mV
202ps     2.074mV    -15.29uV   383.3mV
224ps     38.23mV    48.99uV    431.6mV
260ps     292.5mV    476.5uV    453.2mV
303ps     388.4mV    32.26mV    381.1mV
344ps     401.1mV    262.1mV    366.2mV
370ps     402.7mV    336.7mV    365.4mV
489ps     343mV      374.9mV    365.2mV
3ns       343.2mV    332.5mV    365.2mV
[Falling Waveform]
R_fixture= 50.000
V_fixture= 1.100
V_fixture_min= 1.060
V_fixture_max= 1.170
|time   V(typ)   V(min)   V(max)
0s        1.1V       1.06V      1.17V
157ps     1.1V       1.06V      1.167V
226ps     1.088V     1.06V      717.9mV
274ps     806.8mV    1.058V     602.6mV
319ps     635.2mV    1.038V     678.1mV
358ps     578.6mV    875.4mV    706.2mV
418ps     625.7mV    661mV      719.4mV
497ps     658.1mV    578.6mV    722.9mV
689ps     663.4mV    653.3mV    723.5mV
3ns       663.5mV    654.8mV    723.5mV
[Falling Waveform]
R_fixture= 50.000
V_fixture= 0.0
V_fixture_min= 0.0
V_fixture_max= 0.0
|time   V(typ)   V(min)   V(max)
0s        343.2mV    332.5mV    365.2mV
145ps     342.6mV    332mV      375mV
155ps     344.5mV    331.7mV    343mV
199ps     355.9mV    332.7mV    62.15mV
217ps     295.1mV    337.9mV    26.83mV
252ps     90.25mV    354.8mV    5.421mV
290ps     17.82mV    266.1mV    -3.505mV
348ps     1.679mV    53.06mV    -522.7uV
419ps     -2.146mV   3.467mV    -21.92uV
3ns       -306.2nV   4.92uV     515.9nV
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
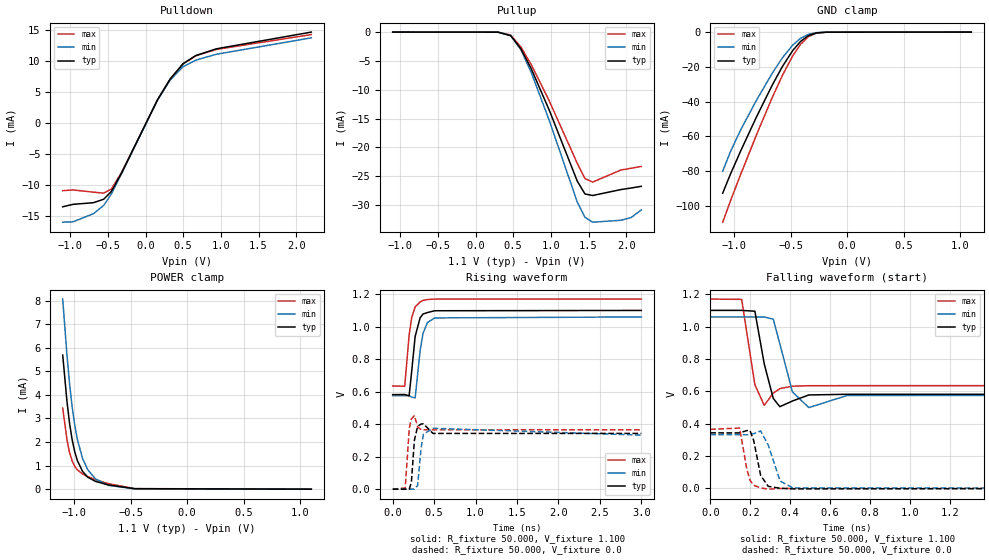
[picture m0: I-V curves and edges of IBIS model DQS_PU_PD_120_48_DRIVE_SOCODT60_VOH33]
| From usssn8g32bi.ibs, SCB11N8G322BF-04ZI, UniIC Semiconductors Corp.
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|   Model DQS_PU_PD_120_48_DRIVE_SOCODT60_VOH33
[Model] DQS_PU_PD_120_48_DRIVE_SOCODT60_VOH33
Model_type I/O
Polarity   Inverting
Vinl =  98.000mV
Vinh =  0.268V
Vmeas =  0.183V
Rref =  50.000
Vref =  0.183V
C_comp   1.020pF   1.010pF   1.030pF
[Model Spec]
Vinh   0.268V   0.262V   0.280V
Vinl   98.000mV   92.000mV   0.110V
Vmeas   0.183V   0.177V   0.195V
Vref   0.183V   0.177V   0.195V
Rref   50.000   NA   NA
[Temperature Range]   25.000   85.000   -40.000
[Voltage Range]   1.100V   1.060V   1.170V
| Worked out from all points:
|   slope of the pulldown table from 0 to 0.165 V, typ, clamps not added: 42.3 ohm
|   GND clamp passes 1 mA (typ) near -0.30 V on its own axis
|   POWER clamp passes 1 mA (typ) near -0.95 V on its own axis
|   rising waveform, R_fixture 50.000, V_fixture 1.100: 20-80 % time 68.1ps typ, 70ps min, 66.2ps max; typ from 0.582 V to 1.1 V
|   rising waveform, R_fixture 50.000, V_fixture 0.0: 20-80 % time 27.6ps typ, 34.1ps min, 22.5ps max; typ from 0 V to 0.343 V
|   falling waveform, R_fixture 50.000, V_fixture 1.100: 20-80 % time 41.3ps typ, 52.6ps min, 33.2ps max; typ from 1.1 V to 0.582 V
|   falling waveform, R_fixture 50.000, V_fixture 0.0: 20-80 % time 34.3ps typ, 49.9ps min, 29.7ps max; typ from 0.343 V to 0 V
[Pulldown]
|Voltage   I(typ)   I(min)   I(max)
-1.1V     -13.51mA   -16mA      -10.91mA
-964mV    -13.12mA   -15.94mA   -10.79mA
-692mV    -12.85mA   -14.63mA   -11.15mA
-556mV    -12.29mA   -13.29mA   -11.31mA
-454mV    -11.04mA   -11.45mA   -10.65mA
-318mV    -8.03mA    -8.142mA   -7.964mA
158mV     3.751mA    3.718mA    3.768mA
328mV     7.153mA    6.985mA    7.158mA
498mV     9.598mA    9.123mA    9.581mA
668mV     10.93mA    10.18mA    10.89mA
940mV     12.01mA    11.13mA    11.91mA
2.2V      14.71mA    13.78mA    14.31mA
[Pullup]
|Voltage   I(typ)   I(min)   I(max)
-1.1V     2.106nA    10.33nA    0A
296mV     -11.79uA   -14.12uA   -6.562uA
466mV     -619.2uA   -608.2uA   -516.4uA
602mV     -2.903mA   -3.06mA    -2.598mA
738mV     -6.341mA   -6.984mA   -5.639mA
976mV     -13.49mA   -15.26mA   -11.89mA
1.35V     -25.87mA   -29.51mA   -22.79mA
1.452V    -28.09mA   -32.14mA   -25.42mA
1.554V    -28.36mA   -32.99mA   -26.03mA
1.928V    -27.33mA   -32.66mA   -23.94mA
2.064V    -27.06mA   -32.19mA   -23.63mA
2.2V      -26.76mA   -30.87mA   -23.32mA
[GND_clamp]
|Voltage   I(typ)   I(min)   I(max)
-1.1V     -92.78mA   -80.14mA   -109.5mA
-1.031V   -81.73mA   -68.77mA   -97.17mA
-939mV    -68.18mA   -56.07mA   -81.64mA
-801mV    -48.85mA   -39.25mA   -59.15mA
-663mV    -30.71mA   -23.84mA   -37.89mA
-571mV    -19.76mA   -14.75mA   -24.85mA
-479mV    -10.5mA    -7.415mA   -13.5mA
-410mV    -5.313mA   -3.546mA   -6.916mA
-341mV    -2.007mA   -1.262mA   -2.59mA
-272mV    -506.9uA   -323.5uA   -609.8uA
-180mV    -45.65uA   -36.06uA   -43.55uA
1.1V      0A         0A         0A
[POWER_clamp]
|Voltage   I(typ)   I(min)   I(max)
-1.1V     5.691mA    8.066mA    3.44mA
-1.062V   3.709mA    5.665mA    2.092mA
-1.039V   2.781mA    4.457mA    1.546mA
-1.016V   2.086mA    3.48mA     1.193mA
-993mV    1.578mA    2.707mA    966.5uA
-970mV    1.21mA     2.107mA    818.5uA
-924mV    750.8uA    1.296mA    641.3uA
-878mV    507uA      821.4uA    530.2uA
-809mV    327.4uA    430uA      403.3uA
-694mV    178.4uA    161uA      233uA
-464mV    19.89uA    15.19uA    23.61uA
1.1V      0A         0A         0A
[Ramp]
| variable   typ   min   max
dV/dt_r   0.206/27.771p   0.200/34.099p   0.219/22.665p
dV/dt_f   0.311/41.415p   0.291/52.561p   0.321/33.405p
R_load = 50.000
[Rising Waveform]
R_fixture= 50.000
V_fixture= 1.100
V_fixture_min= 1.060
V_fixture_max= 1.170
|time   V(typ)   V(min)   V(max)
0s        581.6mV    575.3mV    635mV
145ps     582.6mV    575.8mV    633.5mV
198ps     573.8mV    576.3mV    947.4mV
229ps     725.1mV    566.6mV    1.055V
271ps     940.6mV    561.8mV    1.122V
331ps     1.055V     853.6mV    1.152V
366ps     1.078V     958.6mV    1.162V
418ps     1.087V     1.025V     1.167V
507ps     1.098V     1.054V     1.17V
3ns       1.1V       1.06V      1.17V
[Rising Waveform]
R_fixture= 50.000
V_fixture= 0.0
V_fixture_min= 0.0
V_fixture_max= 0.0
|time   V(typ)   V(min)   V(max)
0s        2.898uV    5.55uV     684.5nV
151ps     17.73uV    28.38uV    7.306mV
200ps     1.071mV    61.26uV    374.9mV
225ps     41.26mV    205.9uV    432.3mV
262ps     301.5mV    327.3uV    453.3mV
301ps     387.1mV    23.37mV    383.2mV
343ps     400.8mV    256.4mV    366.3mV
371ps     402mV      338.1mV    365.3mV
486ps     343mV      374.6mV    365.2mV
3ns       343.2mV    332.5mV    365.2mV
[Falling Waveform]
R_fixture= 50.000
V_fixture= 1.100
V_fixture_min= 1.060
V_fixture_max= 1.170
|time   V(typ)   V(min)   V(max)
0s        1.1V       1.06V      1.17V
157ps     1.1V       1.06V      1.168V
223ps     1.095V     1.06V      640.6mV
270ps     769.1mV    1.059V     513.4mV
315ps     556.4mV    1.046V     588.5mV
348ps     504.9mV    893.6mV    616.4mV
411ps     540.1mV    596.1mV    631.5mV
493ps     577.4mV    499.2mV    634.6mV
684ps     581.5mV    574.1mV    635mV
3ns       581.6mV    575.3mV    635mV
[Falling Waveform]
R_fixture= 50.000
V_fixture= 0.0
V_fixture_min= 0.0
V_fixture_max= 0.0
|time   V(typ)   V(min)   V(max)
0s        343.2mV    332.5mV    365.2mV
147ps     342.8mV    332mV      372.9mV
183ps     357.6mV    331.3mV    116.3mV
199ps     356.7mV    332.7mV    50.04mV
217ps     297mV      337.8mV    19.2mV
252ps     80.23mV    354.7mV    3.227mV
290ps     12.79mV    267.8mV    -4.737mV
349ps     992.3uV    45.87mV    -502uV
413ps     -3.049mV   3.093mV    -18.54uV
3ns       -1.038uV   5.396uV    257.9nV
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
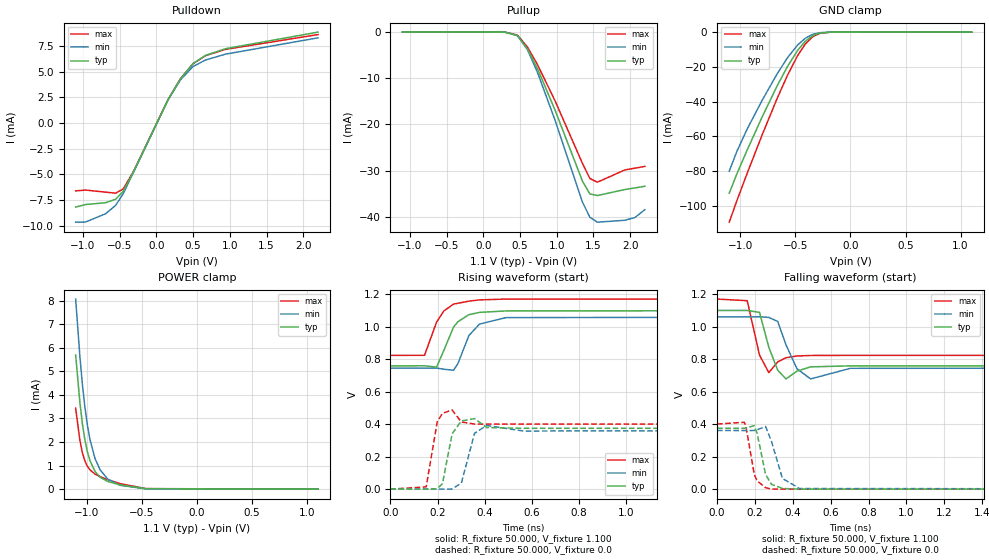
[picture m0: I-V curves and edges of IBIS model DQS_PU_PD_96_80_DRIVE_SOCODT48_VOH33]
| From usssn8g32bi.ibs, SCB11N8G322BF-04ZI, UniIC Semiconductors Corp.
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|   Model DQS_PU_PD_96_80_DRIVE_SOCODT48_VOH33
[Model] DQS_PU_PD_96_80_DRIVE_SOCODT48_VOH33
Model_type I/O
Polarity   Inverting
Vinl =  98.000mV
Vinh =  0.268V
Vmeas =  0.183V
Rref =  50.000
Vref =  0.183V
C_comp   1.020pF   1.010pF   1.030pF
[Model Spec]
Vinh   0.268V   0.262V   0.280V
Vinl   98.000mV   92.000mV   0.110V
Vmeas   0.183V   0.177V   0.195V
Vref   0.183V   0.177V   0.195V
Rref   50.000   NA   NA
[Temperature Range]   25.000   85.000   -40.000
[Voltage Range]   1.100V   1.060V   1.170V
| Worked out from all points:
|   slope of the pulldown table from 0 to 0.165 V, typ, clamps not added: 70.2 ohm
|   GND clamp passes 1 mA (typ) near -0.30 V on its own axis
|   POWER clamp passes 1 mA (typ) near -0.95 V on its own axis
|   rising waveform, R_fixture 50.000, V_fixture 1.100: 20-80 % time 65.6ps typ, 65.7ps min, 64.8ps max; typ from 0.759 V to 1.1 V
|   rising waveform, R_fixture 50.000, V_fixture 0.0: 20-80 % time 26.8ps typ, 33.7ps min, 21.6ps max; typ from 0 V to 0.374 V
|   falling waveform, R_fixture 50.000, V_fixture 1.100: 20-80 % time 44.1ps typ, 55.7ps min, 34.8ps max; typ from 1.1 V to 0.759 V
|   falling waveform, R_fixture 50.000, V_fixture 0.0: 20-80 % time 42ps typ, 54ps min, 37.8ps max; typ from 0.374 V to 0 V
[Pulldown]
|Voltage   I(typ)   I(min)   I(max)
-1.1V     -8.193mA   -9.666mA   -6.618mA
-964mV    -7.945mA   -9.646mA   -6.54mA
-692mV    -7.769mA   -8.844mA   -6.742mA
-556mV    -7.432mA   -8.032mA   -6.841mA
-454mV    -6.673mA   -6.916mA   -6.44mA
-318mV    -4.841mA   -4.906mA   -4.804mA
158mV     2.257mA    2.237mA    2.267mA
328mV     4.302mA    4.2mA      4.305mA
498mV     5.77mA     5.483mA    5.759mA
668mV     6.567mA    6.118mA    6.54mA
940mV     7.217mA    6.688mA    7.152mA
2.2V      8.836mA    8.278mA    8.595mA
[Pullup]
|Voltage   I(typ)   I(min)   I(max)
-1.1V     2.6nA      12.94nA    0A
296mV     -14.74uA   -17.65uA   -8.203uA
466mV     -773.5uA   -759.8uA   -645.2uA
602mV     -3.625mA   -3.82mA    -3.244mA
738mV     -7.914mA   -8.716mA   -7.039mA
976mV     -16.84mA   -19.04mA   -14.84mA
1.35V     -32.28mA   -36.82mA   -28.44mA
1.452V    -35.08mA   -40.12mA   -31.74mA
1.554V    -35.42mA   -41.2mA    -32.53mA
1.928V    -34.12mA   -40.78mA   -29.88mA
2.064V    -33.78mA   -40.2mA    -29.49mA
2.2V      -33.41mA   -38.49mA   -29.11mA
[GND_clamp]
|Voltage   I(typ)   I(min)   I(max)
-1.1V     -92.78mA   -80.14mA   -109.5mA
-1.031V   -81.73mA   -68.77mA   -97.17mA
-939mV    -68.18mA   -56.07mA   -81.64mA
-801mV    -48.85mA   -39.25mA   -59.15mA
-663mV    -30.71mA   -23.84mA   -37.89mA
-571mV    -19.76mA   -14.75mA   -24.85mA
-479mV    -10.5mA    -7.415mA   -13.5mA
-410mV    -5.313mA   -3.546mA   -6.916mA
-341mV    -2.007mA   -1.262mA   -2.59mA
-272mV    -506.9uA   -323.5uA   -609.8uA
-180mV    -45.65uA   -36.06uA   -43.55uA
1.1V      0A         0A         0A
[POWER_clamp]
|Voltage   I(typ)   I(min)   I(max)
-1.1V     5.691mA    8.066mA    3.44mA
-1.062V   3.709mA    5.665mA    2.092mA
-1.039V   2.781mA    4.457mA    1.546mA
-1.016V   2.086mA    3.48mA     1.193mA
-993mV    1.578mA    2.707mA    966.5uA
-970mV    1.21mA     2.107mA    818.5uA
-924mV    750.8uA    1.296mA    641.3uA
-878mV    507uA      821.4uA    530.2uA
-809mV    327.4uA    430uA      403.3uA
-694mV    178.4uA    161uA      233uA
-464mV    19.89uA    15.19uA    23.61uA
1.1V      0A         0A         0A
[Ramp]
| variable   typ   min   max
dV/dt_r   0.225/26.992p   0.216/33.793p   0.240/21.882p
dV/dt_f   0.205/44.104p   0.189/55.821p   0.208/34.915p
R_load = 50.000
[Rising Waveform]
R_fixture= 50.000
V_fixture= 1.100
V_fixture_min= 1.060
V_fixture_max= 1.170
|time   V(typ)   V(min)   V(max)
0s        758.6mV    744.6mV    823.3mV
145ps     759.3mV    745mV      823.7mV
196ps     751mV      745.3mV    1.028V
227ps     854.3mV    738.1mV    1.097V
268ps     997.8mV    731.9mV    1.139V
286ps     1.03V      771.3mV    1.144V
333ps     1.074V     945.5mV    1.157V
378ps     1.088V     1.016V     1.165V
491ps     1.097V     1.056V     1.17V
3ns       1.1V       1.06V      1.17V
[Rising Waveform]
R_fixture= 50.000
V_fixture= 0.0
V_fixture_min= 0.0
V_fixture_max= 0.0
|time   V(typ)   V(min)   V(max)
0s        3.731uV    7.145uV    881.9nV
152ps     -228.3uV   47.15uV    13.93mV
199ps     2.817mV    -130.9uV   415.6mV
221ps     34.04mV    -221.2uV   466.3mV
262ps     341.1mV    919.3uV    487.2mV
301ps     419.5mV    37.21mV    413.2mV
357ps     434.2mV    343.7mV    400.2mV
408ps     379.2mV    391.6mV    400.4mV
565ps     374.4mV    357.7mV    400.4mV
3ns       374.4mV    360.6mV    400.4mV
[Falling Waveform]
R_fixture= 50.000
V_fixture= 1.100
V_fixture_min= 1.060
V_fixture_max= 1.170
|time   V(typ)   V(min)   V(max)
0s        1.1V       1.06V      1.17V
159ps     1.1V       1.06V      1.16V
224ps     1.088V     1.061V     824.4mV
273ps     873.2mV    1.057V     717.1mV
320ps     731.9mV    1.032V     782.8mV
364ps     678.1mV    887.3mV    808.6mV
422ps     726.3mV    740.4mV    819.4mV
494ps     752.4mV    678mV      822.5mV
704ps     758.5mV    743.5mV    823.3mV
3ns       758.6mV    744.6mV    823.3mV
[Falling Waveform]
R_fixture= 50.000
V_fixture= 0.0
V_fixture_min= 0.0
V_fixture_max= 0.0
|time   V(typ)   V(min)   V(max)
0s        374.4mV    360.6mV    400.4mV
144ps     373.7mV    360mV      410.9mV
154ps     376mV      359.7mV    374.5mV
196ps     390.4mV    360.5mV    91.06mV
211ps     344.2mV    364.8mV    50.14mV
256ps     90.16mV    385.3mV    8.374mV
287ps     28.64mV    293.6mV    -911.7uV
345ps     3.45mV     65.21mV    -377.4uV
435ps     -946.3uV   3.059mV    -11.42uV
3ns       3.551uV    7.02uV     -1.988uV
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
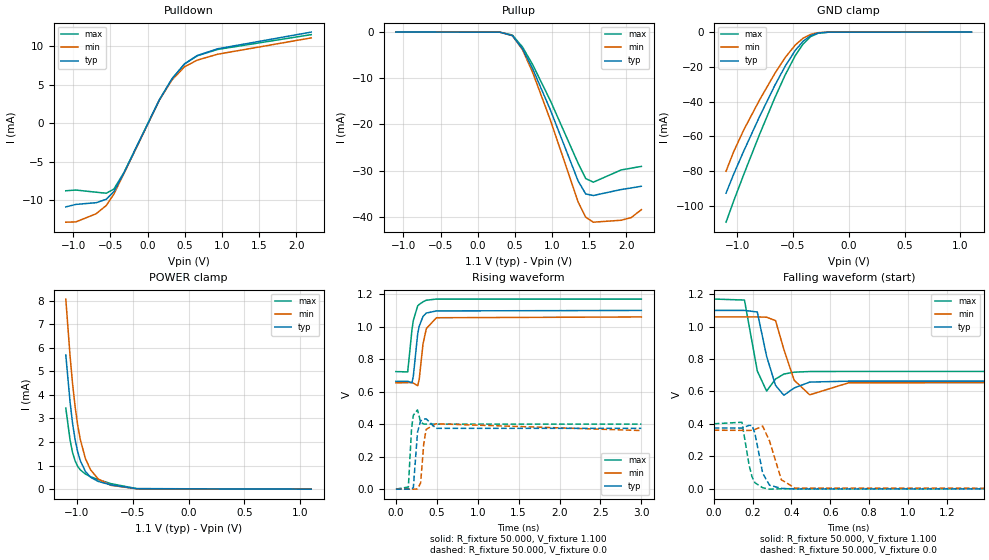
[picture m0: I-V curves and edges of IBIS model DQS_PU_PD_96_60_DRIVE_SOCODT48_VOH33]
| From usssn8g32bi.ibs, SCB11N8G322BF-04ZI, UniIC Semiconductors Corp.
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|   Model DQS_PU_PD_96_60_DRIVE_SOCODT48_VOH33
[Model] DQS_PU_PD_96_60_DRIVE_SOCODT48_VOH33
Model_type I/O
Polarity   Inverting
Vinl =  98.000mV
Vinh =  0.268V
Vmeas =  0.183V
Rref =  50.000
Vref =  0.183V
C_comp   1.020pF   1.010pF   1.030pF
[Model Spec]
Vinh   0.268V   0.262V   0.280V
Vinl   98.000mV   92.000mV   0.110V
Vmeas   0.183V   0.177V   0.195V
Vref   0.183V   0.177V   0.195V
Rref   50.000   NA   NA
[Temperature Range]   25.000   85.000   -40.000
[Voltage Range]   1.100V   1.060V   1.170V
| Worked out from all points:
|   slope of the pulldown table from 0 to 0.165 V, typ, clamps not added: 52.7 ohm
|   GND clamp passes 1 mA (typ) near -0.30 V on its own axis
|   POWER clamp passes 1 mA (typ) near -0.95 V on its own axis
|   rising waveform, R_fixture 50.000, V_fixture 1.100: 20-80 % time 67ps typ, 68.1ps min, 65.5ps max; typ from 0.663 V to 1.1 V
|   rising waveform, R_fixture 50.000, V_fixture 0.0: 20-80 % time 26.7ps typ, 33.5ps min, 21.7ps max; typ from 0 V to 0.374 V
|   falling waveform, R_fixture 50.000, V_fixture 1.100: 20-80 % time 43ps typ, 54.5ps min, 34.2ps max; typ from 1.1 V to 0.663 V
|   falling waveform, R_fixture 50.000, V_fixture 0.0: 20-80 % time 38.3ps typ, 52.6ps min, 33.4ps max; typ from 0.374 V to 0 V
[Pulldown]
|Voltage   I(typ)   I(min)   I(max)
-1.1V     -10.83mA   -12.81mA   -8.746mA
-964mV    -10.51mA   -12.77mA   -8.65mA
-692mV    -10.29mA   -11.72mA   -8.932mA
-556mV    -9.849mA   -10.65mA   -9.063mA
-454mV    -8.849mA   -9.178mA   -8.534mA
-318mV    -6.436mA   -6.525mA   -6.383mA
158mV     3.005mA    2.979mA    3.019mA
328mV     5.729mA    5.594mA    5.734mA
498mV     7.686mA    7.305mA    7.672mA
668mV     8.751mA    8.153mA    8.715mA
940mV     9.618mA    8.913mA    9.532mA
2.2V      11.78mA    11.03mA    11.45mA
[Pullup]
|Voltage   I(typ)   I(min)   I(max)
-1.1V     2.6nA      12.94nA    0A
296mV     -14.74uA   -17.65uA   -8.203uA
466mV     -773.5uA   -759.8uA   -645.2uA
602mV     -3.625mA   -3.82mA    -3.244mA
738mV     -7.914mA   -8.716mA   -7.039mA
976mV     -16.84mA   -19.04mA   -14.84mA
1.35V     -32.28mA   -36.82mA   -28.44mA
1.452V    -35.08mA   -40.12mA   -31.74mA
1.554V    -35.42mA   -41.2mA    -32.53mA
1.928V    -34.12mA   -40.78mA   -29.88mA
2.064V    -33.78mA   -40.2mA    -29.49mA
2.2V      -33.41mA   -38.49mA   -29.11mA
[GND_clamp]
|Voltage   I(typ)   I(min)   I(max)
-1.1V     -92.78mA   -80.14mA   -109.5mA
-1.031V   -81.73mA   -68.77mA   -97.17mA
-939mV    -68.18mA   -56.07mA   -81.64mA
-801mV    -48.85mA   -39.25mA   -59.15mA
-663mV    -30.71mA   -23.84mA   -37.89mA
-571mV    -19.76mA   -14.75mA   -24.85mA
-479mV    -10.5mA    -7.415mA   -13.5mA
-410mV    -5.313mA   -3.546mA   -6.916mA
-341mV    -2.007mA   -1.262mA   -2.59mA
-272mV    -506.9uA   -323.5uA   -609.8uA
-180mV    -45.65uA   -36.06uA   -43.55uA
1.1V      0A         0A         0A
[POWER_clamp]
|Voltage   I(typ)   I(min)   I(max)
-1.1V     5.691mA    8.066mA    3.44mA
-1.062V   3.709mA    5.665mA    2.092mA
-1.039V   2.781mA    4.457mA    1.546mA
-1.016V   2.086mA    3.48mA     1.193mA
-993mV    1.578mA    2.707mA    966.5uA
-970mV    1.21mA     2.107mA    818.5uA
-924mV    750.8uA    1.296mA    641.3uA
-878mV    507uA      821.4uA    530.2uA
-809mV    327.4uA    430uA      403.3uA
-694mV    178.4uA    161uA      233uA
-464mV    19.89uA    15.19uA    23.61uA
1.1V      0A         0A         0A
[Ramp]
| variable   typ   min   max
dV/dt_r   0.225/26.844p   0.216/33.587p   0.240/21.797p
dV/dt_f   0.262/43.074p   0.243/54.491p   0.268/34.205p
R_load = 50.000
[Rising Waveform]
R_fixture= 50.000
V_fixture= 1.100
V_fixture_min= 1.060
V_fixture_max= 1.170
|time   V(typ)   V(min)   V(max)
0s        663.5mV    654.8mV    723.5mV
144ps     664.4mV    655.2mV    721.7mV
196ps     654.1mV    655.9mV    980.9mV
213ps     696.9mV    652.7mV    1.039V
266ps     955.7mV    636.6mV    1.128V
285ps     1.003V     677.3mV    1.137V
331ps     1.063V     893.3mV    1.153V
372ps     1.084V     988.6mV    1.163V
495ps     1.097V     1.055V     1.17V
3ns       1.1V       1.06V      1.17V
[Rising Waveform]
R_fixture= 50.000
V_fixture= 0.0
V_fixture_min= 0.0
V_fixture_max= 0.0
|time   V(typ)   V(min)   V(max)
0s        3.261uV    6.245uV    770.5nV
152ps     -152.5uV   43.82uV    13.12mV
191ps     932.3uV    -26.16uV   372.1mV
213ps     9.357mV    -90.14uV   455.3mV
264ps     350.3mV    1.258mV    487.3mV
302ps     419.9mV    38.54mV    412.3mV
340ps     429.8mV    278.2mV    400.3mV
369ps     433.3mV    367.8mV    400.3mV
489ps     374.2mV    402.3mV    400.4mV
3ns       374.4mV    360.6mV    400.4mV
[Falling Waveform]
R_fixture= 50.000
V_fixture= 1.100
V_fixture_min= 1.060
V_fixture_max= 1.170
|time   V(typ)   V(min)   V(max)
0s        1.1V       1.06V      1.17V
158ps     1.1V       1.06V      1.164V
224ps     1.09V      1.06V      726.4mV
272ps     817mV      1.058V     602.2mV
318ps     637mV      1.037V     676.8mV
361ps     576.4mV    859mV      707.3mV
414ps     621.5mV    669.2mV    719mV
494ps     657.7mV    579.1mV    722.8mV
695ps     663.4mV    653.5mV    723.5mV
3ns       663.5mV    654.8mV    723.5mV
[Falling Waveform]
R_fixture= 50.000
V_fixture= 0.0
V_fixture_min= 0.0
V_fixture_max= 0.0
|time   V(typ)   V(min)   V(max)
0s        374.4mV    360.6mV    400.4mV
145ps     373.8mV    360mV      409.8mV
182ps     390.8mV    359.3mV    144.5mV
197ps     389.8mV    360.7mV    72.9mV
212ps     340.9mV    365.1mV    36.34mV
252ps     94.94mV    386mV      5.765mV
287ps     21.29mV    294.6mV    -3.048mV
348ps     1.745mV    54.86mV    -510.2uV
418ps     -2.218mV   3.704mV    -22.44uV
3ns       1.549uV    6.183uV    58.3nV
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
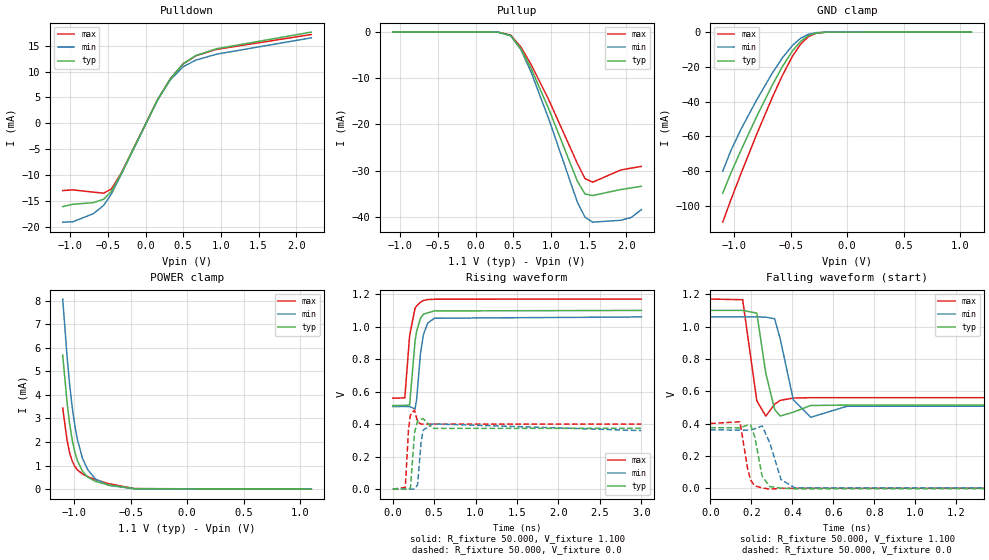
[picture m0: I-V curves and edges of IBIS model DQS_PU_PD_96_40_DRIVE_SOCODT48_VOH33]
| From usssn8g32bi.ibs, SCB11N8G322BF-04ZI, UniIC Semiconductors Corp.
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|   Model DQS_PU_PD_96_40_DRIVE_SOCODT48_VOH33
[Model] DQS_PU_PD_96_40_DRIVE_SOCODT48_VOH33
Model_type I/O
Polarity   Inverting
Vinl =  98.000mV
Vinh =  0.268V
Vmeas =  0.183V
Rref =  50.000
Vref =  0.183V
C_comp   1.020pF   1.010pF   1.030pF
[Model Spec]
Vinh   0.268V   0.262V   0.280V
Vinl   98.000mV   92.000mV   0.110V
Vmeas   0.183V   0.177V   0.195V
Vref   0.183V   0.177V   0.195V
Rref   50.000   NA   NA
[Temperature Range]   25.000   85.000   -40.000
[Voltage Range]   1.100V   1.060V   1.170V
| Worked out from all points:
|   slope of the pulldown table from 0 to 0.165 V, typ, clamps not added: 35.3 ohm
|   GND clamp passes 1 mA (typ) near -0.30 V on its own axis
|   POWER clamp passes 1 mA (typ) near -0.95 V on its own axis
|   rising waveform, R_fixture 50.000, V_fixture 1.100: 20-80 % time 68.5ps typ, 70.5ps min, 66.4ps max; typ from 0.514 V to 1.1 V
|   rising waveform, R_fixture 50.000, V_fixture 0.0: 20-80 % time 26.5ps typ, 33ps min, 21.5ps max; typ from 0 V to 0.374 V
|   falling waveform, R_fixture 50.000, V_fixture 1.100: 20-80 % time 39.6ps typ, 50.9ps min, 32.2ps max; typ from 1.1 V to 0.514 V
|   falling waveform, R_fixture 50.000, V_fixture 0.0: 20-80 % time 32.7ps typ, 49.9ps min, 27.4ps max; typ from 0.374 V to 0 V
[Pulldown]
|Voltage   I(typ)   I(min)   I(max)
-1.1V     -16.13mA   -19.15mA   -13.03mA
-964mV    -15.68mA   -19.06mA   -12.9mA
-692mV    -15.37mA   -17.49mA   -13.34mA
-556mV    -14.7mA    -15.89mA   -13.53mA
-454mV    -13.2mA    -13.69mA   -12.73mA
-318mV    -9.609mA   -9.745mA   -9.529mA
158mV     4.492mA    4.453mA    4.512mA
328mV     8.568mA    8.368mA    8.576mA
498mV     11.5mA     10.93mA    11.48mA
668mV     13.1mA     12.21mA    13.05mA
940mV     14.4mA     13.35mA    14.28mA
2.2V      17.63mA    16.52mA    17.16mA
[Pullup]
|Voltage   I(typ)   I(min)   I(max)
-1.1V     2.6nA      12.94nA    0A
296mV     -14.74uA   -17.65uA   -8.203uA
466mV     -773.5uA   -759.8uA   -645.2uA
602mV     -3.625mA   -3.82mA    -3.244mA
738mV     -7.914mA   -8.716mA   -7.039mA
976mV     -16.84mA   -19.04mA   -14.84mA
1.35V     -32.28mA   -36.82mA   -28.44mA
1.452V    -35.08mA   -40.12mA   -31.74mA
1.554V    -35.42mA   -41.2mA    -32.53mA
1.928V    -34.12mA   -40.78mA   -29.88mA
2.064V    -33.78mA   -40.2mA    -29.49mA
2.2V      -33.41mA   -38.49mA   -29.11mA
[GND_clamp]
|Voltage   I(typ)   I(min)   I(max)
-1.1V     -92.78mA   -80.14mA   -109.5mA
-1.031V   -81.73mA   -68.77mA   -97.17mA
-939mV    -68.18mA   -56.07mA   -81.64mA
-801mV    -48.85mA   -39.25mA   -59.15mA
-663mV    -30.71mA   -23.84mA   -37.89mA
-571mV    -19.76mA   -14.75mA   -24.85mA
-479mV    -10.5mA    -7.415mA   -13.5mA
-410mV    -5.313mA   -3.546mA   -6.916mA
-341mV    -2.007mA   -1.262mA   -2.59mA
-272mV    -506.9uA   -323.5uA   -609.8uA
-180mV    -45.65uA   -36.06uA   -43.55uA
1.1V      0A         0A         0A
[POWER_clamp]
|Voltage   I(typ)   I(min)   I(max)
-1.1V     5.691mA    8.066mA    3.44mA
-1.062V   3.709mA    5.665mA    2.092mA
-1.039V   2.781mA    4.457mA    1.546mA
-1.016V   2.086mA    3.48mA     1.193mA
-993mV    1.578mA    2.707mA    966.5uA
-970mV    1.21mA     2.107mA    818.5uA
-924mV    750.8uA    1.296mA    641.3uA
-878mV    507uA      821.4uA    530.2uA
-809mV    327.4uA    430uA      403.3uA
-694mV    178.4uA    161uA      233uA
-464mV    19.89uA    15.19uA    23.61uA
1.1V      0A         0A         0A
[Ramp]
| variable   typ   min   max
dV/dt_r   0.225/26.612p   0.216/33.123p   0.240/21.722p
dV/dt_f   0.351/39.753p   0.331/51.063p   0.366/32.298p
R_load = 50.000
[Rising Waveform]
R_fixture= 50.000
V_fixture= 1.100
V_fixture_min= 1.060
V_fixture_max= 1.170
|time   V(typ)   V(min)   V(max)
0s        514.4mV    508.1mV    560.3mV
146ps     515.3mV    508.7mV    561.5mV
204ps     518.6mV    508.2mV    944.2mV
269ps     907.6mV    493mV      1.113V
288ps     970.5mV    547.9mV    1.127V
335ps     1.052V     835.6mV    1.151V
371ps     1.077V     951.6mV    1.161V
422ps     1.085V     1.022V     1.167V
503ps     1.097V     1.052V     1.169V
3ns       1.1V       1.06V      1.17V
[Rising Waveform]
R_fixture= 50.000
V_fixture= 0.0
V_fixture_min= 0.0
V_fixture_max= 0.0
|time   V(typ)   V(min)   V(max)
0s        2.608uV    4.994uV    615.8nV
152ps     6.767uV    37.54uV    10.81mV
191ps     849.3uV    30.32uV    370.4mV
214ps     8.08mV     146.5uV    456.6mV
264ps     348.9mV    951.8uV    487.2mV
300ps     418.9mV    27.17mV    414.7mV
342ps     430.3mV    285.5mV    400.3mV
367ps     434.4mV    363.6mV    400.2mV
484ps     374.1mV    401.6mV    400.4mV
3ns       374.4mV    360.6mV    400.4mV
[Falling Waveform]
R_fixture= 50.000
V_fixture= 1.100
V_fixture_min= 1.060
V_fixture_max= 1.170
|time   V(typ)   V(min)   V(max)
0s        1.1V       1.06V      1.17V
158ps     1.1V       1.06V      1.166V
227ps     1.083V     1.06V      540.7mV
271ps     710mV      1.058V     445.8mV
314ps     487.2mV    1.048V     520.1mV
341ps     446.7mV    924mV      543.6mV
405ps     470.6mV    547.4mV    557.9mV
490ps     511.8mV    438.7mV    560.1mV
667ps     514.4mV    507.1mV    560.3mV
3ns       514.4mV    508.1mV    560.3mV
[Falling Waveform]
R_fixture= 50.000
V_fixture= 0.0
V_fixture_min= 0.0
V_fixture_max= 0.0
|time   V(typ)   V(min)   V(max)
0s        374.4mV    360.6mV    400.4mV
145ps     373.7mV    360mV      411.2mV
182ps     390.7mV    359.3mV    121.3mV
197ps     390.7mV    360.6mV    49.73mV
217ps     317.7mV    367.1mV    14.87mV
253ps     74.02mV    385.8mV    2.055mV
291ps     9.709mV    278.7mV    -5.651mV
345ps     853.4uV    53.94mV    -580.2uV
412ps     -3.608mV   2.556mV    -12.55uV
3ns       2.377uV    3.775uV    315.8nV
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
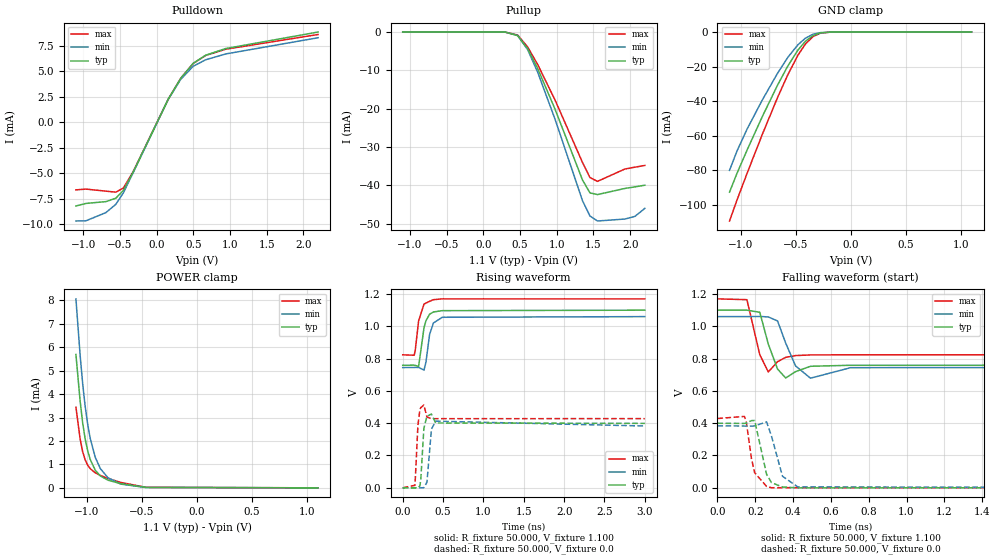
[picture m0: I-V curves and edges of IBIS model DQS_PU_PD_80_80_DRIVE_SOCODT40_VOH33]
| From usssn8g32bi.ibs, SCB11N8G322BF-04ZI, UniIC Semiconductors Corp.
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|   Model DQS_PU_PD_80_80_DRIVE_SOCODT40_VOH33
[Model] DQS_PU_PD_80_80_DRIVE_SOCODT40_VOH33
Model_type I/O
Polarity   Inverting
Vinl =  98.000mV
Vinh =  0.268V
Vmeas =  0.183V
Rref =  50.000
Vref =  0.183V
C_comp   1.020pF   1.010pF   1.030pF
[Model Spec]
Vinh   0.268V   0.262V   0.280V
Vinl   98.000mV   92.000mV   0.110V
Vmeas   0.183V   0.177V   0.195V
Vref   0.183V   0.177V   0.195V
Rref   50.000   NA   NA
[Temperature Range]   25.000   85.000   -40.000
[Voltage Range]   1.100V   1.060V   1.170V
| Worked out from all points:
|   slope of the pulldown table from 0 to 0.165 V, typ, clamps not added: 70.2 ohm
|   GND clamp passes 1 mA (typ) near -0.30 V on its own axis
|   POWER clamp passes 1 mA (typ) near -0.95 V on its own axis
|   rising waveform, R_fixture 50.000, V_fixture 1.100: 20-80 % time 64.6ps typ, 63.8ps min, 64.3ps max; typ from 0.759 V to 1.1 V
|   rising waveform, R_fixture 50.000, V_fixture 0.0: 20-80 % time 26ps typ, 33ps min, 20.9ps max; typ from 0 V to 0.399 V
|   falling waveform, R_fixture 50.000, V_fixture 1.100: 20-80 % time 44.2ps typ, 56.4ps min, 34.9ps max; typ from 1.1 V to 0.759 V
|   falling waveform, R_fixture 50.000, V_fixture 0.0: 20-80 % time 41.9ps typ, 53.2ps min, 37.7ps max; typ from 0.399 V to 0 V
[Pulldown]
|Voltage   I(typ)   I(min)   I(max)
-1.1V     -8.193mA   -9.666mA   -6.618mA
-964mV    -7.945mA   -9.646mA   -6.54mA
-692mV    -7.769mA   -8.844mA   -6.742mA
-556mV    -7.432mA   -8.032mA   -6.841mA
-454mV    -6.673mA   -6.916mA   -6.44mA
-318mV    -4.841mA   -4.906mA   -4.804mA
158mV     2.257mA    2.237mA    2.267mA
328mV     4.302mA    4.2mA      4.305mA
498mV     5.77mA     5.483mA    5.759mA
668mV     6.567mA    6.118mA    6.54mA
940mV     7.217mA    6.688mA    7.152mA
2.2V      8.836mA    8.278mA    8.595mA
[Pullup]
|Voltage   I(typ)   I(min)   I(max)
-1.1V     3.1nA      15.54nA    0A
296mV     -17.69uA   -21.17uA   -9.843uA
466mV     -927.4uA   -911uA     -773.6uA
602mV     -4.341mA   -4.574mA   -3.886mA
738mV     -9.474mA   -10.43mA   -8.429mA
976mV     -20.15mA   -22.77mA   -17.76mA
1.35V     -38.63mA   -44.04mA   -34.05mA
1.452V    -42.01mA   -48.04mA   -38mA
1.554V    -42.45mA   -49.35mA   -39mA
1.928V    -40.84mA   -48.83mA   -35.77mA
2.064V    -40.44mA   -48.15mA   -35.29mA
2.2V      -40mA      -46.05mA   -34.84mA
[GND_clamp]
|Voltage   I(typ)   I(min)   I(max)
-1.1V     -92.78mA   -80.14mA   -109.5mA
-1.031V   -81.73mA   -68.77mA   -97.17mA
-939mV    -68.18mA   -56.07mA   -81.64mA
-801mV    -48.85mA   -39.25mA   -59.15mA
-663mV    -30.71mA   -23.84mA   -37.89mA
-571mV    -19.76mA   -14.75mA   -24.85mA
-479mV    -10.5mA    -7.415mA   -13.5mA
-410mV    -5.313mA   -3.546mA   -6.916mA
-341mV    -2.007mA   -1.262mA   -2.59mA
-272mV    -506.9uA   -323.5uA   -609.8uA
-180mV    -45.65uA   -36.06uA   -43.55uA
1.1V      0A         0A         0A
[POWER_clamp]
|Voltage   I(typ)   I(min)   I(max)
-1.1V     5.691mA    8.066mA    3.44mA
-1.062V   3.709mA    5.665mA    2.092mA
-1.039V   2.781mA    4.457mA    1.546mA
-1.016V   2.086mA    3.48mA     1.193mA
-993mV    1.578mA    2.707mA    966.5uA
-970mV    1.21mA     2.107mA    818.5uA
-924mV    750.8uA    1.296mA    641.3uA
-878mV    507uA      821.4uA    530.2uA
-809mV    327.4uA    430uA      403.3uA
-694mV    178.4uA    161uA      233uA
-464mV    19.89uA    15.19uA    23.61uA
1.1V      0A         0A         0A
[Ramp]
| variable   typ   min   max
dV/dt_r   0.239/26.176p   0.230/32.998p   0.257/21.208p
dV/dt_f   0.205/44.306p   0.189/56.485p   0.208/35.037p
R_load = 50.000
[Rising Waveform]
R_fixture= 50.000
V_fixture= 1.100
V_fixture_min= 1.060
V_fixture_max= 1.170
|time   V(typ)   V(min)   V(max)
0s        758.6mV    744.6mV    823.3mV
142ps     759.4mV    744.9mV    821mV
155ps     758mV      745.3mV    850.2mV
197ps     752.2mV    745.2mV    1.034V
264ps     992mV      728.8mV    1.138V
288ps     1.035V     779.3mV    1.144V
333ps     1.075V     950mV      1.155V
381ps     1.089V     1.021V     1.165V
491ps     1.097V     1.056V     1.17V
3ns       1.1V       1.06V      1.17V
[Rising Waveform]
R_fixture= 50.000
V_fixture= 0.0
V_fixture_min= 0.0
V_fixture_max= 0.0
|time   V(typ)   V(min)   V(max)
0s        3.731uV    7.145uV    881.9nV
152ps     -288.5uV   55.09uV    15.33mV
188ps     327.9uV    -6.854uV   384.7mV
213ps     11.77mV    -285.6uV   484.7mV
224ps     52.62mV    -339.1uV   496.4mV
262ps     367.7mV    767.3uV    512.6mV
300ps     443.2mV    34.56mV    438.4mV
356ps     456.8mV    363.2mV    427.7mV
408ps     401.4mV    412.5mV    428.2mV
3ns       398.9mV    382.6mV    428.3mV
[Falling Waveform]
R_fixture= 50.000
V_fixture= 1.100
V_fixture_min= 1.060
V_fixture_max= 1.170
|time   V(typ)   V(min)   V(max)
0s        1.1V       1.06V      1.17V
156ps     1.1V       1.06V      1.165V
224ps     1.087V     1.061V     823.6mV
269ps     889.6mV    1.058V     717mV
318ps     735mV      1.033V     780.7mV
361ps     679.5mV    896mV      807.5mV
413ps     718.8mV    754.6mV    818.5mV
492ps     752.1mV    678.3mV    822.5mV
704ps     758.5mV    743.5mV    823.3mV
3ns       758.6mV    744.6mV    823.3mV
[Falling Waveform]
R_fixture= 50.000
V_fixture= 0.0
V_fixture_min= 0.0
V_fixture_max= 0.0
|time   V(typ)   V(min)   V(max)
0s        398.9mV    382.6mV    428.3mV
143ps     398mV      381.9mV    441.5mV
153ps     400.3mV    381.6mV    405.2mV
180ps     415.5mV    381.1mV    180.3mV
197ps     415.9mV    382.6mV    92.55mV
260ps     82.16mV    407.5mV    7.311mV
286ps     31.15mV    319.2mV    -633.1uV
344ps     3.747mV    70.7mV     -373uV
425ps     -1.317mV   4.418mV    -16.33uV
3ns       3.545uV    6.271uV    402.8nV
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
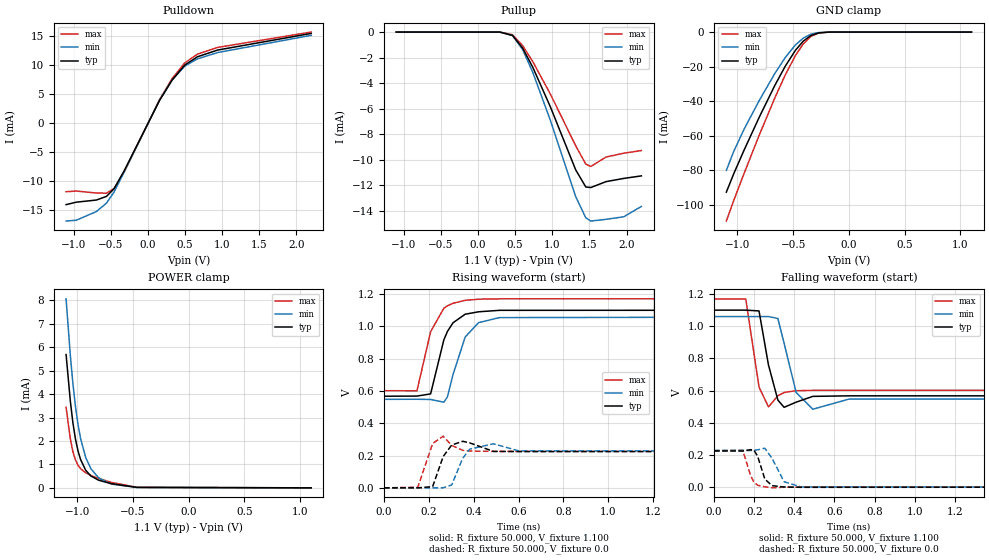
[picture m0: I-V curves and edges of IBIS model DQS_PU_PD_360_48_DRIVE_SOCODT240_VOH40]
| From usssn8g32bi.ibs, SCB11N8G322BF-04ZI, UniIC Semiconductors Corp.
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|   Model DQS_PU_PD_360_48_DRIVE_SOCODT240_VOH40
[Model] DQS_PU_PD_360_48_DRIVE_SOCODT240_VOH40
Model_type I/O
Polarity   Inverting
Vinl =  0.135V
Vinh =  0.305V
Vmeas =  0.220V
Rref =  50.000
Vref =  0.220V
C_comp   1.020pF   1.010pF   1.030pF
[Model Spec]
Vinh   0.305V   0.297V   0.319V
Vinl   0.135V   0.127V   0.149V
Vmeas   0.220V   0.212V   0.234V
Vref   0.220V   0.212V   0.234V
Rref   50.000   NA   NA
[Temperature Range]   25.000   85.000   -40.000
[Voltage Range]   1.100V   1.060V   1.170V
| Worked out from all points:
|   slope of the pulldown table from 0 to 0.165 V, typ, clamps not added: 41 ohm
|   GND clamp passes 1 mA (typ) near -0.30 V on its own axis
|   POWER clamp passes 1 mA (typ) near -0.95 V on its own axis
|   rising waveform, R_fixture 50.000, V_fixture 1.100: 20-80 % time 68.8ps typ, 72.4ps min, 66.9ps max; typ from 0.567 V to 1.1 V
|   rising waveform, R_fixture 50.000, V_fixture 0.0: 20-80 % time 30.5ps typ, 38.9ps min, 24.4ps max; typ from 0 V to 0.225 V
|   falling waveform, R_fixture 50.000, V_fixture 1.100: 20-80 % time 41.5ps typ, 53.3ps min, 34.1ps max; typ from 1.1 V to 0.567 V
|   falling waveform, R_fixture 50.000, V_fixture 0.0: 20-80 % time 34.8ps typ, 53.4ps min, 31.2ps max; typ from 0.225 V to 0 V
[Pulldown]
|Voltage   I(typ)   I(min)   I(max)
-1.1V     -14.07mA   -16.89mA   -11.85mA
-964mV    -13.65mA   -16.76mA   -11.73mA
-692mV    -13.28mA   -15.26mA   -12.07mA
-556mV    -12.65mA   -13.81mA   -12.1mA
-454mV    -11.34mA   -11.89mA   -11.29mA
-318mV    -8.242mA   -8.458mA   -8.422mA
158mV     3.863mA    3.899mA    4mA
328mV     7.389mA    7.394mA    7.65mA
498mV     9.955mA    9.787mA    10.33mA
668mV     11.38mA    11.02mA    11.83mA
940mV     12.54mA    12.11mA    12.99mA
2.2V      15.4mA     15.07mA    15.64mA
[Pullup]
|Voltage   I(typ)   I(min)   I(max)
-1.1V     900pA      4.512nA    0A
296mV     -5.16uA    -6.193uA   -2.645uA
466mV     -269.4uA   -269uA     -210.8uA
602mV     -1.26mA    -1.371mA   -1.066mA
738mV     -2.752mA   -3.15mA    -2.312mA
976mV     -5.863mA   -6.919mA   -4.864mA
1.316V    -10.78mA   -12.87mA   -8.894mA
1.452V    -12.12mA   -14.53mA   -10.33mA
1.52V     -12.16mA   -14.78mA   -10.51mA
1.724V    -11.7mA    -14.65mA   -9.778mA
1.962V    -11.45mA   -14.45mA   -9.476mA
2.2V      -11.25mA   -13.64mA   -9.27mA
[GND_clamp]
|Voltage   I(typ)   I(min)   I(max)
-1.1V     -92.78mA   -80.14mA   -109.5mA
-1.031V   -81.73mA   -68.77mA   -97.17mA
-939mV    -68.18mA   -56.07mA   -81.64mA
-801mV    -48.85mA   -39.25mA   -59.15mA
-663mV    -30.71mA   -23.84mA   -37.89mA
-571mV    -19.76mA   -14.75mA   -24.85mA
-479mV    -10.5mA    -7.415mA   -13.5mA
-410mV    -5.313mA   -3.546mA   -6.916mA
-341mV    -2.007mA   -1.262mA   -2.59mA
-272mV    -506.9uA   -323.5uA   -609.8uA
-180mV    -45.65uA   -36.06uA   -43.55uA
1.1V      0A         0A         0A
[POWER_clamp]
|Voltage   I(typ)   I(min)   I(max)
-1.1V     5.691mA    8.066mA    3.44mA
-1.062V   3.709mA    5.665mA    2.092mA
-1.039V   2.781mA    4.457mA    1.546mA
-1.016V   2.086mA    3.48mA     1.193mA
-993mV    1.578mA    2.707mA    966.5uA
-970mV    1.21mA     2.107mA    818.5uA
-924mV    750.8uA    1.296mA    641.3uA
-878mV    507uA      821.4uA    530.2uA
-809mV    327.4uA    430uA      403.3uA
-694mV    178.4uA    161uA      233uA
-464mV    19.89uA    15.19uA    23.61uA
1.1V      0A         0A         0A
[Ramp]
| variable   typ   min   max
dV/dt_r   0.135/30.432p   0.137/39.103p   0.135/24.523p
dV/dt_f   0.320/41.680p   0.307/53.476p   0.341/34.150p
R_load = 50.000
[Rising Waveform]
R_fixture= 50.000
V_fixture= 1.100
V_fixture_min= 1.060
V_fixture_max= 1.170
|time   V(typ)   V(min)   V(max)
0s        567.3mV    547.9mV    601.6mV
147ps     568.1mV    548.5mV    600.6mV
208ps     581.6mV    547.1mV    966.8mV
267ps     916.3mV    530.2mV    1.112V
283ps     968.5mV    563.5mV    1.127V
308ps     1.022V     701.8mV    1.143V
362ps     1.075V     933.9mV    1.161V
422ps     1.09V      1.023V     1.168V
515ps     1.099V     1.054V     1.17V
3ns       1.1V       1.06V      1.17V
[Rising Waveform]
R_fixture= 50.000
V_fixture= 0.0
V_fixture_min= 0.0
V_fixture_max= 0.0
|time   V(typ)   V(min)   V(max)
0s        2.854uV    5.42uV     663.5nV
151ps     135uV      17.54uV    3.94mV
217ps     7.638mV    355.2uV    274.5mV
264ps     194mV      127.6uV    319.8mV
302ps     265.1mV    18.05mV    262.7mV
351ps     288.2mV    182.9mV    232.5mV
382ps     278.6mV    239.4mV    227.9mV
488ps     225.7mV    272.8mV    225.5mV
601ps     224.7mV    228.8mV    225.5mV
3ns       224.7mV    228.3mV    225.5mV
[Falling Waveform]
R_fixture= 50.000
V_fixture= 1.100
V_fixture_min= 1.060
V_fixture_max= 1.170
|time   V(typ)   V(min)   V(max)
0s        1.1V       1.06V      1.17V
158ps     1.1V       1.06V      1.169V
224ps     1.095V     1.06V      622mV
271ps     759.6mV    1.06V      498.3mV
318ps     540.8mV    1.048V     567.7mV
349ps     495.9mV    894mV      588.2mV
409ps     527.9mV    588.5mV    599.2mV
492ps     564mV      484mV      601.4mV
672ps     567.3mV    546.9mV    601.6mV
3ns       567.3mV    547.9mV    601.6mV
[Falling Waveform]
R_fixture= 50.000
V_fixture= 0.0
V_fixture_min= 0.0
V_fixture_max= 0.0
|time   V(typ)   V(min)   V(max)
0s        224.7mV    228.3mV    225.5mV
143ps     224.3mV    228mV      229.5mV
182ps     232.5mV    227.6mV    71.64mV
198ps     230.9mV    228.5mV    31.94mV
217ps     192.3mV    231.9mV    11.76mV
253ps     49.68mV    241.5mV    2.038mV
289ps     8.965mV    179.1mV    -4.6mV
349ps     740.5uV    33.2mV     -453.8uV
434ps     -1.319mV   1.115mV    -5.101uV
3ns       -1.615uV   5.254uV    550.5nV
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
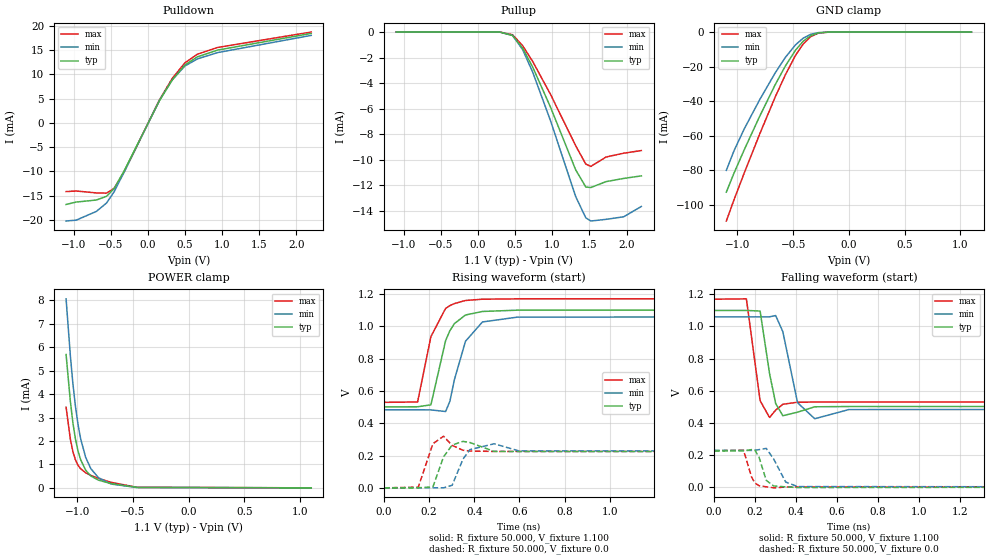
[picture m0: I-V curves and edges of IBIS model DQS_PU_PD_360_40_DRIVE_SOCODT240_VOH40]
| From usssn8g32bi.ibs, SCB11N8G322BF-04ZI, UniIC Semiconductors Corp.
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|   Model DQS_PU_PD_360_40_DRIVE_SOCODT240_VOH40
[Model] DQS_PU_PD_360_40_DRIVE_SOCODT240_VOH40
Model_type I/O
Polarity   Inverting
Vinl =  0.135V
Vinh =  0.305V
Vmeas =  0.220V
Rref =  50.000
Vref =  0.220V
C_comp   1.020pF   1.010pF   1.030pF
[Model Spec]
Vinh   0.305V   0.297V   0.319V
Vinl   0.135V   0.127V   0.149V
Vmeas   0.220V   0.212V   0.234V
Vref   0.220V   0.212V   0.234V
Rref   50.000   NA   NA
[Temperature Range]   25.000   85.000   -40.000
[Voltage Range]   1.100V   1.060V   1.170V
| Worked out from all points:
|   slope of the pulldown table from 0 to 0.165 V, typ, clamps not added: 34.3 ohm
|   GND clamp passes 1 mA (typ) near -0.30 V on its own axis
|   POWER clamp passes 1 mA (typ) near -0.95 V on its own axis
|   rising waveform, R_fixture 50.000, V_fixture 1.100: 20-80 % time 69.2ps typ, 73ps min, 67.1ps max; typ from 0.501 V to 1.1 V
|   rising waveform, R_fixture 50.000, V_fixture 0.0: 20-80 % time 30.4ps typ, 39ps min, 24.5ps max; typ from 0 V to 0.225 V
|   falling waveform, R_fixture 50.000, V_fixture 1.100: 20-80 % time 39.4ps typ, 50.9ps min, 32.6ps max; typ from 1.1 V to 0.501 V
|   falling waveform, R_fixture 50.000, V_fixture 0.0: 20-80 % time 32.3ps typ, 52.9ps min, 28.7ps max; typ from 0.225 V to 0 V
[Pulldown]
|Voltage   I(typ)   I(min)   I(max)
-1.1V     -16.81mA   -20.22mA   -14.15mA
-964mV    -16.31mA   -20.04mA   -14.03mA
-692mV    -15.89mA   -18.24mA   -14.43mA
-556mV    -15.13mA   -16.51mA   -14.47mA
-454mV    -13.55mA   -14.21mA   -13.5mA
-318mV    -9.863mA   -10.12mA   -10.07mA
158mV     4.627mA    4.669mA    4.79mA
328mV     8.852mA    8.857mA    9.163mA
498mV     11.93mA    11.73mA    12.38mA
668mV     13.64mA    13.21mA    14.18mA
940mV     15.03mA    14.51mA    15.57mA
2.2V      18.47mA    18.06mA    18.75mA
[Pullup]
|Voltage   I(typ)   I(min)   I(max)
-1.1V     900pA      4.512nA    0A
296mV     -5.16uA    -6.193uA   -2.645uA
466mV     -269.4uA   -269uA     -210.8uA
602mV     -1.26mA    -1.371mA   -1.066mA
738mV     -2.752mA   -3.15mA    -2.312mA
976mV     -5.863mA   -6.919mA   -4.864mA
1.316V    -10.78mA   -12.87mA   -8.894mA
1.452V    -12.12mA   -14.53mA   -10.33mA
1.52V     -12.16mA   -14.78mA   -10.51mA
1.724V    -11.7mA    -14.65mA   -9.778mA
1.962V    -11.45mA   -14.45mA   -9.476mA
2.2V      -11.25mA   -13.64mA   -9.27mA
[GND_clamp]
|Voltage   I(typ)   I(min)   I(max)
-1.1V     -92.78mA   -80.14mA   -109.5mA
-1.031V   -81.73mA   -68.77mA   -97.17mA
-939mV    -68.18mA   -56.07mA   -81.64mA
-801mV    -48.85mA   -39.25mA   -59.15mA
-663mV    -30.71mA   -23.84mA   -37.89mA
-571mV    -19.76mA   -14.75mA   -24.85mA
-479mV    -10.5mA    -7.415mA   -13.5mA
-410mV    -5.313mA   -3.546mA   -6.916mA
-341mV    -2.007mA   -1.262mA   -2.59mA
-272mV    -506.9uA   -323.5uA   -609.8uA
-180mV    -45.65uA   -36.06uA   -43.55uA
1.1V      0A         0A         0A
[POWER_clamp]
|Voltage   I(typ)   I(min)   I(max)
-1.1V     5.691mA    8.066mA    3.44mA
-1.062V   3.709mA    5.665mA    2.092mA
-1.039V   2.781mA    4.457mA    1.546mA
-1.016V   2.086mA    3.48mA     1.193mA
-993mV    1.578mA    2.707mA    966.5uA
-970mV    1.21mA     2.107mA    818.5uA
-924mV    750.8uA    1.296mA    641.3uA
-878mV    507uA      821.4uA    530.2uA
-809mV    327.4uA    430uA      403.3uA
-694mV    178.4uA    161uA      233uA
-464mV    19.89uA    15.19uA    23.61uA
1.1V      0A         0A         0A
[Ramp]
| variable   typ   min   max
dV/dt_r   0.135/30.349p   0.137/39.121p   0.135/24.557p
dV/dt_f   0.359/39.608p   0.346/51.129p   0.384/32.650p
R_load = 50.000
[Rising Waveform]
R_fixture= 50.000
V_fixture= 1.100
V_fixture_min= 1.060
V_fixture_max= 1.170
|time   V(typ)   V(min)   V(max)
0s        501.3mV    483mV      529.3mV
149ps     501.9mV    483.6mV    531.8mV
208ps     514mV      482.5mV    936.7mV
273ps     911.6mV    472.6mV    1.111V
292ps     973.2mV    536.3mV    1.128V
312ps     1.017V     670.4mV    1.141V
361ps     1.07V      907.6mV    1.16V
436ps     1.092V     1.027V     1.168V
591ps     1.1V       1.057V     1.17V
3ns       1.1V       1.06V      1.17V
[Rising Waveform]
R_fixture= 50.000
V_fixture= 0.0
V_fixture_min= 0.0
V_fixture_max= 0.0
|time   V(typ)   V(min)   V(max)
0s        2.565uV    4.869uV    595.6nV
152ps     207.5uV    19.87uV    4.358mV
217ps     6.486mV    443.5uV    273.6mV
264ps     192.3mV    149.1uV    319.7mV
302ps     264.8mV    16.03mV    262.7mV
350ps     287.8mV    177.9mV    232.7mV
380ps     280.9mV    236.3mV    228.1mV
488ps     225.7mV    272.8mV    225.5mV
597ps     224.7mV    228.9mV    225.5mV
3ns       224.7mV    228.3mV    225.5mV
[Falling Waveform]
R_fixture= 50.000
V_fixture= 1.100
V_fixture_min= 1.060
V_fixture_max= 1.170
|time   V(typ)   V(min)   V(max)
0s        1.1V       1.06V      1.17V
158ps     1.1V       1.06V      1.172V
225ps     1.096V     1.06V      537.5mV
271ps     708.2mV    1.06V      433mV
301ps     519.9mV    1.068V     478.7mV
336ps     444mV      968mV      515.1mV
408ps     466mV      524.9mV    528.1mV
492ps     499.5mV    425.1mV    529.2mV
659ps     501.2mV    482.4mV    529.3mV
3ns       501.3mV    483mV      529.3mV
[Falling Waveform]
R_fixture= 50.000
V_fixture= 0.0
V_fixture_min= 0.0
V_fixture_max= 0.0
|time   V(typ)   V(min)   V(max)
0s        224.7mV    228.3mV    225.5mV
144ps     224.3mV    228mV      229mV
183ps     232.7mV    227.6mV    63.06mV
199ps     230.6mV    228.6mV    25.6mV
220ps     184.3mV    232.7mV    7.498mV
255ps     41.14mV    240.4mV    1.293mV
291ps     6.253mV    174.7mV    -5.492mV
350ps     562.5uV    30.6mV     -382.2uV
409ps     -3.709mV   2.363mV    -11.1uV
3ns       -2.962uV   3.812uV    1.145nV
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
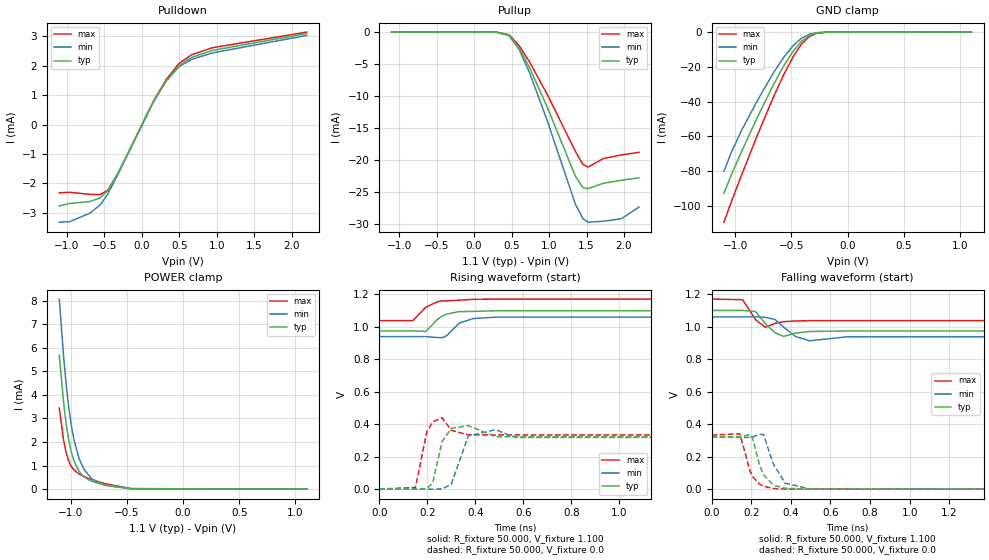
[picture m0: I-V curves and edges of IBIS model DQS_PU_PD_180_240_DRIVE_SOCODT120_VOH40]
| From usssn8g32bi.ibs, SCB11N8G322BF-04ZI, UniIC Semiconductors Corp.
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|   Model DQS_PU_PD_180_240_DRIVE_SOCODT120_VOH40
[Model] DQS_PU_PD_180_240_DRIVE_SOCODT120_VOH40
Model_type I/O
Polarity   Inverting
Vinl =  0.135V
Vinh =  0.305V
Vmeas =  0.220V
Rref =  50.000
Vref =  0.220V
C_comp   1.020pF   1.010pF   1.030pF
[Model Spec]
Vinh   0.305V   0.297V   0.319V
Vinl   0.135V   0.127V   0.149V
Vmeas   0.220V   0.212V   0.234V
Vref   0.220V   0.212V   0.234V
Rref   50.000   NA   NA
[Temperature Range]   25.000   85.000   -40.000
[Voltage Range]   1.100V   1.060V   1.170V
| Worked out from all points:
|   slope of the pulldown table from 0 to 0.165 V, typ, clamps not added: 205 ohm
|   GND clamp passes 1 mA (typ) near -0.30 V on its own axis
|   POWER clamp passes 1 mA (typ) near -0.95 V on its own axis
|   rising waveform, R_fixture 50.000, V_fixture 1.100: 20-80 % time 59.2ps typ, 58.9ps min, 62.7ps max; typ from 0.973 V to 1.1 V
|   rising waveform, R_fixture 50.000, V_fixture 0.0: 20-80 % time 27.6ps typ, 35.6ps min, 21.8ps max; typ from 0 V to 0.323 V
|   falling waveform, R_fixture 50.000, V_fixture 1.100: 20-80 % time 47.1ps typ, 62.3ps min, 37.1ps max; typ from 1.1 V to 0.973 V
|   falling waveform, R_fixture 50.000, V_fixture 0.0: 20-80 % time 55ps typ, 61.8ps min, 53ps max; typ from 0.323 V to 0 V
[Pulldown]
|Voltage   I(typ)   I(min)   I(max)
-1.1V     -2.76mA    -3.313mA   -2.318mA
-964mV    -2.679mA   -3.298mA   -2.298mA
-692mV    -2.611mA   -3.007mA   -2.368mA
-556mV    -2.492mA   -2.73mA    -2.377mA
-454mV    -2.244mA   -2.361mA   -2.229mA
-318mV    -1.646mA   -1.692mA   -1.68mA
158mV     774.5uA    782.1uA    802.1uA
328mV     1.481mA    1.483mA    1.534mA
498mV     1.994mA    1.962mA    2.07mA
668mV     2.279mA    2.209mA    2.37mA
940mV     2.511mA    2.427mA    2.602mA
2.2V      3.086mA    3.021mA    3.134mA
[Pullup]
|Voltage   I(typ)   I(min)   I(max)
-1.1V     1.8nA      9.024nA    0A
296mV     -10.32uA   -12.39uA   -5.289uA
466mV     -538.9uA   -538.1uA   -421.8uA
602mV     -2.521mA   -2.744mA   -2.134mA
738mV     -5.508mA   -6.307mA   -4.628mA
976mV     -11.74mA   -13.85mA   -9.734mA
1.35V     -22.51mA   -26.87mA   -18.62mA
1.452V    -24.32mA   -29.17mA   -20.7mA
1.52V     -24.46mA   -29.71mA   -21.11mA
1.724V    -23.63mA   -29.56mA   -19.76mA
1.962V    -23.16mA   -29.18mA   -19.2mA
2.2V      -22.76mA   -27.35mA   -18.79mA
[GND_clamp]
|Voltage   I(typ)   I(min)   I(max)
-1.1V     -92.78mA   -80.14mA   -109.5mA
-1.031V   -81.73mA   -68.77mA   -97.17mA
-939mV    -68.18mA   -56.07mA   -81.64mA
-801mV    -48.85mA   -39.25mA   -59.15mA
-663mV    -30.71mA   -23.84mA   -37.89mA
-571mV    -19.76mA   -14.75mA   -24.85mA
-479mV    -10.5mA    -7.415mA   -13.5mA
-410mV    -5.313mA   -3.546mA   -6.916mA
-341mV    -2.007mA   -1.262mA   -2.59mA
-272mV    -506.9uA   -323.5uA   -609.8uA
-180mV    -45.65uA   -36.06uA   -43.55uA
1.1V      0A         0A         0A
[POWER_clamp]
|Voltage   I(typ)   I(min)   I(max)
-1.1V     5.691mA    8.066mA    3.44mA
-1.062V   3.709mA    5.665mA    2.092mA
-1.039V   2.781mA    4.457mA    1.546mA
-1.016V   2.086mA    3.48mA     1.193mA
-993mV    1.578mA    2.707mA    966.5uA
-970mV    1.21mA     2.107mA    818.5uA
-924mV    750.8uA    1.296mA    641.3uA
-878mV    507uA      821.4uA    530.2uA
-809mV    327.4uA    430uA      403.3uA
-694mV    178.4uA    161uA      233uA
-464mV    19.89uA    15.19uA    23.61uA
1.1V      0A         0A         0A
[Ramp]
| variable   typ   min   max
dV/dt_r   0.194/27.757p   0.192/35.670p   0.200/21.945p
dV/dt_f   75.974m/47.213p   72.781m/62.234p   79.780m/37.172p
R_load = 50.000
[Rising Waveform]
R_fixture= 50.000
V_fixture= 1.100
V_fixture_min= 1.060
V_fixture_max= 1.170
|time   V(typ)   V(min)   V(max)
0s        973.4mV    938.7mV    1.037V
140ps     973.7mV    938.9mV    1.037V
194ps     970.6mV    939mV      1.12V
242ps     1.044V     933mV      1.153V
263ps     1.066V     932.3mV    1.159V
281ps     1.077V     945mV      1.159V
333ps     1.093V     1.022V     1.163V
391ps     1.094V     1.05V      1.168V
491ps     1.098V     1.059V     1.17V
3ns       1.1V       1.06V      1.17V
[Rising Waveform]
R_fixture= 50.000
V_fixture= 0.0
V_fixture_min= 0.0
V_fixture_max= 0.0
|time   V(typ)   V(min)   V(max)
0s        5.206uV    9.934uV    1.225uV
151ps     -253.1uV   65.51uV    9.989mV
198ps     2.551mV    -160.5uV   351.8mV
223ps     39.66mV    -421.8uV   414.2mV
262ps     293.3mV    953.1uV    439.2mV
300ps     374.1mV    29.56mV    361.9mV
371ps     391.1mV    327.2mV    333.9mV
484ps     322.9mV    365.8mV    333.3mV
567ps     323.1mV    317.9mV    333.3mV
3ns       323.1mV    319.3mV    333.3mV
[Falling Waveform]
R_fixture= 50.000
V_fixture= 1.100
V_fixture_min= 1.060
V_fixture_max= 1.170
|time   V(typ)   V(min)   V(max)
0s        1.1V       1.06V      1.17V
157ps     1.1V       1.06V      1.166V
222ps     1.093V     1.061V     1.043V
272ps     1.017V     1.057V     996mV
321ps     962.3mV    1.044V     1.021V
364ps     940.4mV    996.9mV    1.031V
424ps     960.5mV    939.4mV    1.035V
496ps     970.7mV    913.3mV    1.037V
687ps     973.3mV    938.1mV    1.037V
3ns       973.4mV    938.7mV    1.037V
[Falling Waveform]
R_fixture= 50.000
V_fixture= 0.0
V_fixture_min= 0.0
V_fixture_max= 0.0
|time   V(typ)   V(min)   V(max)
0s        323.1mV    319.3mV    333.3mV
143ps     322.4mV    318.8mV    340.4mV
195ps     336mV      318.9mV    108.4mV
209ps     306.3mV    322mV      74.99mV
242ps     149.4mV    337.5mV    31.24mV
262ps     89.02mV    336.4mV    18.19mV
311ps     25.55mV    156.1mV    4.248mV
371ps     5.182mV    37.37mV    935.9uV
495ps     147.7uV    1.632mV    41.06uV
3ns       2.445uV    9.891uV    1.249uV
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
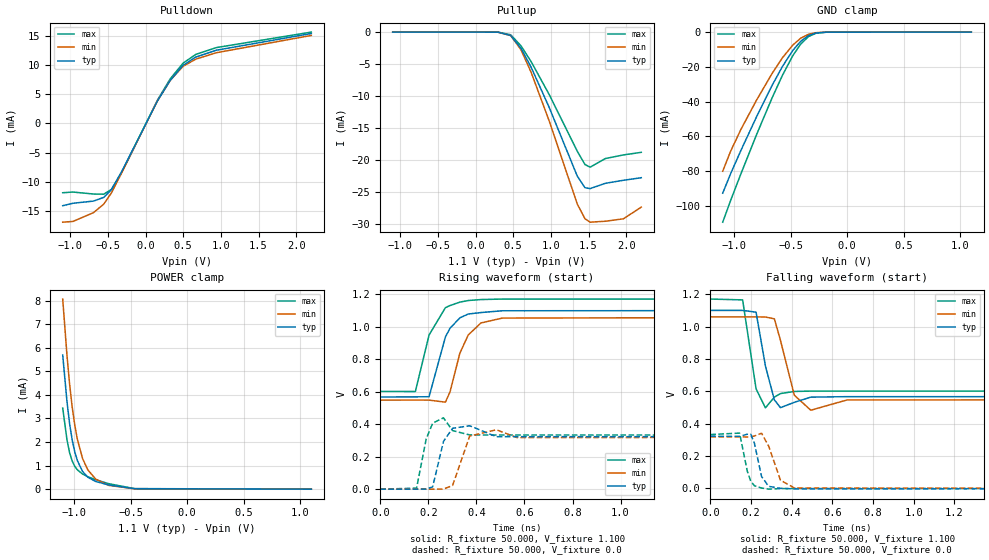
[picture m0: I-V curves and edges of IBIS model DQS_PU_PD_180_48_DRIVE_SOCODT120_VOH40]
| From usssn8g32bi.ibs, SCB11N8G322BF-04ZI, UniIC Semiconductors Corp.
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|   Model DQS_PU_PD_180_48_DRIVE_SOCODT120_VOH40
[Model] DQS_PU_PD_180_48_DRIVE_SOCODT120_VOH40
Model_type I/O
Polarity   Inverting
Vinl =  0.135V
Vinh =  0.305V
Vmeas =  0.220V
Rref =  50.000
Vref =  0.220V
C_comp   1.020pF   1.010pF   1.030pF
[Model Spec]
Vinh   0.305V   0.297V   0.319V
Vinl   0.135V   0.127V   0.149V
Vmeas   0.220V   0.212V   0.234V
Vref   0.220V   0.212V   0.234V
Rref   50.000   NA   NA
[Temperature Range]   25.000   85.000   -40.000
[Voltage Range]   1.100V   1.060V   1.170V
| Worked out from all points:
|   slope of the pulldown table from 0 to 0.165 V, typ, clamps not added: 41 ohm
|   GND clamp passes 1 mA (typ) near -0.30 V on its own axis
|   POWER clamp passes 1 mA (typ) near -0.95 V on its own axis
|   rising waveform, R_fixture 50.000, V_fixture 1.100: 20-80 % time 68ps typ, 71.1ps min, 66.8ps max; typ from 0.567 V to 1.1 V
|   rising waveform, R_fixture 50.000, V_fixture 0.0: 20-80 % time 27.2ps typ, 34.7ps min, 21.7ps max; typ from 0 V to 0.323 V
|   falling waveform, R_fixture 50.000, V_fixture 1.100: 20-80 % time 41.7ps typ, 53.9ps min, 34.3ps max; typ from 1.1 V to 0.567 V
|   falling waveform, R_fixture 50.000, V_fixture 0.0: 20-80 % time 34.1ps typ, 51.4ps min, 30.5ps max; typ from 0.323 V to 0 V
[Pulldown]
|Voltage   I(typ)   I(min)   I(max)
-1.1V     -14.07mA   -16.89mA   -11.85mA
-964mV    -13.65mA   -16.76mA   -11.73mA
-692mV    -13.28mA   -15.26mA   -12.07mA
-556mV    -12.65mA   -13.81mA   -12.1mA
-454mV    -11.34mA   -11.89mA   -11.29mA
-318mV    -8.242mA   -8.458mA   -8.422mA
158mV     3.863mA    3.899mA    4mA
328mV     7.389mA    7.394mA    7.65mA
498mV     9.955mA    9.787mA    10.33mA
668mV     11.38mA    11.02mA    11.83mA
940mV     12.54mA    12.11mA    12.99mA
2.2V      15.4mA     15.07mA    15.64mA
[Pullup]
|Voltage   I(typ)   I(min)   I(max)
-1.1V     1.8nA      9.024nA    0A
296mV     -10.32uA   -12.39uA   -5.289uA
466mV     -538.9uA   -538.1uA   -421.8uA
602mV     -2.521mA   -2.744mA   -2.134mA
738mV     -5.508mA   -6.307mA   -4.628mA
976mV     -11.74mA   -13.85mA   -9.734mA
1.35V     -22.51mA   -26.87mA   -18.62mA
1.452V    -24.32mA   -29.17mA   -20.7mA
1.52V     -24.46mA   -29.71mA   -21.11mA
1.724V    -23.63mA   -29.56mA   -19.76mA
1.962V    -23.16mA   -29.18mA   -19.2mA
2.2V      -22.76mA   -27.35mA   -18.79mA
[GND_clamp]
|Voltage   I(typ)   I(min)   I(max)
-1.1V     -92.78mA   -80.14mA   -109.5mA
-1.031V   -81.73mA   -68.77mA   -97.17mA
-939mV    -68.18mA   -56.07mA   -81.64mA
-801mV    -48.85mA   -39.25mA   -59.15mA
-663mV    -30.71mA   -23.84mA   -37.89mA
-571mV    -19.76mA   -14.75mA   -24.85mA
-479mV    -10.5mA    -7.415mA   -13.5mA
-410mV    -5.313mA   -3.546mA   -6.916mA
-341mV    -2.007mA   -1.262mA   -2.59mA
-272mV    -506.9uA   -323.5uA   -609.8uA
-180mV    -45.65uA   -36.06uA   -43.55uA
1.1V      0A         0A         0A
[POWER_clamp]
|Voltage   I(typ)   I(min)   I(max)
-1.1V     5.691mA    8.066mA    3.44mA
-1.062V   3.709mA    5.665mA    2.092mA
-1.039V   2.781mA    4.457mA    1.546mA
-1.016V   2.086mA    3.48mA     1.193mA
-993mV    1.578mA    2.707mA    966.5uA
-970mV    1.21mA     2.107mA    818.5uA
-924mV    750.8uA    1.296mA    641.3uA
-878mV    507uA      821.4uA    530.2uA
-809mV    327.4uA    430uA      403.3uA
-694mV    178.4uA    161uA      233uA
-464mV    19.89uA    15.19uA    23.61uA
1.1V      0A         0A         0A
[Ramp]
| variable   typ   min   max
dV/dt_r   0.194/27.321p   0.192/34.735p   0.200/21.820p
dV/dt_f   0.320/41.913p   0.307/54.037p   0.341/34.362p
R_load = 50.000
[Rising Waveform]
R_fixture= 50.000
V_fixture= 1.100
V_fixture_min= 1.060
V_fixture_max= 1.170
|time   V(typ)   V(min)   V(max)
0s        567.3mV    547.9mV    601.6mV
146ps     568.2mV    548.4mV    600.9mV
203ps     569mV      548.1mV    948.8mV
271ps     936.4mV    535.5mV    1.117V
290ps     990mV      597.7mV    1.13V
331ps     1.054V     836mV      1.151V
366ps     1.078V     948.9mV    1.161V
419ps     1.087V     1.023V     1.167V
508ps     1.098V     1.053V     1.17V
3ns       1.1V       1.06V      1.17V
[Rising Waveform]
R_fixture= 50.000
V_fixture= 0.0
V_fixture_min= 0.0
V_fixture_max= 0.0
|time   V(typ)   V(min)   V(max)
0s        2.854uV    5.42uV     663.5nV
151ps     13.23uV    32.89uV    6.41mV
191ps     550.8uV    52.91uV    308.7mV
218ps     14.08mV    183.8uV    406.2mV
263ps     294mV      423.3uV    439.2mV
301ps     374.6mV    22.77mV    360.4mV
372ps     390.3mV    326.8mV    333.8mV
483ps     322.9mV    365.6mV    333.3mV
569ps     323.1mV    317.7mV    333.3mV
3ns       323.1mV    319.3mV    333.3mV
[Falling Waveform]
R_fixture= 50.000
V_fixture= 1.100
V_fixture_min= 1.060
V_fixture_max= 1.170
|time   V(typ)   V(min)   V(max)
0s        1.1V       1.06V      1.17V
159ps     1.1V       1.06V      1.165V
225ps     1.089V     1.06V      615.5mV
271ps     756.8mV    1.059V     498.1mV
315ps     547.2mV    1.048V     564.4mV
345ps     499.3mV    914.9mV    586.4mV
413ps     532.2mV    576.2mV    599.4mV
494ps     564.2mV    483.4mV    601.4mV
672ps     567.3mV    546.9mV    601.6mV
3ns       567.3mV    547.9mV    601.6mV
[Falling Waveform]
R_fixture= 50.000
V_fixture= 0.0
V_fixture_min= 0.0
V_fixture_max= 0.0
|time   V(typ)   V(min)   V(max)
0s        323.1mV    319.3mV    333.3mV
144ps     322.3mV    318.8mV    342.1mV
182ps     335.3mV    318.1mV    106.9mV
199ps     334.8mV    319.4mV    44.37mV
217ps     279.1mV    324.4mV    16.87mV
252ps     74.08mV    341.2mV    2.862mV
287ps     13.39mV    261.4mV    -4.151mV
345ps     1.034mV    51.02mV    -551.2uV
414ps     -2.872mV   2.772mV    -14.27uV
3ns       -992nV     4.761uV    -2.425uV
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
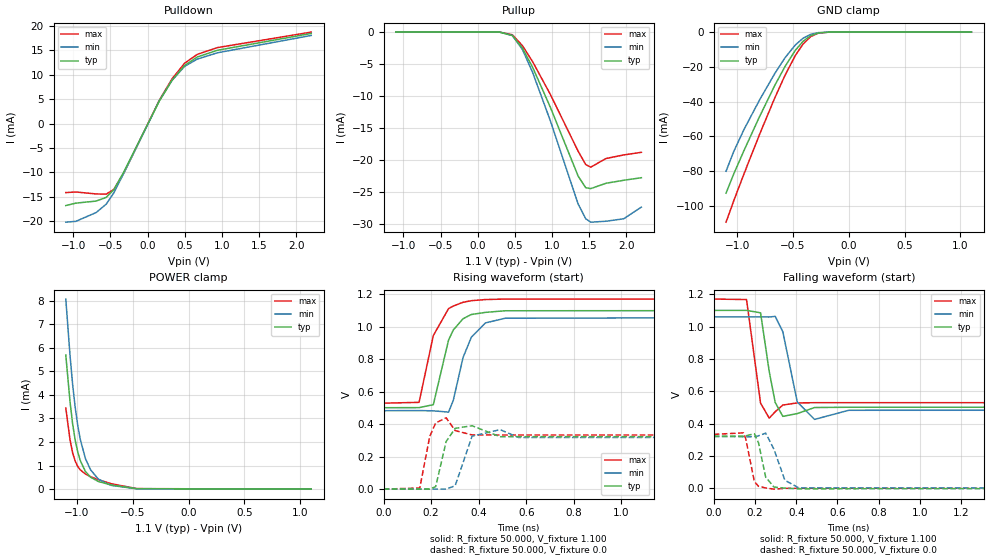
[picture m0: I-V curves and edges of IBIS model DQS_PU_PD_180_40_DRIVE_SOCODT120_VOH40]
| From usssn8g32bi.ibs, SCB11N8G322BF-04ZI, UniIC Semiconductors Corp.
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|   Model DQS_PU_PD_180_40_DRIVE_SOCODT120_VOH40
[Model] DQS_PU_PD_180_40_DRIVE_SOCODT120_VOH40
Model_type I/O
Polarity   Inverting
Vinl =  0.135V
Vinh =  0.305V
Vmeas =  0.220V
Rref =  50.000
Vref =  0.220V
C_comp   1.020pF   1.010pF   1.030pF
[Model Spec]
Vinh   0.305V   0.297V   0.319V
Vinl   0.135V   0.127V   0.149V
Vmeas   0.220V   0.212V   0.234V
Vref   0.220V   0.212V   0.234V
Rref   50.000   NA   NA
[Temperature Range]   25.000   85.000   -40.000
[Voltage Range]   1.100V   1.060V   1.170V
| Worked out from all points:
|   slope of the pulldown table from 0 to 0.165 V, typ, clamps not added: 34.3 ohm
|   GND clamp passes 1 mA (typ) near -0.30 V on its own axis
|   POWER clamp passes 1 mA (typ) near -0.95 V on its own axis
|   rising waveform, R_fixture 50.000, V_fixture 1.100: 20-80 % time 68.5ps typ, 72ps min, 67ps max; typ from 0.501 V to 1.1 V
|   rising waveform, R_fixture 50.000, V_fixture 0.0: 20-80 % time 27.1ps typ, 34.6ps min, 21.7ps max; typ from 0 V to 0.323 V
|   falling waveform, R_fixture 50.000, V_fixture 1.100: 20-80 % time 39.7ps typ, 51.4ps min, 32.7ps max; typ from 1.1 V to 0.501 V
|   falling waveform, R_fixture 50.000, V_fixture 0.0: 20-80 % time 31.7ps typ, 50.9ps min, 28ps max; typ from 0.323 V to 0 V
[Pulldown]
|Voltage   I(typ)   I(min)   I(max)
-1.1V     -16.81mA   -20.22mA   -14.15mA
-964mV    -16.31mA   -20.04mA   -14.03mA
-692mV    -15.89mA   -18.24mA   -14.43mA
-556mV    -15.13mA   -16.51mA   -14.47mA
-454mV    -13.55mA   -14.21mA   -13.5mA
-318mV    -9.863mA   -10.12mA   -10.07mA
158mV     4.627mA    4.669mA    4.79mA
328mV     8.852mA    8.857mA    9.163mA
498mV     11.93mA    11.73mA    12.38mA
668mV     13.64mA    13.21mA    14.18mA
940mV     15.03mA    14.51mA    15.57mA
2.2V      18.47mA    18.06mA    18.75mA
[Pullup]
|Voltage   I(typ)   I(min)   I(max)
-1.1V     1.8nA      9.024nA    0A
296mV     -10.32uA   -12.39uA   -5.289uA
466mV     -538.9uA   -538.1uA   -421.8uA
602mV     -2.521mA   -2.744mA   -2.134mA
738mV     -5.508mA   -6.307mA   -4.628mA
976mV     -11.74mA   -13.85mA   -9.734mA
1.35V     -22.51mA   -26.87mA   -18.62mA
1.452V    -24.32mA   -29.17mA   -20.7mA
1.52V     -24.46mA   -29.71mA   -21.11mA
1.724V    -23.63mA   -29.56mA   -19.76mA
1.962V    -23.16mA   -29.18mA   -19.2mA
2.2V      -22.76mA   -27.35mA   -18.79mA
[GND_clamp]
|Voltage   I(typ)   I(min)   I(max)
-1.1V     -92.78mA   -80.14mA   -109.5mA
-1.031V   -81.73mA   -68.77mA   -97.17mA
-939mV    -68.18mA   -56.07mA   -81.64mA
-801mV    -48.85mA   -39.25mA   -59.15mA
-663mV    -30.71mA   -23.84mA   -37.89mA
-571mV    -19.76mA   -14.75mA   -24.85mA
-479mV    -10.5mA    -7.415mA   -13.5mA
-410mV    -5.313mA   -3.546mA   -6.916mA
-341mV    -2.007mA   -1.262mA   -2.59mA
-272mV    -506.9uA   -323.5uA   -609.8uA
-180mV    -45.65uA   -36.06uA   -43.55uA
1.1V      0A         0A         0A
[POWER_clamp]
|Voltage   I(typ)   I(min)   I(max)
-1.1V     5.691mA    8.066mA    3.44mA
-1.062V   3.709mA    5.665mA    2.092mA
-1.039V   2.781mA    4.457mA    1.546mA
-1.016V   2.086mA    3.48mA     1.193mA
-993mV    1.578mA    2.707mA    966.5uA
-970mV    1.21mA     2.107mA    818.5uA
-924mV    750.8uA    1.296mA    641.3uA
-878mV    507uA      821.4uA    530.2uA
-809mV    327.4uA    430uA      403.3uA
-694mV    178.4uA    161uA      233uA
-464mV    19.89uA    15.19uA    23.61uA
1.1V      0A         0A         0A
[Ramp]
| variable   typ   min   max
dV/dt_r   0.194/27.236p   0.192/34.690p   0.200/21.801p
dV/dt_f   0.359/39.857p   0.346/51.560p   0.384/32.772p
R_load = 50.000
[Rising Waveform]
R_fixture= 50.000
V_fixture= 1.100
V_fixture_min= 1.060
V_fixture_max= 1.170
|time   V(typ)   V(min)   V(max)
0s        501.3mV    483mV      529.3mV
149ps     501.8mV    483.7mV    534.3mV
209ps     520.2mV    482.1mV    945.4mV
273ps     917mV      474.2mV    1.111V
293ps     979.4mV    546.3mV    1.127V
334ps     1.049V     809.9mV    1.15V
369ps     1.075V     935.1mV    1.16V
428ps     1.088V     1.023V     1.167V
511ps     1.098V     1.052V     1.17V
3ns       1.1V       1.06V      1.17V
[Rising Waveform]
R_fixture= 50.000
V_fixture= 0.0
V_fixture_min= 0.0
V_fixture_max= 0.0
|time   V(typ)   V(min)   V(max)
0s        2.565uV    4.869uV    595.6nV
152ps     79.31uV    34.8uV     7.356mV
194ps     718.4uV    78.2uV     325.1mV
219ps     15.46mV    291.8uV    407.6mV
263ps     293mV      492.8uV    439.3mV
301ps     374.5mV    21.12mV    360.4mV
372ps     390.4mV    326.1mV    333.8mV
490ps     322.9mV    366.4mV    333.3mV
568ps     323.1mV    317.8mV    333.3mV
3ns       323.1mV    319.3mV    333.3mV
[Falling Waveform]
R_fixture= 50.000
V_fixture= 1.100
V_fixture_min= 1.060
V_fixture_max= 1.170
|time   V(typ)   V(min)   V(max)
0s        1.1V       1.06V      1.17V
159ps     1.1V       1.06V      1.167V
227ps     1.085V     1.06V      526.6mV
269ps     722.5mV    1.059V     433.8mV
298ps     530.7mV    1.063V     473.2mV
335ps     444.7mV    968.4mV    514.6mV
405ps     461.9mV    534.1mV    527.9mV
489ps     499.3mV    425.8mV    529.2mV
655ps     501.2mV    482.3mV    529.3mV
3ns       501.3mV    483mV      529.3mV
[Falling Waveform]
R_fixture= 50.000
V_fixture= 0.0
V_fixture_min= 0.0
V_fixture_max= 0.0
|time   V(typ)   V(min)   V(max)
0s        323.1mV    319.3mV    333.3mV
144ps     322.3mV    318.8mV    342.8mV
155ps     324mV      318.5mV    307.5mV
197ps     337.3mV    319.1mV    41.28mV
217ps     281.3mV    324.4mV    12.49mV
252ps     68.21mV    341mV      1.893mV
292ps     7.794mV    241.3mV    -5.444mV
345ps     745.7uV    49.38mV    -513.9uV
413ps     -3.397mV   2.306mV    -8.427uV
3ns       2.284uV    3.074uV    241.6nV
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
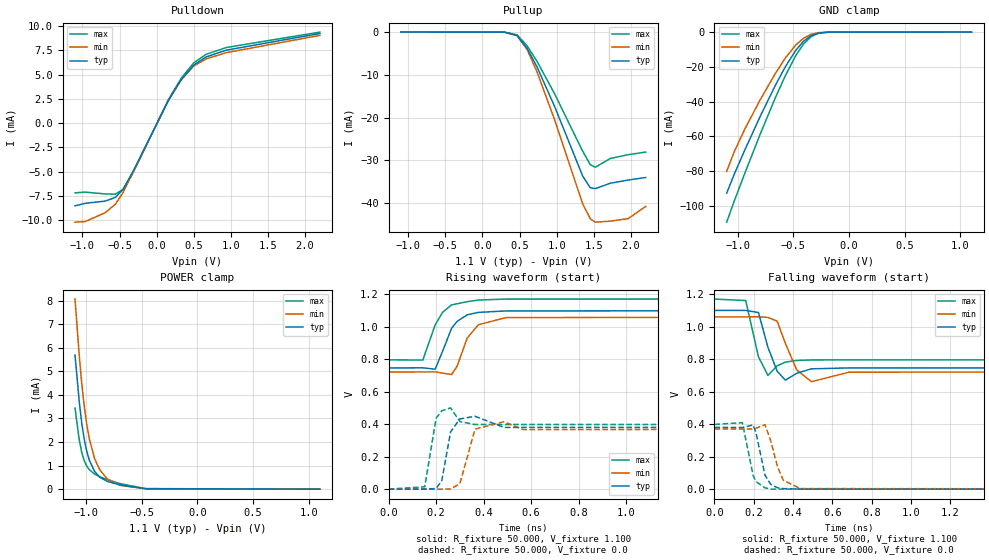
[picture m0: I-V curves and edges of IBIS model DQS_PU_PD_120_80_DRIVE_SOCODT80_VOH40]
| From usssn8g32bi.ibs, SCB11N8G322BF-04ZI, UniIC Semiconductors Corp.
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|   Model DQS_PU_PD_120_80_DRIVE_SOCODT80_VOH40
[Model] DQS_PU_PD_120_80_DRIVE_SOCODT80_VOH40
Model_type I/O
Polarity   Inverting
Vinl =  0.135V
Vinh =  0.305V
Vmeas =  0.220V
Rref =  50.000
Vref =  0.220V
C_comp   1.020pF   1.010pF   1.030pF
[Model Spec]
Vinh   0.305V   0.297V   0.319V
Vinl   0.135V   0.127V   0.149V
Vmeas   0.220V   0.212V   0.234V
Vref   0.220V   0.212V   0.234V
Rref   50.000   NA   NA
[Temperature Range]   25.000   85.000   -40.000
[Voltage Range]   1.100V   1.060V   1.170V
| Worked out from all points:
|   slope of the pulldown table from 0 to 0.165 V, typ, clamps not added: 68.2 ohm
|   GND clamp passes 1 mA (typ) near -0.30 V on its own axis
|   POWER clamp passes 1 mA (typ) near -0.95 V on its own axis
|   rising waveform, R_fixture 50.000, V_fixture 1.100: 20-80 % time 64.8ps typ, 65.9ps min, 65.4ps max; typ from 0.746 V to 1.1 V
|   rising waveform, R_fixture 50.000, V_fixture 0.0: 20-80 % time 25.7ps typ, 33.5ps min, 20.3ps max; typ from 0 V to 0.38 V
|   falling waveform, R_fixture 50.000, V_fixture 1.100: 20-80 % time 45.1ps typ, 58.4ps min, 36.5ps max; typ from 1.1 V to 0.746 V
|   falling waveform, R_fixture 50.000, V_fixture 0.0: 20-80 % time 41.6ps typ, 54.4ps min, 38.8ps max; typ from 0.38 V to 0 V
[Pulldown]
|Voltage   I(typ)   I(min)   I(max)
-1.1V     -8.531mA   -10.21mA   -7.187mA
-964mV    -8.264mA   -10.15mA   -7.109mA
-692mV    -8.033mA   -9.227mA   -7.298mA
-556mV    -7.649mA   -8.349mA   -7.316mA
-454mV    -6.852mA   -7.181mA   -6.833mA
-318mV    -4.969mA   -5.097mA   -5.081mA
158mV     2.325mA    2.347mA    2.407mA
328mV     4.444mA    4.448mA    4.602mA
498mV     5.984mA    5.884mA    6.211mA
668mV     6.835mA    6.624mA    7.108mA
940mV     7.53mA     7.275mA    7.801mA
2.2V      9.253mA    9.055mA    9.394mA
[Pullup]
|Voltage   I(typ)   I(min)   I(max)
-1.1V     2.7nA      13.54nA    0A
296mV     -15.48uA   -18.58uA   -7.934uA
466mV     -807.4uA   -806.2uA   -632uA
602mV     -3.772mA   -4.103mA   -3.194mA
738mV     -8.234mA   -9.422mA   -6.922mA
976mV     -17.54mA   -20.68mA   -14.55mA
1.35V     -33.63mA   -40.11mA   -27.84mA
1.452V    -36.39mA   -43.62mA   -30.97mA
1.52V     -36.62mA   -44.46mA   -31.62mA
1.724V    -35.34mA   -44.21mA   -29.55mA
1.962V    -34.61mA   -43.64mA   -28.68mA
2.2V      -34.01mA   -40.78mA   -28.06mA
[GND_clamp]
|Voltage   I(typ)   I(min)   I(max)
-1.1V     -92.78mA   -80.14mA   -109.5mA
-1.031V   -81.73mA   -68.77mA   -97.17mA
-939mV    -68.18mA   -56.07mA   -81.64mA
-801mV    -48.85mA   -39.25mA   -59.15mA
-663mV    -30.71mA   -23.84mA   -37.89mA
-571mV    -19.76mA   -14.75mA   -24.85mA
-479mV    -10.5mA    -7.415mA   -13.5mA
-410mV    -5.313mA   -3.546mA   -6.916mA
-341mV    -2.007mA   -1.262mA   -2.59mA
-272mV    -506.9uA   -323.5uA   -609.8uA
-180mV    -45.65uA   -36.06uA   -43.55uA
1.1V      0A         0A         0A
[POWER_clamp]
|Voltage   I(typ)   I(min)   I(max)
-1.1V     5.691mA    8.066mA    3.44mA
-1.062V   3.709mA    5.665mA    2.092mA
-1.039V   2.781mA    4.457mA    1.546mA
-1.016V   2.086mA    3.48mA     1.193mA
-993mV    1.578mA    2.707mA    966.5uA
-970mV    1.21mA     2.107mA    818.5uA
-924mV    750.8uA    1.296mA    641.3uA
-878mV    507uA      821.4uA    530.2uA
-809mV    327.4uA    430uA      403.3uA
-694mV    178.4uA    161uA      233uA
-464mV    19.89uA    15.19uA    23.61uA
1.1V      0A         0A         0A
[Ramp]
| variable   typ   min   max
dV/dt_r   0.228/25.858p   0.222/33.564p   0.239/20.550p
dV/dt_f   0.212/45.175p   0.203/58.359p   0.225/36.539p
R_load = 50.000
[Rising Waveform]
R_fixture= 50.000
V_fixture= 1.100
V_fixture_min= 1.060
V_fixture_max= 1.170
|time   V(typ)   V(min)   V(max)
0s        746mV      721mV      795.6mV
144ps     746.8mV    721.4mV    794.5mV
196ps     738.3mV    721.8mV    1.011V
227ps     847.5mV    714.1mV    1.088V
265ps     989.5mV    705.4mV    1.134V
288ps     1.032V     755.8mV    1.141V
331ps     1.073V     929.8mV    1.154V
378ps     1.088V     1.012V     1.164V
495ps     1.097V     1.056V     1.17V
3ns       1.1V       1.06V      1.17V
[Rising Waveform]
R_fixture= 50.000
V_fixture= 0.0
V_fixture_min= 0.0
V_fixture_max= 0.0
|time   V(typ)   V(min)   V(max)
0s        3.687uV    7.015uV    860.8nV
152ps     -280.7uV   57.33uV    14.17mV
200ps     3.593mV    -157.9uV   436mV
224ps     52.52mV    -310.5uV   482.3mV
261ps     352.4mV    727.5uV    500.1mV
300ps     432.1mV    33.68mV    415.9mV
364ps     448.4mV    369.8mV    397.5mV
486ps     379.6mV    415mV      397.7mV
567ps     379.9mV    366.3mV    397.7mV
3ns       379.9mV    370mV      397.7mV
[Falling Waveform]
R_fixture= 50.000
V_fixture= 1.100
V_fixture_min= 1.060
V_fixture_max= 1.170
|time   V(typ)   V(min)   V(max)
0s        1.1V       1.06V      1.17V
159ps     1.1V       1.06V      1.161V
224ps     1.087V     1.061V     814.3mV
272ps     873mV      1.057V     699.7mV
319ps     725.5mV    1.034V     758.6mV
361ps     670.7mV    896.6mV    781.8mV
418ps     712.6mV    734.5mV    791.8mV
493ps     740.2mV    660.9mV    794.9mV
685ps     745.9mV    719.7mV    795.6mV
3ns       746mV      721mV      795.6mV
[Falling Waveform]
R_fixture= 50.000
V_fixture= 0.0
V_fixture_min= 0.0
V_fixture_max= 0.0
|time   V(typ)   V(min)   V(max)
0s        379.9mV    370mV      397.7mV
142ps     378.9mV    369.5mV    408.9mV
197ps     394.7mV    370mV      82.57mV
212ps     343.6mV    374.6mV    45.43mV
257ps     86.1mV     396.5mV    7.385mV
286ps     29mV       298.7mV    -874.3uV
320ps     8.089mV    141.1mV    -921.1uV
350ps     2.714mV    54.21mV    -297.6uV
437ps     -854.6uV   2.762mV    -9.777uV
3ns       3.47uV     6.942uV    689nV
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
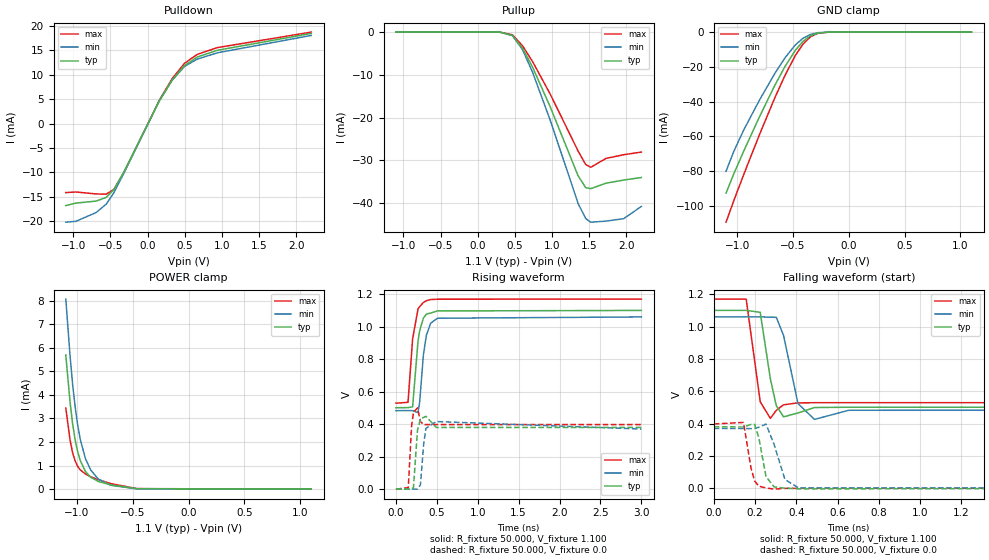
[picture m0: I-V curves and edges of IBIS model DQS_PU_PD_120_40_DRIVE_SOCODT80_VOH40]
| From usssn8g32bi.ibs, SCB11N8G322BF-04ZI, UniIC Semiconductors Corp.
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|   Model DQS_PU_PD_120_40_DRIVE_SOCODT80_VOH40
[Model] DQS_PU_PD_120_40_DRIVE_SOCODT80_VOH40
Model_type I/O
Polarity   Inverting
Vinl =  0.135V
Vinh =  0.305V
Vmeas =  0.220V
Rref =  50.000
Vref =  0.220V
C_comp   1.020pF   1.010pF   1.030pF
[Model Spec]
Vinh   0.305V   0.297V   0.319V
Vinl   0.135V   0.127V   0.149V
Vmeas   0.220V   0.212V   0.234V
Vref   0.220V   0.212V   0.234V
Rref   50.000   NA   NA
[Temperature Range]   25.000   85.000   -40.000
[Voltage Range]   1.100V   1.060V   1.170V
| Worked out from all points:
|   slope of the pulldown table from 0 to 0.165 V, typ, clamps not added: 34.3 ohm
|   GND clamp passes 1 mA (typ) near -0.30 V on its own axis
|   POWER clamp passes 1 mA (typ) near -0.95 V on its own axis
|   rising waveform, R_fixture 50.000, V_fixture 1.100: 20-80 % time 67.9ps typ, 70.9ps min, 66.9ps max; typ from 0.501 V to 1.1 V
|   rising waveform, R_fixture 50.000, V_fixture 0.0: 20-80 % time 25.4ps typ, 32.9ps min, 20.2ps max; typ from 0 V to 0.38 V
|   falling waveform, R_fixture 50.000, V_fixture 1.100: 20-80 % time 39.9ps typ, 51.9ps min, 32.9ps max; typ from 1.1 V to 0.501 V
|   falling waveform, R_fixture 50.000, V_fixture 0.0: 20-80 % time 32.5ps typ, 50.8ps min, 28.6ps max; typ from 0.38 V to 0 V
[Pulldown]
|Voltage   I(typ)   I(min)   I(max)
-1.1V     -16.81mA   -20.22mA   -14.15mA
-964mV    -16.31mA   -20.04mA   -14.03mA
-692mV    -15.89mA   -18.24mA   -14.43mA
-556mV    -15.13mA   -16.51mA   -14.47mA
-454mV    -13.55mA   -14.21mA   -13.5mA
-318mV    -9.863mA   -10.12mA   -10.07mA
158mV     4.627mA    4.669mA    4.79mA
328mV     8.852mA    8.857mA    9.163mA
498mV     11.93mA    11.73mA    12.38mA
668mV     13.64mA    13.21mA    14.18mA
940mV     15.03mA    14.51mA    15.57mA
2.2V      18.47mA    18.06mA    18.75mA
[Pullup]
|Voltage   I(typ)   I(min)   I(max)
-1.1V     2.7nA      13.54nA    0A
296mV     -15.48uA   -18.58uA   -7.934uA
466mV     -807.4uA   -806.2uA   -632uA
602mV     -3.772mA   -4.103mA   -3.194mA
738mV     -8.234mA   -9.422mA   -6.922mA
976mV     -17.54mA   -20.68mA   -14.55mA
1.35V     -33.63mA   -40.11mA   -27.84mA
1.452V    -36.39mA   -43.62mA   -30.97mA
1.52V     -36.62mA   -44.46mA   -31.62mA
1.724V    -35.34mA   -44.21mA   -29.55mA
1.962V    -34.61mA   -43.64mA   -28.68mA
2.2V      -34.01mA   -40.78mA   -28.06mA
[GND_clamp]
|Voltage   I(typ)   I(min)   I(max)
-1.1V     -92.78mA   -80.14mA   -109.5mA
-1.031V   -81.73mA   -68.77mA   -97.17mA
-939mV    -68.18mA   -56.07mA   -81.64mA
-801mV    -48.85mA   -39.25mA   -59.15mA
-663mV    -30.71mA   -23.84mA   -37.89mA
-571mV    -19.76mA   -14.75mA   -24.85mA
-479mV    -10.5mA    -7.415mA   -13.5mA
-410mV    -5.313mA   -3.546mA   -6.916mA
-341mV    -2.007mA   -1.262mA   -2.59mA
-272mV    -506.9uA   -323.5uA   -609.8uA
-180mV    -45.65uA   -36.06uA   -43.55uA
1.1V      0A         0A         0A
[POWER_clamp]
|Voltage   I(typ)   I(min)   I(max)
-1.1V     5.691mA    8.066mA    3.44mA
-1.062V   3.709mA    5.665mA    2.092mA
-1.039V   2.781mA    4.457mA    1.546mA
-1.016V   2.086mA    3.48mA     1.193mA
-993mV    1.578mA    2.707mA    966.5uA
-970mV    1.21mA     2.107mA    818.5uA
-924mV    750.8uA    1.296mA    641.3uA
-878mV    507uA      821.4uA    530.2uA
-809mV    327.4uA    430uA      403.3uA
-694mV    178.4uA    161uA      233uA
-464mV    19.89uA    15.19uA    23.61uA
1.1V      0A         0A         0A
[Ramp]
| variable   typ   min   max
dV/dt_r   0.228/25.558p   0.222/32.903p   0.239/20.493p
dV/dt_f   0.359/40.018p   0.346/51.934p   0.384/32.895p
R_load = 50.000
[Rising Waveform]
R_fixture= 50.000
V_fixture= 1.100
V_fixture_min= 1.060
V_fixture_max= 1.170
|time   V(typ)   V(min)   V(max)
0s        501.3mV    483mV      529.3mV
148ps     501.8mV    483.6mV    534.5mV
204ps     506.7mV    483mV      925mV
270ps     910.3mV    471.2mV    1.109V
290ps     975mV      534.3mV    1.124V
336ps     1.053V     826.9mV    1.149V
372ps     1.077V     947mV      1.16V
425ps     1.084V     1.022V     1.167V
509ps     1.097V     1.052V     1.169V
3ns       1.1V       1.06V      1.17V
[Rising Waveform]
R_fixture= 50.000
V_fixture= 0.0
V_fixture_min= 0.0
V_fixture_max= 0.0
|time   V(typ)   V(min)   V(max)
0s        2.565uV    4.869uV    595.6nV
151ps     -53.18uV   50.02uV    9.314mV
191ps     858.7uV    37.73uV    385.9mV
214ps     9.532mV    84.84uV    471.1mV
264ps     363.6mV    987.8uV    500.6mV
300ps     432.2mV    27.21mV    415.9mV
339ps     441.9mV    277.6mV    397.5mV
367ps     448.1mV    374.2mV    397.5mV
493ps     379.7mV    416mV      397.7mV
3ns       379.9mV    370mV      397.7mV
[Falling Waveform]
R_fixture= 50.000
V_fixture= 1.100
V_fixture_min= 1.060
V_fixture_max= 1.170
|time   V(typ)   V(min)   V(max)
0s        1.1V       1.06V      1.17V
157ps     1.1V       1.06V      1.17V
225ps     1.088V     1.06V      535.7mV
274ps     677.8mV    1.058V     432.4mV
303ps     510.1mV    1.057V     482.2mV
338ps     441.8mV    945.3mV    516.2mV
408ps     465.7mV    523.7mV    528.1mV
488ps     499.2mV    425.9mV    529.2mV
654ps     501.2mV    482.3mV    529.3mV
3ns       501.3mV    483mV      529.3mV
[Falling Waveform]
R_fixture= 50.000
V_fixture= 0.0
V_fixture_min= 0.0
V_fixture_max= 0.0
|time   V(typ)   V(min)   V(max)
0s        379.9mV    370mV      397.7mV
144ps     379mV      369.4mV    407.2mV
181ps     395.2mV    368.6mV    121.8mV
198ps     394.9mV    370.1mV    44.79mV
218ps     315mV      377.2mV    13.39mV
253ps     72.71mV    397.1mV    1.974mV
292ps     8.613mV    271.6mV    -5.504mV
345ps     782.1uV    53.73mV    -511.9uV
411ps     -3.562mV   2.633mV    -10.78uV
3ns       2.294uV    4.683uV    381.5nV
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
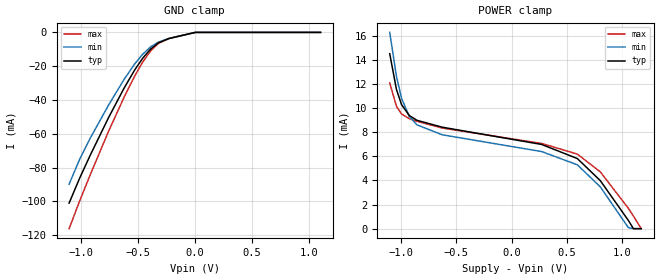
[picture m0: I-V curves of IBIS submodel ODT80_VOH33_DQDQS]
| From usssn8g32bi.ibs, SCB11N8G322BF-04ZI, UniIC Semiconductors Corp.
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|   Submodel ODT80_VOH33_DQDQS
[Submodel] ODT80_VOH33_DQDQS
Submodel_type Dynamic_clamp
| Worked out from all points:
|   GND clamp passes 1 mA (typ) near -0.07 V on its own axis
[GND_clamp]
|Voltage   I(typ)   I(min)   I(max)
-1.1V     -101mA     -89.8mA    -116.1mA
-1.008V   -86.27mA   -75.1mA    -99.79mA
-916mV    -72.78mA   -62.69mA   -84.37mA
-755mV    -50.45mA   -43.02mA   -58.55mA
-617mV    -32.73mA   -27.6mA    -38.05mA
-525mV    -22.11mA   -18.56mA   -25.68mA
-456mV    -15.27mA   -12.9mA    -17.54mA
-387mV    -9.839mA   -8.569mA   -10.96mA
-318mV    -6.17mA    -5.735mA   -6.492mA
-226mV    -3.608mA   -3.588mA   -3.616mA
4mV       0A         0A         0A
1.1V      0A         0A         0A
[POWER_clamp]
|Voltage   I(typ)   I(min)   I(max)
-1.1V     14.53mA    16.3mA     12.1mA
-1.039V   11.55mA    12.63mA    10.15mA
-993mV    10.3mA     10.82mA    9.527mA
-924mV    9.397mA    9.337mA    9.137mA
-855mV    9.001mA    8.623mA    8.915mA
-625mV    8.424mA    7.793mA    8.354mA
272mV     6.992mA    6.403mA    7.078mA
594mV     5.821mA    5.301mA    6.188mA
801mV     3.988mA    3.471mA    4.717mA
1.054V    686uA      90.34uA    1.695mA
1.1V      0A         0A         1.042mA
1.17V     0A         0A         0A
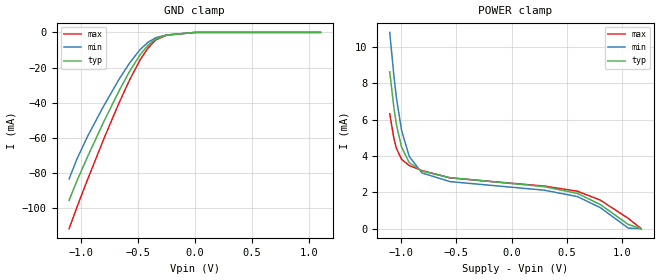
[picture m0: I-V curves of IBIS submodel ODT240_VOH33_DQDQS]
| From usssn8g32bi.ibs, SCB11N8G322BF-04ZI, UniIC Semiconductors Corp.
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|   Submodel ODT240_VOH33_DQDQS
[Submodel] ODT240_VOH33_DQDQS
Submodel_type Dynamic_clamp
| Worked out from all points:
|   GND clamp passes 1 mA (typ) near -0.19 V on its own axis
[GND_clamp]
|Voltage   I(typ)   I(min)   I(max)
-1.1V     -95.43mA   -83.28mA   -111.6mA
-1.031V   -84.34mA   -71.92mA   -99.29mA
-939mV    -70.75mA   -59.19mA   -83.75mA
-801mV    -51.4mA    -42.25mA   -61.29mA
-663mV    -33.23mA   -26.68mA   -40.09mA
-571mV    -22.2mA    -17.42mA   -27.07mA
-479mV    -12.76mA   -9.79mA    -15.65mA
-410mV    -7.335mA   -5.624mA   -8.889mA
-341mV    -3.721mA   -3.006mA   -4.283mA
-249mV    -1.556mA   -1.469mA   -1.597mA
4mV       0A         0A         0A
1.1V      0A         0A         0A
[POWER_clamp]
|Voltage   I(typ)   I(min)   I(max)
-1.1V     8.639mA    10.81mA    6.328mA
-1.062V   6.643mA    8.398mA    4.968mA
-1.039V   5.707mA    7.182mA    4.415mA
-993mV    4.487mA    5.414mA    3.821mA
-924mV    3.635mA    3.978mA    3.475mA
-809mV    3.169mA    3.069mA    3.2mA
-556mV    2.809mA    2.591mA    2.796mA
295mV     2.315mA    2.119mA    2.346mA
594mV     1.941mA    1.767mA    2.063mA
801mV     1.329mA    1.157mA    1.572mA
1.054V    228.6uA    29.96uA    564.7uA
1.17V     0A         0A         0A
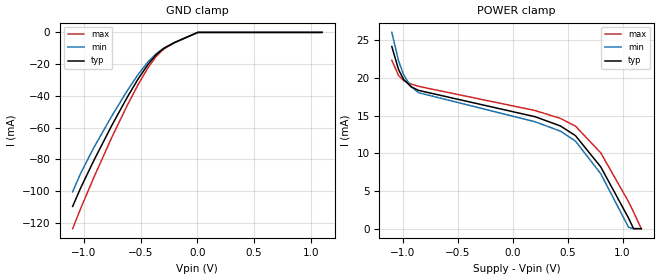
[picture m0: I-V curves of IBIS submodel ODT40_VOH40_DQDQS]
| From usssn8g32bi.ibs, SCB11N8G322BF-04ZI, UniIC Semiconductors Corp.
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|   Submodel ODT40_VOH40_DQDQS
[Submodel] ODT40_VOH40_DQDQS
Submodel_type Dynamic_clamp
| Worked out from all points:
|   GND clamp passes 1 mA (typ) near -0.03 V on its own axis
[GND_clamp]
|Voltage   I(typ)   I(min)   I(max)
-1.1V     -109.6mA   -100.4mA   -123.6mA
-1.031V   -98.25mA   -89.03mA   -111.2mA
-916mV    -81.1mA    -72.93mA   -91.86mA
-755mV    -58.65mA   -52.71mA   -66.17mA
-617mV    -40.67mA   -36.56mA   -45.77mA
-525mV    -29.62mA   -26.73mA   -33.2mA
-433mV    -19.92mA   -18.29mA   -21.99mA
-364mV    -14.12mA   -13.41mA   -15.18mA
-295mV    -10mA      -9.917mA   -10.42mA
-203mV    -6.404mA   -6.51mA    -6.581mA
4mV       0A         0A         0A
1.1V      0A         0A         0A
[POWER_clamp]
|Voltage   I(typ)   I(min)   I(max)
-1.1V     24.16mA    26.03mA    22.33mA
-1.039V   21.11mA    22.27mA    20.32mA
-993mV    19.8mA     20.41mA    19.64mA
-924mV    18.81mA    18.83mA    19.18mA
-855mV    18.33mA    18.02mA    18.87mA
203mV     14.85mA    14.18mA    15.67mA
433mV     13.63mA    12.94mA    14.63mA
571mV     12.34mA    11.62mA    13.6mA
801mV     8.2mA      7.286mA    10.06mA
1.054V    1.403mA    187.6uA    3.575mA
1.1V      0A         0A         2.194mA
1.17V     0A         0A         0A
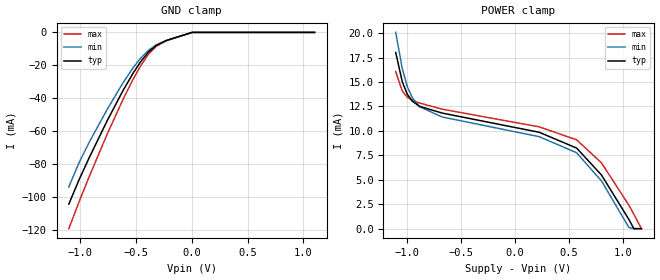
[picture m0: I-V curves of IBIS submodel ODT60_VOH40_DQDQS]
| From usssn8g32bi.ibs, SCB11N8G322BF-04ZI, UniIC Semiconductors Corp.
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|   Submodel ODT60_VOH40_DQDQS
[Submodel] ODT60_VOH40_DQDQS
Submodel_type Dynamic_clamp
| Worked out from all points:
|   GND clamp passes 1 mA (typ) near -0.05 V on its own axis
[GND_clamp]
|Voltage   I(typ)   I(min)   I(max)
-1.1V     -104.1mA   -93.66mA   -119mA
-1.008V   -89.29mA   -78.93mA   -102.7mA
-916mV    -75.75mA   -66.42mA   -87.23mA
-755mV    -53.36mA   -46.52mA   -61.46mA
-617mV    -35.53mA   -30.81mA   -40.96mA
-525mV    -24.75mA   -21.48mA   -28.48mA
-456mV    -17.69mA   -15.52mA   -20.16mA
-387mV    -11.96mA   -10.83mA   -13.28mA
-318mV    -7.935mA   -7.608mA   -8.44mA
-226mV    -4.87mA    -4.922mA   -5.014mA
4mV       0A         0A         0A
1.1V      0A         0A         0A
[POWER_clamp]
|Voltage   I(typ)   I(min)   I(max)
-1.1V     18.02mA    20.07mA    16.06mA
-1.039V   15.02mA    16.36mA    14.08mA
-993mV    13.75mA    14.53mA    13.44mA
-947mV    13.04mA    13.4mA     13.12mA
-878mV    12.5mA     12.46mA    12.84mA
-671mV    11.82mA    11.42mA    12.22mA
226mV     9.854mA    9.404mA    10.41mA
571mV     8.241mA    7.764mA    9.085mA
801mV     5.483mA    4.874mA    6.727mA
1.054V    939uA      125.5uA    2.392mA
1.1V      0A         0A         1.468mA
1.17V     0A         0A         0A
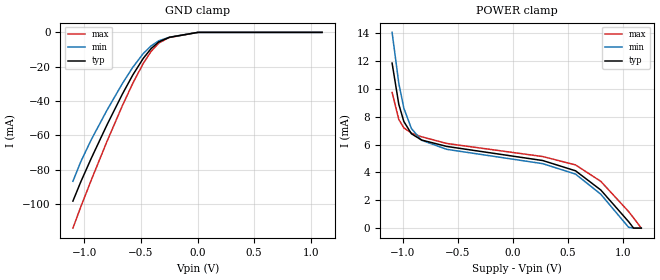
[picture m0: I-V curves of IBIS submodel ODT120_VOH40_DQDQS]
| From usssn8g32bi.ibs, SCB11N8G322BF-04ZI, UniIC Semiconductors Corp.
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|   Submodel ODT120_VOH40_DQDQS
[Submodel] ODT120_VOH40_DQDQS
Submodel_type Dynamic_clamp
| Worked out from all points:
|   GND clamp passes 1 mA (typ) near -0.10 V on its own axis
[GND_clamp]
|Voltage   I(typ)   I(min)   I(max)
-1.1V     -98.34mA   -86.81mA   -114.1mA
-1.031V   -87.19mA   -75.46mA   -101.8mA
-939mV    -73.55mA   -62.67mA   -86.27mA
-801mV    -54.16mA   -45.57mA   -63.83mA
-663mV    -35.94mA   -29.79mA   -42.68mA
-571mV    -24.81mA   -20.32mA   -29.64mA
-479mV    -15.16mA   -12.36mA   -18.1mA
-410mV    -9.473mA   -7.868mA   -11.11mA
-341mV    -5.528mA   -4.886mA   -6.177mA
-249mV    -2.884mA   -2.844mA   -2.997mA
4mV       0A         0A         0A
1.1V      0A         0A         0A
[POWER_clamp]
|Voltage   I(typ)   I(min)   I(max)
-1.1V     11.86mA    14.07mA    9.751mA
-1.039V   8.903mA    10.41mA    7.815mA
-993mV    7.664mA    8.624mA    7.204mA
-924mV    6.784mA    7.157mA    6.832mA
-832mV    6.334mA    6.315mA    6.569mA
-602mV    5.872mA    5.663mA    6.085mA
272mV     4.859mA    4.634mA    5.145mA
571mV     4.121mA    3.883mA    4.544mA
801mV     2.741mA    2.437mA    3.364mA
1.054V    469.4uA    62.65uA    1.196mA
1.1V      0A         0A         734uA
1.17V     0A         0A         0A
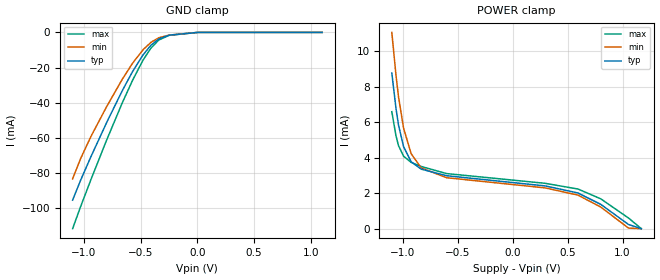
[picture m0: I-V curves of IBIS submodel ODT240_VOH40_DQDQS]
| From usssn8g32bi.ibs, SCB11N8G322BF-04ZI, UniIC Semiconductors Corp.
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|   Submodel ODT240_VOH40_DQDQS
[Submodel] ODT240_VOH40_DQDQS
Submodel_type Dynamic_clamp
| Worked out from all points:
|   GND clamp passes 1 mA (typ) near -0.18 V on its own axis
[GND_clamp]
|Voltage   I(typ)   I(min)   I(max)
-1.1V     -95.54mA   -83.45mA   -111.8mA
-1.031V   -84.44mA   -72.09mA   -99.48mA
-939mV    -70.85mA   -59.35mA   -83.94mA
-801mV    -51.49mA   -42.39mA   -61.48mA
-663mV    -33.31mA   -26.8mA    -40.27mA
-571mV    -22.27mA   -17.52mA   -27.23mA
-479mV    -12.82mA   -9.882mA   -15.79mA
-410mV    -7.388mA   -5.704mA   -9.005mA
-341mV    -3.766mA   -3.074mA   -4.381mA
-249mV    -1.59mA    -1.52mA    -1.67mA
4mV       0A         0A         0A
1.1V      0A         0A         0A
[POWER_clamp]
|Voltage   I(typ)   I(min)   I(max)
-1.1V     8.777mA    11.07mA    6.598mA
-1.062V   6.78mA     8.655mA    5.237mA
-1.039V   5.844mA    7.438mA    4.682mA
-993mV    4.623mA    5.668mA    4.087mA
-924mV    3.769mA    4.229mA    3.739mA
-832mV    3.355mA    3.426mA    3.508mA
-602mV    2.986mA    2.873mA    3.107mA
295mV     2.412mA    2.3mA      2.558mA
594mV     2.013mA    1.892mA    2.235mA
801mV     1.372mA    1.22mA     1.684mA
1.054V    234.9uA    31.26uA    598.8uA
1.17V     0A         0A         0A
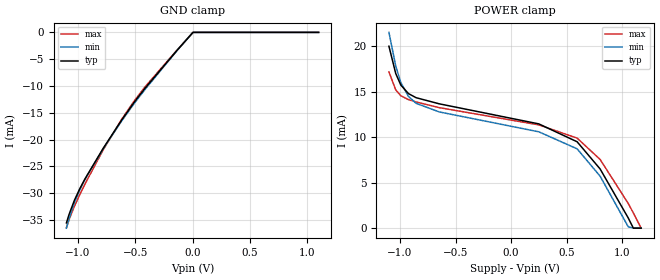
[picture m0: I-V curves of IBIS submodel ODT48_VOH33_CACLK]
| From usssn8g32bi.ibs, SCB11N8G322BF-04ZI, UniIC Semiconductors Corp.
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|   Submodel ODT48_VOH33_CACLK
[Submodel] ODT48_VOH33_CACLK
Submodel_type Dynamic_clamp
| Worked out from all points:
|   GND clamp passes 1 mA (typ) near -0.04 V on its own axis
[GND_clamp]
|Voltage   I(typ)   I(min)   I(max)
-1.1V     -35.54mA   -36.51mA   -36.41mA
-1.077V   -33.95mA   -34.76mA   -34.94mA
-1.031V   -31.34mA   -31.82mA   -32.46mA
-985mV    -29.22mA   -29.45mA   -30.32mA
-939mV    -27.35mA   -27.46mA   -28.32mA
-778mV    -21.58mA   -21.67mA   -21.85mA
-617mV    -16.31mA   -16.48mA   -16.17mA
-502mV    -12.83mA   -13.05mA   -12.59mA
-410mV    -10.3mA    -10.53mA   -10.05mA
-134mV    -3.325mA   -3.372mA   -3.269mA
4mV       0A         0A         0A
1.1V      0A         0A         0A
[POWER_clamp]
|Voltage   I(typ)   I(min)   I(max)
-1.1V     20.02mA    21.54mA    17.19mA
-1.039V   17.02mA    17.85mA    15.21mA
-993mV    15.74mA    16.02mA    14.57mA
-924mV    14.8mA     14.49mA    14.14mA
-855mV    14.35mA    13.73mA    13.88mA
-648mV    13.68mA    12.79mA    13.26mA
249mV     11.47mA    10.6mA     11.36mA
594mV     9.5mA      8.725mA    9.903mA
801mV     6.507mA    5.713mA    7.553mA
1.054V    1.118mA    148.9uA    2.711mA
1.1V      0A         0A         1.666mA
1.17V     0A         0A         0A
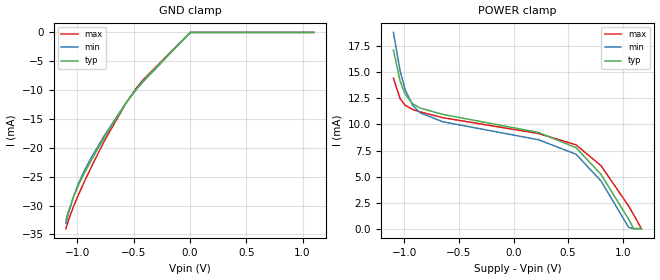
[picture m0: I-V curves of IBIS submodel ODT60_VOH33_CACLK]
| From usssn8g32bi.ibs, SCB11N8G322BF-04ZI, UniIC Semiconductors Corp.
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|   Submodel ODT60_VOH33_CACLK
[Submodel] ODT60_VOH33_CACLK
Submodel_type Dynamic_clamp
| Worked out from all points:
|   GND clamp passes 1 mA (typ) near -0.05 V on its own axis
[GND_clamp]
|Voltage   I(typ)   I(min)   I(max)
-1.1V     -32.52mA   -33.09mA   -33.99mA
-1.077V   -30.95mA   -31.32mA   -32.52mA
-1.031V   -28.38mA   -28.35mA   -30.07mA
-985mV    -26.3mA    -25.99mA   -27.95mA
-939mV    -24.48mA   -24.03mA   -25.96mA
-870mV    -21.97mA   -21.51mA   -23.12mA
-755mV    -18.06mA   -17.75mA   -18.66mA
-571mV    -12.34mA   -12.31mA   -12.38mA
-479mV    -9.867mA   -9.986mA   -9.744mA
-410mV    -8.273mA   -8.434mA   -8.091mA
4mV       0A         0A         0A
1.1V      0A         0A         0A
[POWER_clamp]
|Voltage   I(typ)   I(min)   I(max)
-1.1V     17.15mA    18.84mA    14.44mA
-1.039V   14.18mA    15.17mA    12.48mA
-993mV    12.91mA    13.36mA    11.85mA
-924mV    11.99mA    11.85mA    11.44mA
-855mV    11.57mA    11.11mA    11.21mA
-648mV    10.97mA    10.26mA    10.65mA
226mV     9.239mA    8.541mA    9.14mA
571mV     7.781mA    7.154mA    8.051mA
801mV     5.205mA    4.57mA     6.042mA
1.054V    894.2uA    119.1uA    2.168mA
1.1V      0A         0A         1.332mA
1.17V     0A         0A         0A
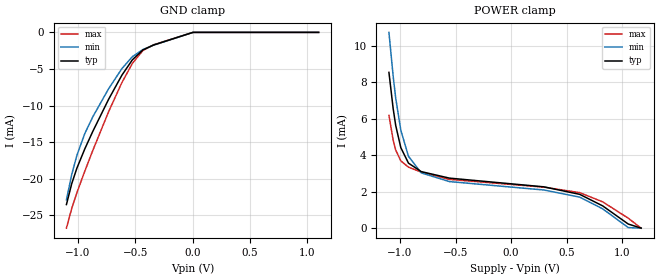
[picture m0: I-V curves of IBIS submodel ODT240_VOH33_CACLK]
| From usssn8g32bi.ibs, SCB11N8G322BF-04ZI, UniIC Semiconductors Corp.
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|   Submodel ODT240_VOH33_CACLK
[Submodel] ODT240_VOH33_CACLK
Submodel_type Dynamic_clamp
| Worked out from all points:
|   GND clamp passes 1 mA (typ) near -0.20 V on its own axis
[GND_clamp]
|Voltage   I(typ)   I(min)   I(max)
-1.1V     -23.51mA   -22.87mA   -26.73mA
-1.054V   -20.67mA   -19.42mA   -24.05mA
-1.008V   -18.51mA   -16.75mA   -21.86mA
-939mV    -15.88mA   -13.79mA   -18.92mA
-870mV    -13.52mA   -11.53mA   -16.12mA
-732mV    -9.135mA   -7.694mA   -10.83mA
-617mV    -5.867mA   -4.966mA   -6.877mA
-525mV    -3.749mA   -3.321mA   -4.241mA
-433mV    -2.401mA   -2.341mA   -2.48mA
-341mV    -1.731mA   -1.759mA   -1.697mA
4mV       0A         0A         0A
1.1V      0A         0A         0A
[POWER_clamp]
|Voltage   I(typ)   I(min)   I(max)
-1.1V     8.546mA    10.74mA    6.188mA
-1.062V   6.562mA    8.339mA    4.834mA
-1.039V   5.631mA    7.13mA     4.282mA
-993mV    4.415mA    5.37mA     3.691mA
-924mV    3.565mA    3.939mA    3.345mA
-809mV    3.1mA      3.03mA     3.073mA
-556mV    2.744mA    2.555mA    2.674mA
295mV     2.265mA    2.092mA    2.249mA
617mV     1.854mA    1.7mA      1.948mA
824mV     1.22mA     1.058mA    1.442mA
1.054V    224.4uA    29.89uA    543.9uA
1.17V     0A         0A         0A
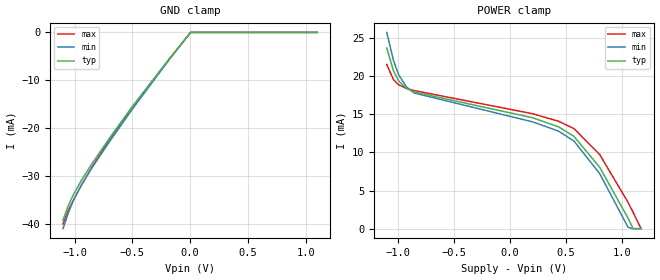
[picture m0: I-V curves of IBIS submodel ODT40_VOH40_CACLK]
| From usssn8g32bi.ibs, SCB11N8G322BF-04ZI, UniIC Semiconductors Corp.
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|   Submodel ODT40_VOH40_CACLK
[Submodel] ODT40_VOH40_CACLK
Submodel_type Dynamic_clamp
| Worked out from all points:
|   GND clamp passes 1 mA (typ) near -0.03 V on its own axis
[GND_clamp]
|Voltage   I(typ)   I(min)   I(max)
-1.1V     -39.27mA   -41.06mA   -40.08mA
-1.054V   -36.24mA   -37.75mA   -37.28mA
-1.008V   -33.85mA   -35.08mA   -34.98mA
-939mV    -30.88mA   -31.85mA   -31.91mA
-847mV    -27.39mA   -28.22mA   -28.1mA
-686mV    -21.73mA   -22.44mA   -21.99mA
-502mV    -15.59mA   -16.12mA   -15.7mA
-180mV    -5.51mA    -5.667mA   -5.584mA
4mV       0A         0A         0A
1.1V      0A         0A         0A
[POWER_clamp]
|Voltage   I(typ)   I(min)   I(max)
-1.1V     23.72mA    25.77mA    21.55mA
-1.039V   20.69mA    22.04mA    19.55mA
-993mV    19.39mA    20.19mA    18.88mA
-924mV    18.41mA    18.61mA    18.42mA
-855mV    17.94mA    17.81mA    18.13mA
203mV     14.56mA    14.02mA    15.09mA
433mV     13.37mA    12.81mA    14.11mA
571mV     12.12mA    11.51mA    13.14mA
801mV     8.061mA    7.224mA    9.734mA
1.054V    1.379mA    186.2uA    3.459mA
1.1V      0A         0A         2.122mA
1.17V     0A         0A         0A
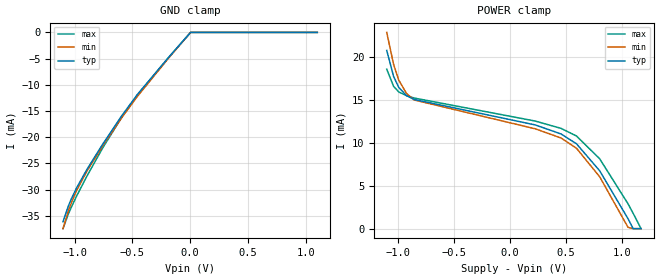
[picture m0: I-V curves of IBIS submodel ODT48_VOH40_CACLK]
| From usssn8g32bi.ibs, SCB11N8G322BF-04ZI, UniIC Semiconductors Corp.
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|   Submodel ODT48_VOH40_CACLK
[Submodel] ODT48_VOH40_CACLK
Submodel_type Dynamic_clamp
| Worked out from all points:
|   GND clamp passes 1 mA (typ) near -0.04 V on its own axis
[GND_clamp]
|Voltage   I(typ)   I(min)   I(max)
-1.1V     -36.16mA   -37.46mA   -37.47mA
-1.054V   -33.17mA   -34.12mA   -34.69mA
-1.031V   -31.94mA   -32.72mA   -33.52mA
-985mV    -29.8mA    -30.32mA   -31.37mA
-893mV    -26.17mA   -26.49mA   -27.44mA
-755mV    -21.29mA   -21.61mA   -22mA
-594mV    -15.99mA   -16.34mA   -16.3mA
-456mV    -11.84mA   -12.21mA   -11.96mA
-180mV    -4.6mA     -4.732mA   -4.662mA
4mV       0A         0A         0A
1.1V      0A         0A         0A
[POWER_clamp]
|Voltage   I(typ)   I(min)   I(max)
-1.1V     20.72mA    22.82mA    18.54mA
-1.039V   17.71mA    19.11mA    16.55mA
-993mV    16.43mA    17.28mA    15.9mA
-924mV    15.47mA    15.73mA    15.46mA
-855mV    15.02mA    14.96mA    15.19mA
226mV     12.06mA    11.61mA    12.51mA
456mV     11.01mA    10.54mA    11.66mA
594mV     9.865mA    9.347mA    10.77mA
801mV     6.726mA    6.029mA    8.122mA
1.054V    1.151mA    155.5uA    2.887mA
1.1V      0A         0A         1.772mA
1.17V     0A         0A         0A
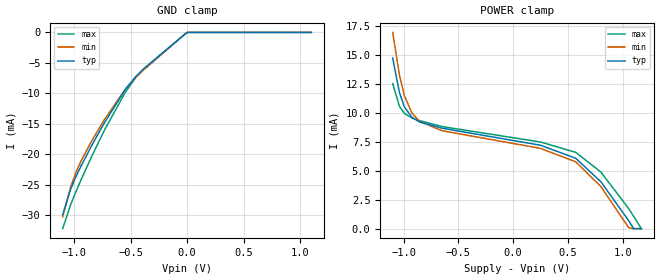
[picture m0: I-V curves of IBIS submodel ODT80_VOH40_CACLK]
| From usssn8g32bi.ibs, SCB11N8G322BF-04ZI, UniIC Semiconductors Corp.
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|   Submodel ODT80_VOH40_CACLK
[Submodel] ODT80_VOH40_CACLK
Submodel_type Dynamic_clamp
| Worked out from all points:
|   GND clamp passes 1 mA (typ) near -0.07 V on its own axis
[GND_clamp]
|Voltage   I(typ)   I(min)   I(max)
-1.1V     -29.91mA   -30.25mA   -32.21mA
-1.031V   -25.8mA    -25.44mA   -28.33mA
-985mV    -23.76mA   -23.07mA   -26.22mA
-939mV    -21.96mA   -21.13mA   -24.25mA
-847mV    -18.69mA   -17.91mA   -20.49mA
-732mV    -14.87mA   -14.34mA   -16.09mA
-548mV    -9.424mA   -9.351mA   -9.896mA
-456mV    -7.287mA   -7.425mA   -7.461mA
-387mV    -6.025mA   -6.208mA   -6.091mA
-19mV     -290.1uA   -296.9uA   -295.7uA
4mV       0A         0A         0A
1.1V      0A         0A         0A
[POWER_clamp]
|Voltage   I(typ)   I(min)   I(max)
-1.1V     14.7mA     16.91mA    12.5mA
-1.039V   11.74mA    13.25mA    10.55mA
-993mV    10.49mA    11.45mA    9.929mA
-924mV    9.587mA    9.961mA    9.537mA
-855mV    9.189mA    9.24mA     9.312mA
-648mV    8.653mA    8.434mA    8.794mA
249mV     7.188mA    6.918mA    7.467mA
571mV     6.067mA    5.763mA    6.576mA
801mV     4.04mA     3.622mA    4.878mA
1.054V    691.6uA    93.44uA    1.735mA
1.1V      0A         0A         1.065mA
1.17V     0A         0A         0A
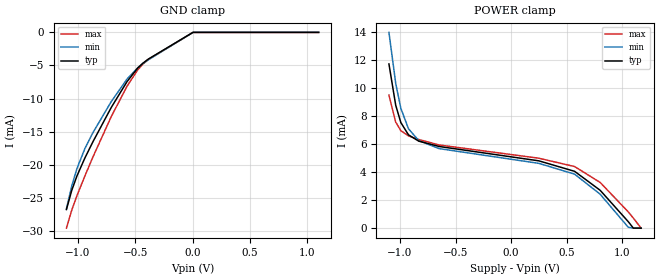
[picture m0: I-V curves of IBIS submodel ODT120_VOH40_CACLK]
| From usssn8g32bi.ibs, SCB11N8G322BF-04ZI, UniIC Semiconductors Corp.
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|   Submodel ODT120_VOH40_CACLK
[Submodel] ODT120_VOH40_CACLK
Submodel_type Dynamic_clamp
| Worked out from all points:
|   GND clamp passes 1 mA (typ) near -0.10 V on its own axis
[GND_clamp]
|Voltage   I(typ)   I(min)   I(max)
-1.1V     -26.78mA   -26.66mA   -29.59mA
-1.054V   -23.9mA    -23.24mA   -26.88mA
-1.008V   -21.69mA   -20.57mA   -24.67mA
-939mV    -18.99mA   -17.56mA   -21.7mA
-870mV    -16.57mA   -15.19mA   -18.88mA
-709mV    -11.35mA   -10.46mA   -12.73mA
-571mV    -7.432mA   -7.049mA   -8.131mA
-479mV    -5.407mA   -5.366mA   -5.694mA
-433mV    -4.657mA   -4.724mA   -4.794mA
-387mV    -4.054mA   -4.163mA   -4.114mA
4mV       0A         0A         0A
1.1V      0A         0A         0A
[POWER_clamp]
|Voltage   I(typ)   I(min)   I(max)
-1.1V     11.7mA     13.95mA    9.481mA
-1.039V   8.759mA    10.32mA    7.555mA
-993mV    7.524mA    8.542mA    6.946mA
-924mV    6.647mA    7.08mA     6.577mA
-832mV    6.199mA    6.24mA     6.318mA
-648mV    5.818mA    5.667mA    5.926mA
249mV     4.796mA    4.617mA    4.982mA
571mV     4.049mA    3.848mA    4.389mA
801mV     2.698mA    2.419mA    3.257mA
1.054V    462uA      62.43uA    1.159mA
1.1V      0A         0A         711.2uA
1.17V     0A         0A         0A
